VERSION 5.8 ;
BUSBITCHARS "[]" ;
DIVIDERCHAR "/" ;
UNITS
    DATABASE MICRONS 1000 ;
END UNITS

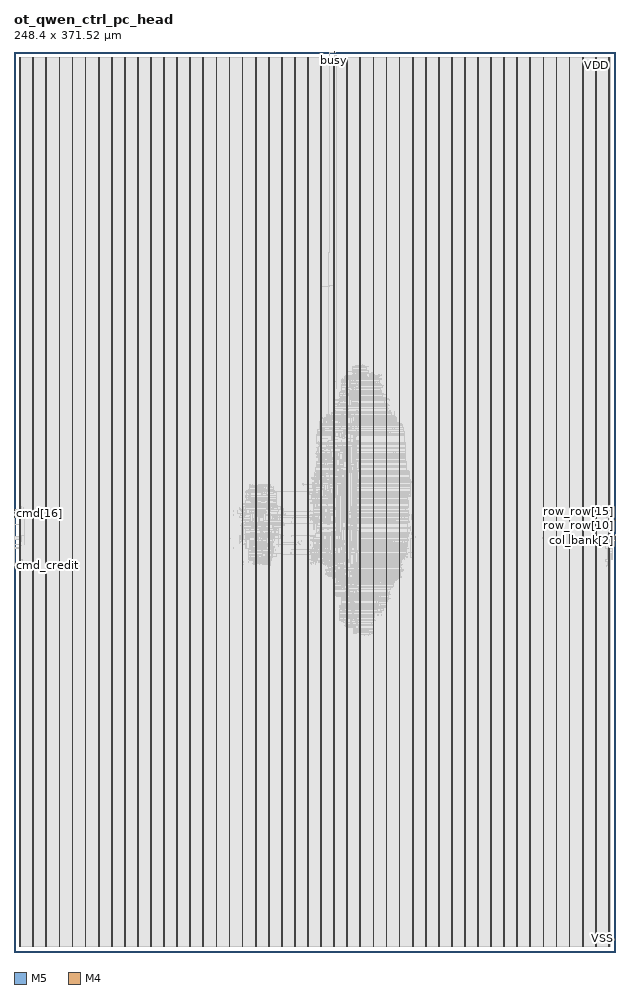
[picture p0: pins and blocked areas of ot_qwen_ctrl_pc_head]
MACRO ot_qwen_ctrl_pc_head
  FOREIGN ot_qwen_ctrl_pc_head 0 0 ;
  CLASS BLOCK ;
  SIZE 248.4 BY 371.52 ;
  PIN busy
    DIRECTION OUTPUT ;
    USE SIGNAL ;
    PORT
      LAYER M5 ;
        RECT  132.144 371.436 132.168 371.52 ;
    END
  END busy
  PIN clk
    DIRECTION INPUT ;
    USE SIGNAL ;
    PORT
      LAYER M5 ;
        RECT  132.24 371.436 132.264 371.52 ;
    END
  END clk
  PIN cmd[0]
    DIRECTION INPUT ;
    USE SIGNAL ;
    PORT
      LAYER M4 ;
        RECT  0 179.568 0.084 179.592 ;
    END
  END cmd[0]
  PIN cmd[10]
    DIRECTION INPUT ;
    USE SIGNAL ;
    PORT
      LAYER M4 ;
        RECT  0 180.528 0.084 180.552 ;
    END
  END cmd[10]
  PIN cmd[11]
    DIRECTION INPUT ;
    USE SIGNAL ;
    PORT
      LAYER M4 ;
        RECT  0 180.624 0.084 180.648 ;
    END
  END cmd[11]
  PIN cmd[12]
    DIRECTION INPUT ;
    USE SIGNAL ;
    PORT
      LAYER M4 ;
        RECT  0 180.72 0.084 180.744 ;
    END
  END cmd[12]
  PIN cmd[13]
    DIRECTION INPUT ;
    USE SIGNAL ;
    PORT
      LAYER M4 ;
        RECT  0 180.816 0.084 180.84 ;
    END
  END cmd[13]
  PIN cmd[14]
    DIRECTION INPUT ;
    USE SIGNAL ;
    PORT
      LAYER M4 ;
        RECT  0 180.912 0.084 180.936 ;
    END
  END cmd[14]
  PIN cmd[15]
    DIRECTION INPUT ;
    USE SIGNAL ;
    PORT
      LAYER M4 ;
        RECT  0 181.008 0.084 181.032 ;
    END
  END cmd[15]
  PIN cmd[16]
    DIRECTION INPUT ;
    USE SIGNAL ;
    PORT
      LAYER M4 ;
        RECT  0 181.104 0.084 181.128 ;
    END
  END cmd[16]
  PIN cmd[17]
    DIRECTION INPUT ;
    USE SIGNAL ;
    PORT
      LAYER M4 ;
        RECT  0 181.2 0.084 181.224 ;
    END
  END cmd[17]
  PIN cmd[18]
    DIRECTION INPUT ;
    USE SIGNAL ;
    PORT
      LAYER M4 ;
        RECT  0 181.296 0.084 181.32 ;
    END
  END cmd[18]
  PIN cmd[19]
    DIRECTION INPUT ;
    USE SIGNAL ;
    PORT
      LAYER M4 ;
        RECT  0 181.392 0.084 181.416 ;
    END
  END cmd[19]
  PIN cmd[1]
    DIRECTION INPUT ;
    USE SIGNAL ;
    PORT
      LAYER M4 ;
        RECT  0 179.664 0.084 179.688 ;
    END
  END cmd[1]
  PIN cmd[20]
    DIRECTION INPUT ;
    USE SIGNAL ;
    PORT
      LAYER M4 ;
        RECT  0 181.488 0.084 181.512 ;
    END
  END cmd[20]
  PIN cmd[21]
    DIRECTION INPUT ;
    USE SIGNAL ;
    PORT
      LAYER M4 ;
        RECT  0 181.584 0.084 181.608 ;
    END
  END cmd[21]
  PIN cmd[22]
    DIRECTION INPUT ;
    USE SIGNAL ;
    PORT
      LAYER M4 ;
        RECT  0 181.68 0.084 181.704 ;
    END
  END cmd[22]
  PIN cmd[23]
    DIRECTION INPUT ;
    USE SIGNAL ;
    PORT
      LAYER M4 ;
        RECT  0 181.776 0.084 181.8 ;
    END
  END cmd[23]
  PIN cmd[24]
    DIRECTION INPUT ;
    USE SIGNAL ;
    PORT
      LAYER M4 ;
        RECT  0 181.872 0.084 181.896 ;
    END
  END cmd[24]
  PIN cmd[25]
    DIRECTION INPUT ;
    USE SIGNAL ;
    PORT
      LAYER M4 ;
        RECT  0 181.968 0.084 181.992 ;
    END
  END cmd[25]
  PIN cmd[26]
    DIRECTION INPUT ;
    USE SIGNAL ;
    PORT
      LAYER M4 ;
        RECT  0 182.064 0.084 182.088 ;
    END
  END cmd[26]
  PIN cmd[27]
    DIRECTION INPUT ;
    USE SIGNAL ;
    PORT
      LAYER M4 ;
        RECT  0 182.16 0.084 182.184 ;
    END
  END cmd[27]
  PIN cmd[28]
    DIRECTION INPUT ;
    USE SIGNAL ;
    PORT
      LAYER M4 ;
        RECT  0 182.256 0.084 182.28 ;
    END
  END cmd[28]
  PIN cmd[29]
    DIRECTION INPUT ;
    USE SIGNAL ;
    PORT
      LAYER M4 ;
        RECT  0 182.352 0.084 182.376 ;
    END
  END cmd[29]
  PIN cmd[2]
    DIRECTION INPUT ;
    USE SIGNAL ;
    PORT
      LAYER M4 ;
        RECT  0 179.76 0.084 179.784 ;
    END
  END cmd[2]
  PIN cmd[30]
    DIRECTION INPUT ;
    USE SIGNAL ;
    PORT
      LAYER M4 ;
        RECT  0 182.448 0.084 182.472 ;
    END
  END cmd[30]
  PIN cmd[31]
    DIRECTION INPUT ;
    USE SIGNAL ;
    PORT
      LAYER M4 ;
        RECT  0 182.544 0.084 182.568 ;
    END
  END cmd[31]
  PIN cmd[3]
    DIRECTION INPUT ;
    USE SIGNAL ;
    PORT
      LAYER M4 ;
        RECT  0 179.856 0.084 179.88 ;
    END
  END cmd[3]
  PIN cmd[4]
    DIRECTION INPUT ;
    USE SIGNAL ;
    PORT
      LAYER M4 ;
        RECT  0 179.952 0.084 179.976 ;
    END
  END cmd[4]
  PIN cmd[5]
    DIRECTION INPUT ;
    USE SIGNAL ;
    PORT
      LAYER M4 ;
        RECT  0 180.048 0.084 180.072 ;
    END
  END cmd[5]
  PIN cmd[6]
    DIRECTION INPUT ;
    USE SIGNAL ;
    PORT
      LAYER M4 ;
        RECT  0 180.144 0.084 180.168 ;
    END
  END cmd[6]
  PIN cmd[7]
    DIRECTION INPUT ;
    USE SIGNAL ;
    PORT
      LAYER M4 ;
        RECT  0 180.24 0.084 180.264 ;
    END
  END cmd[7]
  PIN cmd[8]
    DIRECTION INPUT ;
    USE SIGNAL ;
    PORT
      LAYER M4 ;
        RECT  0 180.336 0.084 180.36 ;
    END
  END cmd[8]
  PIN cmd[9]
    DIRECTION INPUT ;
    USE SIGNAL ;
    PORT
      LAYER M4 ;
        RECT  0 180.432 0.084 180.456 ;
    END
  END cmd[9]
  PIN cmd_credit
    DIRECTION OUTPUT ;
    USE SIGNAL ;
    PORT
      LAYER M4 ;
        RECT  0 159.6 0.084 159.624 ;
    END
  END cmd_credit
  PIN cmd_v
    DIRECTION INPUT ;
    USE SIGNAL ;
    PORT
      LAYER M4 ;
        RECT  0 159.696 0.084 159.72 ;
    END
  END cmd_v
  PIN col_bank[0]
    DIRECTION OUTPUT ;
    USE SIGNAL ;
    PORT
      LAYER M4 ;
        RECT  248.316 169.68 248.4 169.704 ;
    END
  END col_bank[0]
  PIN col_bank[1]
    DIRECTION OUTPUT ;
    USE SIGNAL ;
    PORT
      LAYER M4 ;
        RECT  248.316 169.776 248.4 169.8 ;
    END
  END col_bank[1]
  PIN col_bank[2]
    DIRECTION OUTPUT ;
    USE SIGNAL ;
    PORT
      LAYER M4 ;
        RECT  248.316 169.872 248.4 169.896 ;
    END
  END col_bank[2]
  PIN col_bank[3]
    DIRECTION OUTPUT ;
    USE SIGNAL ;
    PORT
      LAYER M4 ;
        RECT  248.316 169.968 248.4 169.992 ;
    END
  END col_bank[3]
  PIN col_bank[4]
    DIRECTION OUTPUT ;
    USE SIGNAL ;
    PORT
      LAYER M4 ;
        RECT  248.316 170.064 248.4 170.088 ;
    END
  END col_bank[4]
  PIN col_col[0]
    DIRECTION OUTPUT ;
    USE SIGNAL ;
    PORT
      LAYER M4 ;
        RECT  248.316 170.16 248.4 170.184 ;
    END
  END col_col[0]
  PIN col_col[1]
    DIRECTION OUTPUT ;
    USE SIGNAL ;
    PORT
      LAYER M4 ;
        RECT  248.316 170.256 248.4 170.28 ;
    END
  END col_col[1]
  PIN col_col[2]
    DIRECTION OUTPUT ;
    USE SIGNAL ;
    PORT
      LAYER M4 ;
        RECT  248.316 170.352 248.4 170.376 ;
    END
  END col_col[2]
  PIN col_col[3]
    DIRECTION OUTPUT ;
    USE SIGNAL ;
    PORT
      LAYER M4 ;
        RECT  248.316 170.448 248.4 170.472 ;
    END
  END col_col[3]
  PIN col_col[4]
    DIRECTION OUTPUT ;
    USE SIGNAL ;
    PORT
      LAYER M4 ;
        RECT  248.316 170.544 248.4 170.568 ;
    END
  END col_col[4]
  PIN col_v
    DIRECTION OUTPUT ;
    USE SIGNAL ;
    PORT
      LAYER M4 ;
        RECT  248.316 170.64 248.4 170.664 ;
    END
  END col_v
  PIN col_we
    DIRECTION OUTPUT ;
    USE SIGNAL ;
    PORT
      LAYER M4 ;
        RECT  248.316 170.736 248.4 170.76 ;
    END
  END col_we
  PIN fault
    DIRECTION OUTPUT ;
    USE SIGNAL ;
    PORT
      LAYER M5 ;
        RECT  132.336 371.436 132.36 371.52 ;
    END
  END fault
  PIN read_credit[0]
    DIRECTION INPUT ;
    USE SIGNAL ;
    PORT
      LAYER M4 ;
        RECT  0 159.792 0.084 159.816 ;
    END
  END read_credit[0]
  PIN read_credit[1]
    DIRECTION INPUT ;
    USE SIGNAL ;
    PORT
      LAYER M4 ;
        RECT  0 159.888 0.084 159.912 ;
    END
  END read_credit[1]
  PIN read_credit[2]
    DIRECTION INPUT ;
    USE SIGNAL ;
    PORT
      LAYER M4 ;
        RECT  0 159.984 0.084 160.008 ;
    END
  END read_credit[2]
  PIN row_bank[0]
    DIRECTION OUTPUT ;
    USE SIGNAL ;
    PORT
      LAYER M4 ;
        RECT  248.316 170.832 248.4 170.856 ;
    END
  END row_bank[0]
  PIN row_bank[1]
    DIRECTION OUTPUT ;
    USE SIGNAL ;
    PORT
      LAYER M4 ;
        RECT  248.316 170.928 248.4 170.952 ;
    END
  END row_bank[1]
  PIN row_bank[2]
    DIRECTION OUTPUT ;
    USE SIGNAL ;
    PORT
      LAYER M4 ;
        RECT  248.316 171.024 248.4 171.048 ;
    END
  END row_bank[2]
  PIN row_bank[3]
    DIRECTION OUTPUT ;
    USE SIGNAL ;
    PORT
      LAYER M4 ;
        RECT  248.316 171.12 248.4 171.144 ;
    END
  END row_bank[3]
  PIN row_bank[4]
    DIRECTION OUTPUT ;
    USE SIGNAL ;
    PORT
      LAYER M4 ;
        RECT  248.316 171.216 248.4 171.24 ;
    END
  END row_bank[4]
  PIN row_op[0]
    DIRECTION OUTPUT ;
    USE SIGNAL ;
    PORT
      LAYER M4 ;
        RECT  248.316 171.312 248.4 171.336 ;
    END
  END row_op[0]
  PIN row_op[1]
    DIRECTION OUTPUT ;
    USE SIGNAL ;
    PORT
      LAYER M4 ;
        RECT  248.316 171.408 248.4 171.432 ;
    END
  END row_op[1]
  PIN row_op[2]
    DIRECTION OUTPUT ;
    USE SIGNAL ;
    PORT
      LAYER M4 ;
        RECT  248.316 171.504 248.4 171.528 ;
    END
  END row_op[2]
  PIN row_row[0]
    DIRECTION OUTPUT ;
    USE SIGNAL ;
    PORT
      LAYER M4 ;
        RECT  248.316 171.6 248.4 171.624 ;
    END
  END row_row[0]
  PIN row_row[10]
    DIRECTION OUTPUT ;
    USE SIGNAL ;
    PORT
      LAYER M4 ;
        RECT  248.316 172.56 248.4 172.584 ;
    END
  END row_row[10]
  PIN row_row[11]
    DIRECTION OUTPUT ;
    USE SIGNAL ;
    PORT
      LAYER M4 ;
        RECT  248.316 172.656 248.4 172.68 ;
    END
  END row_row[11]
  PIN row_row[12]
    DIRECTION OUTPUT ;
    USE SIGNAL ;
    PORT
      LAYER M4 ;
        RECT  248.316 178.128 248.4 178.152 ;
    END
  END row_row[12]
  PIN row_row[13]
    DIRECTION OUTPUT ;
    USE SIGNAL ;
    PORT
      LAYER M4 ;
        RECT  248.316 178.224 248.4 178.248 ;
    END
  END row_row[13]
  PIN row_row[14]
    DIRECTION OUTPUT ;
    USE SIGNAL ;
    PORT
      LAYER M4 ;
        RECT  248.316 178.32 248.4 178.344 ;
    END
  END row_row[14]
  PIN row_row[15]
    DIRECTION OUTPUT ;
    USE SIGNAL ;
    PORT
      LAYER M4 ;
        RECT  248.316 178.416 248.4 178.44 ;
    END
  END row_row[15]
  PIN row_row[16]
    DIRECTION OUTPUT ;
    USE SIGNAL ;
    PORT
      LAYER M4 ;
        RECT  248.316 178.512 248.4 178.536 ;
    END
  END row_row[16]
  PIN row_row[17]
    DIRECTION OUTPUT ;
    USE SIGNAL ;
    PORT
      LAYER M4 ;
        RECT  248.316 178.608 248.4 178.632 ;
    END
  END row_row[17]
  PIN row_row[18]
    DIRECTION OUTPUT ;
    USE SIGNAL ;
    PORT
      LAYER M4 ;
        RECT  248.316 178.704 248.4 178.728 ;
    END
  END row_row[18]
  PIN row_row[1]
    DIRECTION OUTPUT ;
    USE SIGNAL ;
    PORT
      LAYER M4 ;
        RECT  248.316 171.696 248.4 171.72 ;
    END
  END row_row[1]
  PIN row_row[2]
    DIRECTION OUTPUT ;
    USE SIGNAL ;
    PORT
      LAYER M4 ;
        RECT  248.316 171.792 248.4 171.816 ;
    END
  END row_row[2]
  PIN row_row[3]
    DIRECTION OUTPUT ;
    USE SIGNAL ;
    PORT
      LAYER M4 ;
        RECT  248.316 171.888 248.4 171.912 ;
    END
  END row_row[3]
  PIN row_row[4]
    DIRECTION OUTPUT ;
    USE SIGNAL ;
    PORT
      LAYER M4 ;
        RECT  248.316 171.984 248.4 172.008 ;
    END
  END row_row[4]
  PIN row_row[5]
    DIRECTION OUTPUT ;
    USE SIGNAL ;
    PORT
      LAYER M4 ;
        RECT  248.316 172.08 248.4 172.104 ;
    END
  END row_row[5]
  PIN row_row[6]
    DIRECTION OUTPUT ;
    USE SIGNAL ;
    PORT
      LAYER M4 ;
        RECT  248.316 172.176 248.4 172.2 ;
    END
  END row_row[6]
  PIN row_row[7]
    DIRECTION OUTPUT ;
    USE SIGNAL ;
    PORT
      LAYER M4 ;
        RECT  248.316 172.272 248.4 172.296 ;
    END
  END row_row[7]
  PIN row_row[8]
    DIRECTION OUTPUT ;
    USE SIGNAL ;
    PORT
      LAYER M4 ;
        RECT  248.316 172.368 248.4 172.392 ;
    END
  END row_row[8]
  PIN row_row[9]
    DIRECTION OUTPUT ;
    USE SIGNAL ;
    PORT
      LAYER M4 ;
        RECT  248.316 172.464 248.4 172.488 ;
    END
  END row_row[9]
  PIN row_v
    DIRECTION OUTPUT ;
    USE SIGNAL ;
    PORT
      LAYER M4 ;
        RECT  248.316 178.8 248.4 178.824 ;
    END
  END row_v
  PIN rst_n
    DIRECTION INPUT ;
    USE SIGNAL ;
    PORT
      LAYER M5 ;
        RECT  132.432 371.436 132.456 371.52 ;
    END
  END rst_n
  PIN VDD
    DIRECTION INOUT ;
    USE POWER ;
    PORT
      LAYER M5 ;
        RECT  245.592 2.151 245.712 369.369 ;
        RECT  240.192 2.151 240.312 369.369 ;
        RECT  234.792 2.151 234.912 369.369 ;
        RECT  229.392 2.151 229.512 369.369 ;
        RECT  223.992 2.151 224.112 369.369 ;
        RECT  218.592 2.151 218.712 369.369 ;
        RECT  213.192 2.151 213.312 369.369 ;
        RECT  207.792 2.151 207.912 369.369 ;
        RECT  202.392 2.151 202.512 369.369 ;
        RECT  196.992 2.151 197.112 369.369 ;
        RECT  191.592 2.151 191.712 369.369 ;
        RECT  186.192 2.151 186.312 369.369 ;
        RECT  180.792 2.151 180.912 369.369 ;
        RECT  175.392 2.151 175.512 369.369 ;
        RECT  169.992 2.151 170.112 369.369 ;
        RECT  164.592 2.151 164.712 369.369 ;
        RECT  159.192 2.151 159.312 369.369 ;
        RECT  153.792 2.151 153.912 369.369 ;
        RECT  148.392 2.151 148.512 369.369 ;
        RECT  142.992 2.151 143.112 369.369 ;
        RECT  137.592 2.151 137.712 369.369 ;
        RECT  132.192 2.151 132.312 369.369 ;
        RECT  126.792 2.151 126.912 369.369 ;
        RECT  121.392 2.151 121.512 369.369 ;
        RECT  115.992 2.151 116.112 369.369 ;
        RECT  110.592 2.151 110.712 369.369 ;
        RECT  105.192 2.151 105.312 369.369 ;
        RECT  99.792 2.151 99.912 369.369 ;
        RECT  94.392 2.151 94.512 369.369 ;
        RECT  88.992 2.151 89.112 369.369 ;
        RECT  83.592 2.151 83.712 369.369 ;
        RECT  78.192 2.151 78.312 369.369 ;
        RECT  72.792 2.151 72.912 369.369 ;
        RECT  67.392 2.151 67.512 369.369 ;
        RECT  61.992 2.151 62.112 369.369 ;
        RECT  56.592 2.151 56.712 369.369 ;
        RECT  51.192 2.151 51.312 369.369 ;
        RECT  45.792 2.151 45.912 369.369 ;
        RECT  40.392 2.151 40.512 369.369 ;
        RECT  34.992 2.151 35.112 369.369 ;
        RECT  29.592 2.151 29.712 369.369 ;
        RECT  24.192 2.151 24.312 369.369 ;
        RECT  18.792 2.151 18.912 369.369 ;
        RECT  13.392 2.151 13.512 369.369 ;
        RECT  7.992 2.151 8.112 369.369 ;
        RECT  2.592 2.151 2.712 369.369 ;
    END
  END VDD
  PIN VSS
    DIRECTION INOUT ;
    USE GROUND ;
    PORT
      LAYER M5 ;
        RECT  245.4 2.137 245.52 369.383 ;
        RECT  240 2.137 240.12 369.383 ;
        RECT  234.6 2.137 234.72 369.383 ;
        RECT  229.2 2.137 229.32 369.383 ;
        RECT  223.8 2.137 223.92 369.383 ;
        RECT  218.4 2.137 218.52 369.383 ;
        RECT  213 2.137 213.12 369.383 ;
        RECT  207.6 2.137 207.72 369.383 ;
        RECT  202.2 2.137 202.32 369.383 ;
        RECT  196.8 2.137 196.92 369.383 ;
        RECT  191.4 2.137 191.52 369.383 ;
        RECT  186 2.137 186.12 369.383 ;
        RECT  180.6 2.137 180.72 369.383 ;
        RECT  175.2 2.137 175.32 369.383 ;
        RECT  169.8 2.137 169.92 369.383 ;
        RECT  164.4 2.137 164.52 369.383 ;
        RECT  159 2.137 159.12 369.383 ;
        RECT  153.6 2.137 153.72 369.383 ;
        RECT  148.2 2.137 148.32 369.383 ;
        RECT  142.8 2.137 142.92 369.383 ;
        RECT  137.4 2.137 137.52 369.383 ;
        RECT  132 2.137 132.12 369.383 ;
        RECT  126.6 2.137 126.72 369.383 ;
        RECT  121.2 2.137 121.32 369.383 ;
        RECT  115.8 2.137 115.92 369.383 ;
        RECT  110.4 2.137 110.52 369.383 ;
        RECT  105 2.137 105.12 369.383 ;
        RECT  99.6 2.137 99.72 369.383 ;
        RECT  94.2 2.137 94.32 369.383 ;
        RECT  88.8 2.137 88.92 369.383 ;
        RECT  83.4 2.137 83.52 369.383 ;
        RECT  78 2.137 78.12 369.383 ;
        RECT  72.6 2.137 72.72 369.383 ;
        RECT  67.2 2.137 67.32 369.383 ;
        RECT  61.8 2.137 61.92 369.383 ;
        RECT  56.4 2.137 56.52 369.383 ;
        RECT  51 2.137 51.12 369.383 ;
        RECT  45.6 2.137 45.72 369.383 ;
        RECT  40.2 2.137 40.32 369.383 ;
        RECT  34.8 2.137 34.92 369.383 ;
        RECT  29.4 2.137 29.52 369.383 ;
        RECT  24 2.137 24.12 369.383 ;
        RECT  18.6 2.137 18.72 369.383 ;
        RECT  13.2 2.137 13.32 369.383 ;
        RECT  7.8 2.137 7.92 369.383 ;
        RECT  2.4 2.137 2.52 369.383 ;
    END
  END VSS
  OBS
    LAYER RVTN ;
     RECT  2.16 2.16 246.24 2.295 ;
     RECT  2.16 2.565 246.24 2.835 ;
     RECT  2.16 3.105 246.24 3.375 ;
     RECT  2.16 3.645 246.24 3.915 ;
     RECT  2.16 4.185 246.24 4.455 ;
     RECT  2.16 4.725 246.24 4.995 ;
     RECT  2.16 5.265 246.24 5.535 ;
     RECT  2.16 5.805 246.24 6.075 ;
     RECT  2.16 6.345 246.24 6.615 ;
     RECT  2.16 6.885 246.24 7.155 ;
     RECT  2.16 7.425 246.24 7.695 ;
     RECT  2.16 7.965 246.24 8.235 ;
     RECT  2.16 8.505 246.24 8.775 ;
     RECT  2.16 9.045 246.24 9.315 ;
     RECT  2.16 9.585 246.24 9.855 ;
     RECT  2.16 10.125 246.24 10.395 ;
     RECT  2.16 10.665 246.24 10.935 ;
     RECT  2.16 11.205 246.24 11.475 ;
     RECT  2.16 11.745 246.24 12.015 ;
     RECT  2.16 12.285 246.24 12.555 ;
     RECT  2.16 12.825 246.24 13.095 ;
     RECT  2.16 13.365 246.24 13.635 ;
     RECT  2.16 13.905 246.24 14.175 ;
     RECT  2.16 14.445 246.24 14.715 ;
     RECT  2.16 14.985 246.24 15.255 ;
     RECT  2.16 15.525 246.24 15.795 ;
     RECT  2.16 16.065 246.24 16.335 ;
     RECT  2.16 16.605 246.24 16.875 ;
     RECT  2.16 17.145 246.24 17.415 ;
     RECT  2.16 17.685 246.24 17.955 ;
     RECT  2.16 18.225 246.24 18.495 ;
     RECT  2.16 18.765 246.24 19.035 ;
     RECT  2.16 19.305 246.24 19.575 ;
     RECT  2.16 19.845 246.24 20.115 ;
     RECT  2.16 20.385 246.24 20.655 ;
     RECT  2.16 20.925 246.24 21.195 ;
     RECT  2.16 21.465 246.24 21.735 ;
     RECT  2.16 22.005 246.24 22.275 ;
     RECT  2.16 22.545 246.24 22.815 ;
     RECT  2.16 23.085 246.24 23.355 ;
     RECT  2.16 23.625 246.24 23.895 ;
     RECT  2.16 24.165 246.24 24.435 ;
     RECT  2.16 24.705 246.24 24.975 ;
     RECT  2.16 25.245 246.24 25.515 ;
     RECT  2.16 25.785 246.24 26.055 ;
     RECT  2.16 26.325 246.24 26.595 ;
     RECT  2.16 26.865 246.24 27.135 ;
     RECT  2.16 27.405 246.24 27.675 ;
     RECT  2.16 27.945 246.24 28.215 ;
     RECT  2.16 28.485 246.24 28.755 ;
     RECT  2.16 29.025 246.24 29.295 ;
     RECT  2.16 29.565 246.24 29.835 ;
     RECT  2.16 30.105 246.24 30.375 ;
     RECT  2.16 30.645 246.24 30.915 ;
     RECT  2.16 31.185 246.24 31.455 ;
     RECT  2.16 31.725 246.24 31.995 ;
     RECT  2.16 32.265 246.24 32.535 ;
     RECT  2.16 32.805 246.24 33.075 ;
     RECT  2.16 33.345 246.24 33.615 ;
     RECT  2.16 33.885 246.24 34.155 ;
     RECT  2.16 34.425 246.24 34.695 ;
     RECT  2.16 34.965 246.24 35.235 ;
     RECT  2.16 35.505 246.24 35.775 ;
     RECT  2.16 36.045 246.24 36.315 ;
     RECT  2.16 36.585 246.24 36.855 ;
     RECT  2.16 37.125 246.24 37.395 ;
     RECT  2.16 37.665 246.24 37.935 ;
     RECT  2.16 38.205 246.24 38.475 ;
     RECT  2.16 38.745 246.24 39.015 ;
     RECT  2.16 39.285 246.24 39.555 ;
     RECT  2.16 39.825 246.24 40.095 ;
     RECT  2.16 40.365 246.24 40.635 ;
     RECT  2.16 40.905 246.24 41.175 ;
     RECT  2.16 41.445 246.24 41.715 ;
     RECT  2.16 41.985 246.24 42.255 ;
     RECT  2.16 42.525 246.24 42.795 ;
     RECT  2.16 43.065 246.24 43.335 ;
     RECT  2.16 43.605 246.24 43.875 ;
     RECT  2.16 44.145 246.24 44.415 ;
     RECT  2.16 44.685 246.24 44.955 ;
     RECT  2.16 45.225 246.24 45.495 ;
     RECT  2.16 45.765 246.24 46.035 ;
     RECT  2.16 46.305 246.24 46.575 ;
     RECT  2.16 46.845 246.24 47.115 ;
     RECT  2.16 47.385 246.24 47.655 ;
     RECT  2.16 47.925 246.24 48.195 ;
     RECT  2.16 48.465 246.24 48.735 ;
     RECT  2.16 49.005 246.24 49.275 ;
     RECT  2.16 49.545 246.24 49.815 ;
     RECT  2.16 50.085 246.24 50.355 ;
     RECT  2.16 50.625 246.24 50.895 ;
     RECT  2.16 51.165 246.24 51.435 ;
     RECT  2.16 51.705 246.24 51.975 ;
     RECT  2.16 52.245 246.24 52.515 ;
     RECT  2.16 52.785 246.24 53.055 ;
     RECT  2.16 53.325 246.24 53.595 ;
     RECT  2.16 53.865 246.24 54.135 ;
     RECT  2.16 54.405 246.24 54.675 ;
     RECT  2.16 54.945 246.24 55.215 ;
     RECT  2.16 55.485 246.24 55.755 ;
     RECT  2.16 56.025 246.24 56.295 ;
     RECT  2.16 56.565 246.24 56.835 ;
     RECT  2.16 57.105 246.24 57.375 ;
     RECT  2.16 57.645 246.24 57.915 ;
     RECT  2.16 58.185 246.24 58.455 ;
     RECT  2.16 58.725 246.24 58.995 ;
     RECT  2.16 59.265 246.24 59.535 ;
     RECT  2.16 59.805 246.24 60.075 ;
     RECT  2.16 60.345 246.24 60.615 ;
     RECT  2.16 60.885 246.24 61.155 ;
     RECT  2.16 61.425 246.24 61.695 ;
     RECT  2.16 61.965 246.24 62.235 ;
     RECT  2.16 62.505 246.24 62.775 ;
     RECT  2.16 63.045 246.24 63.315 ;
     RECT  2.16 63.585 246.24 63.855 ;
     RECT  2.16 64.125 246.24 64.395 ;
     RECT  2.16 64.665 246.24 64.935 ;
     RECT  2.16 65.205 246.24 65.475 ;
     RECT  2.16 65.745 246.24 66.015 ;
     RECT  2.16 66.285 246.24 66.555 ;
     RECT  2.16 66.825 246.24 67.095 ;
     RECT  2.16 67.365 246.24 67.635 ;
     RECT  2.16 67.905 246.24 68.175 ;
     RECT  2.16 68.445 246.24 68.715 ;
     RECT  2.16 68.985 246.24 69.255 ;
     RECT  2.16 69.525 246.24 69.795 ;
     RECT  2.16 70.065 246.24 70.335 ;
     RECT  2.16 70.605 246.24 70.875 ;
     RECT  2.16 71.145 246.24 71.415 ;
     RECT  2.16 71.685 246.24 71.955 ;
     RECT  2.16 72.225 246.24 72.495 ;
     RECT  2.16 72.765 246.24 73.035 ;
     RECT  2.16 73.305 246.24 73.575 ;
     RECT  2.16 73.845 246.24 74.115 ;
     RECT  2.16 74.385 246.24 74.655 ;
     RECT  2.16 74.925 246.24 75.195 ;
     RECT  2.16 75.465 246.24 75.735 ;
     RECT  2.16 76.005 246.24 76.275 ;
     RECT  2.16 76.545 246.24 76.815 ;
     RECT  2.16 77.085 246.24 77.355 ;
     RECT  2.16 77.625 246.24 77.895 ;
     RECT  2.16 78.165 246.24 78.435 ;
     RECT  2.16 78.705 246.24 78.975 ;
     RECT  2.16 79.245 246.24 79.515 ;
     RECT  2.16 79.785 246.24 80.055 ;
     RECT  2.16 80.325 246.24 80.595 ;
     RECT  2.16 80.865 246.24 81.135 ;
     RECT  2.16 81.405 246.24 81.675 ;
     RECT  2.16 81.945 246.24 82.215 ;
     RECT  2.16 82.485 246.24 82.755 ;
     RECT  2.16 83.025 246.24 83.295 ;
     RECT  2.16 83.565 246.24 83.835 ;
     RECT  2.16 84.105 246.24 84.375 ;
     RECT  2.16 84.645 246.24 84.915 ;
     RECT  2.16 85.185 246.24 85.455 ;
     RECT  2.16 85.725 246.24 85.995 ;
     RECT  2.16 86.265 246.24 86.535 ;
     RECT  2.16 86.805 246.24 87.075 ;
     RECT  2.16 87.345 246.24 87.615 ;
     RECT  2.16 87.885 246.24 88.155 ;
     RECT  2.16 88.425 246.24 88.695 ;
     RECT  2.16 88.965 246.24 89.235 ;
     RECT  2.16 89.505 246.24 89.775 ;
     RECT  2.16 90.045 246.24 90.315 ;
     RECT  2.16 90.585 246.24 90.855 ;
     RECT  2.16 91.125 246.24 91.395 ;
     RECT  2.16 91.665 246.24 91.935 ;
     RECT  2.16 92.205 246.24 92.475 ;
     RECT  2.16 92.745 246.24 93.015 ;
     RECT  2.16 93.285 246.24 93.555 ;
     RECT  2.16 93.825 246.24 94.095 ;
     RECT  2.16 94.365 246.24 94.635 ;
     RECT  2.16 94.905 246.24 95.175 ;
     RECT  2.16 95.445 246.24 95.715 ;
     RECT  2.16 95.985 246.24 96.255 ;
     RECT  2.16 96.525 246.24 96.795 ;
     RECT  2.16 97.065 246.24 97.335 ;
     RECT  2.16 97.605 246.24 97.875 ;
     RECT  2.16 98.145 246.24 98.415 ;
     RECT  2.16 98.685 246.24 98.955 ;
     RECT  2.16 99.225 246.24 99.495 ;
     RECT  2.16 99.765 246.24 100.035 ;
     RECT  2.16 100.305 246.24 100.575 ;
     RECT  2.16 100.845 246.24 101.115 ;
     RECT  2.16 101.385 246.24 101.655 ;
     RECT  2.16 101.925 246.24 102.195 ;
     RECT  2.16 102.465 246.24 102.735 ;
     RECT  2.16 103.005 246.24 103.275 ;
     RECT  2.16 103.545 246.24 103.815 ;
     RECT  2.16 104.085 246.24 104.355 ;
     RECT  2.16 104.625 246.24 104.895 ;
     RECT  2.16 105.165 246.24 105.435 ;
     RECT  2.16 105.705 246.24 105.975 ;
     RECT  2.16 106.245 246.24 106.515 ;
     RECT  2.16 106.785 246.24 107.055 ;
     RECT  2.16 107.325 246.24 107.595 ;
     RECT  2.16 107.865 246.24 108.135 ;
     RECT  2.16 108.405 246.24 108.675 ;
     RECT  2.16 108.945 246.24 109.215 ;
     RECT  2.16 109.485 246.24 109.755 ;
     RECT  2.16 110.025 246.24 110.295 ;
     RECT  2.16 110.565 246.24 110.835 ;
     RECT  2.16 111.105 246.24 111.375 ;
     RECT  2.16 111.645 246.24 111.915 ;
     RECT  2.16 112.185 246.24 112.455 ;
     RECT  2.16 112.725 246.24 112.995 ;
     RECT  2.16 113.265 246.24 113.535 ;
     RECT  2.16 113.805 246.24 114.075 ;
     RECT  2.16 114.345 246.24 114.615 ;
     RECT  2.16 114.885 246.24 115.155 ;
     RECT  2.16 115.425 246.24 115.695 ;
     RECT  2.16 115.965 246.24 116.235 ;
     RECT  2.16 116.505 246.24 116.775 ;
     RECT  2.16 117.045 246.24 117.315 ;
     RECT  2.16 117.585 246.24 117.855 ;
     RECT  2.16 118.125 246.24 118.395 ;
     RECT  2.16 118.665 246.24 118.935 ;
     RECT  2.16 119.205 246.24 119.475 ;
     RECT  2.16 119.745 246.24 120.015 ;
     RECT  2.16 120.285 246.24 120.555 ;
     RECT  2.16 120.825 246.24 121.095 ;
     RECT  2.16 121.365 246.24 121.635 ;
     RECT  2.16 121.905 246.24 122.175 ;
     RECT  2.16 122.445 246.24 122.715 ;
     RECT  2.16 122.985 246.24 123.255 ;
     RECT  2.16 123.525 246.24 123.795 ;
     RECT  2.16 124.065 246.24 124.335 ;
     RECT  2.16 124.605 246.24 124.875 ;
     RECT  2.16 125.145 246.24 125.415 ;
     RECT  2.16 125.685 246.24 125.955 ;
     RECT  2.16 126.225 246.24 126.495 ;
     RECT  2.16 126.765 246.24 127.035 ;
     RECT  2.16 127.305 246.24 127.575 ;
     RECT  2.16 127.845 246.24 128.115 ;
     RECT  2.16 128.385 246.24 128.655 ;
     RECT  2.16 128.925 246.24 129.195 ;
     RECT  2.16 129.465 246.24 129.735 ;
     RECT  2.16 130.005 246.24 130.275 ;
     RECT  2.16 130.545 246.24 130.815 ;
     RECT  2.16 131.085 246.24 131.355 ;
     RECT  2.16 131.625 246.24 131.895 ;
     RECT  2.16 132.165 246.24 132.435 ;
     RECT  2.16 132.705 246.24 132.975 ;
     RECT  2.16 133.245 246.24 133.515 ;
     RECT  2.16 133.785 246.24 134.055 ;
     RECT  2.16 134.325 246.24 134.595 ;
     RECT  2.16 134.865 246.24 135.135 ;
     RECT  2.16 135.405 246.24 135.675 ;
     RECT  2.16 135.945 246.24 136.215 ;
     RECT  2.16 136.485 246.24 136.755 ;
     RECT  2.16 137.025 246.24 137.295 ;
     RECT  2.16 137.565 246.24 137.835 ;
     RECT  2.16 138.105 246.24 138.375 ;
     RECT  2.16 138.645 246.24 138.915 ;
     RECT  2.16 139.185 246.24 139.455 ;
     RECT  2.16 139.725 246.24 139.995 ;
     RECT  2.16 140.265 246.24 140.535 ;
     RECT  2.16 140.805 246.24 141.075 ;
     RECT  2.16 141.345 246.24 141.615 ;
     RECT  2.16 141.885 246.24 142.155 ;
     RECT  2.16 142.425 246.24 142.695 ;
     RECT  2.16 142.965 246.24 143.235 ;
     RECT  2.16 143.505 246.24 143.775 ;
     RECT  2.16 144.045 246.24 144.315 ;
     RECT  2.16 144.585 246.24 144.855 ;
     RECT  2.16 145.125 246.24 145.395 ;
     RECT  2.16 145.665 246.24 145.935 ;
     RECT  2.16 146.205 246.24 146.475 ;
     RECT  2.16 146.745 246.24 147.015 ;
     RECT  2.16 147.285 246.24 147.555 ;
     RECT  2.16 147.825 246.24 148.095 ;
     RECT  2.16 148.365 246.24 148.635 ;
     RECT  2.16 148.905 246.24 149.175 ;
     RECT  2.16 149.445 246.24 149.715 ;
     RECT  2.16 149.985 246.24 150.255 ;
     RECT  2.16 150.525 246.24 150.795 ;
     RECT  2.16 151.065 246.24 151.335 ;
     RECT  2.16 151.605 246.24 151.875 ;
     RECT  2.16 152.145 246.24 152.415 ;
     RECT  2.16 152.685 246.24 152.955 ;
     RECT  2.16 153.225 246.24 153.495 ;
     RECT  2.16 153.765 246.24 154.035 ;
     RECT  2.16 154.305 246.24 154.575 ;
     RECT  2.16 154.845 246.24 155.115 ;
     RECT  2.16 155.385 246.24 155.655 ;
     RECT  2.16 155.925 246.24 156.195 ;
     RECT  2.16 156.465 246.24 156.735 ;
     RECT  2.16 157.005 246.24 157.275 ;
     RECT  2.16 157.545 246.24 157.815 ;
     RECT  2.16 158.085 246.24 158.355 ;
     RECT  2.16 158.625 246.24 158.895 ;
     RECT  2.16 159.165 246.24 159.435 ;
     RECT  2.16 159.705 246.24 159.975 ;
     RECT  2.16 160.245 246.24 160.515 ;
     RECT  2.16 160.785 246.24 161.055 ;
     RECT  2.16 161.325 246.24 161.595 ;
     RECT  2.16 161.865 246.24 162.135 ;
     RECT  2.16 162.405 246.24 162.675 ;
     RECT  2.16 162.945 246.24 163.215 ;
     RECT  2.16 163.485 246.24 163.755 ;
     RECT  2.16 164.025 246.24 164.295 ;
     RECT  2.16 164.565 246.24 164.835 ;
     RECT  2.16 165.105 246.24 165.375 ;
     RECT  2.16 165.645 246.24 165.915 ;
     RECT  2.16 166.185 246.24 166.455 ;
     RECT  2.16 166.725 246.24 166.995 ;
     RECT  2.16 167.265 246.24 167.535 ;
     RECT  2.16 167.805 246.24 168.075 ;
     RECT  2.16 168.345 246.24 168.615 ;
     RECT  2.16 168.885 246.24 169.155 ;
     RECT  2.16 169.425 246.24 169.695 ;
     RECT  2.16 169.965 246.24 170.235 ;
     RECT  2.16 170.505 246.24 170.775 ;
     RECT  2.16 171.045 246.24 171.315 ;
     RECT  2.16 171.585 246.24 171.855 ;
     RECT  2.16 172.125 246.24 172.395 ;
     RECT  2.16 172.665 246.24 172.935 ;
     RECT  2.16 173.205 246.24 173.475 ;
     RECT  2.16 173.745 246.24 174.015 ;
     RECT  2.16 174.285 246.24 174.555 ;
     RECT  2.16 174.825 246.24 175.095 ;
     RECT  2.16 175.365 246.24 175.635 ;
     RECT  2.16 175.905 246.24 176.175 ;
     RECT  2.16 176.445 246.24 176.715 ;
     RECT  2.16 176.985 246.24 177.255 ;
     RECT  2.16 177.525 246.24 177.795 ;
     RECT  2.16 178.065 246.24 178.335 ;
     RECT  2.16 178.605 246.24 178.875 ;
     RECT  2.16 179.145 246.24 179.415 ;
     RECT  2.16 179.685 246.24 179.955 ;
     RECT  2.16 180.225 246.24 180.495 ;
     RECT  2.16 180.765 246.24 181.035 ;
     RECT  2.16 181.305 246.24 181.575 ;
     RECT  2.16 181.845 246.24 182.115 ;
     RECT  2.16 182.385 246.24 182.655 ;
     RECT  2.16 182.925 246.24 183.195 ;
     RECT  2.16 183.465 246.24 183.735 ;
     RECT  2.16 184.005 246.24 184.275 ;
     RECT  2.16 184.545 246.24 184.815 ;
     RECT  2.16 185.085 246.24 185.355 ;
     RECT  2.16 185.625 246.24 185.895 ;
     RECT  2.16 186.165 246.24 186.435 ;
     RECT  2.16 186.705 246.24 186.975 ;
     RECT  2.16 187.245 246.24 187.515 ;
     RECT  2.16 187.785 246.24 188.055 ;
     RECT  2.16 188.325 246.24 188.595 ;
     RECT  2.16 188.865 246.24 189.135 ;
     RECT  2.16 189.405 246.24 189.675 ;
     RECT  2.16 189.945 246.24 190.215 ;
     RECT  2.16 190.485 246.24 190.755 ;
     RECT  2.16 191.025 246.24 191.295 ;
     RECT  2.16 191.565 246.24 191.835 ;
     RECT  2.16 192.105 246.24 192.375 ;
     RECT  2.16 192.645 246.24 192.915 ;
     RECT  2.16 193.185 246.24 193.455 ;
     RECT  2.16 193.725 246.24 193.995 ;
     RECT  2.16 194.265 246.24 194.535 ;
     RECT  2.16 194.805 246.24 195.075 ;
     RECT  2.16 195.345 246.24 195.615 ;
     RECT  2.16 195.885 246.24 196.155 ;
     RECT  2.16 196.425 246.24 196.695 ;
     RECT  2.16 196.965 246.24 197.235 ;
     RECT  2.16 197.505 246.24 197.775 ;
     RECT  2.16 198.045 246.24 198.315 ;
     RECT  2.16 198.585 246.24 198.855 ;
     RECT  2.16 199.125 246.24 199.395 ;
     RECT  2.16 199.665 246.24 199.935 ;
     RECT  2.16 200.205 246.24 200.475 ;
     RECT  2.16 200.745 246.24 201.015 ;
     RECT  2.16 201.285 246.24 201.555 ;
     RECT  2.16 201.825 246.24 202.095 ;
     RECT  2.16 202.365 246.24 202.635 ;
     RECT  2.16 202.905 246.24 203.175 ;
     RECT  2.16 203.445 246.24 203.715 ;
     RECT  2.16 203.985 246.24 204.255 ;
     RECT  2.16 204.525 246.24 204.795 ;
     RECT  2.16 205.065 246.24 205.335 ;
     RECT  2.16 205.605 246.24 205.875 ;
     RECT  2.16 206.145 246.24 206.415 ;
     RECT  2.16 206.685 246.24 206.955 ;
     RECT  2.16 207.225 246.24 207.495 ;
     RECT  2.16 207.765 246.24 208.035 ;
     RECT  2.16 208.305 246.24 208.575 ;
     RECT  2.16 208.845 246.24 209.115 ;
     RECT  2.16 209.385 246.24 209.655 ;
     RECT  2.16 209.925 246.24 210.195 ;
     RECT  2.16 210.465 246.24 210.735 ;
     RECT  2.16 211.005 246.24 211.275 ;
     RECT  2.16 211.545 246.24 211.815 ;
     RECT  2.16 212.085 246.24 212.355 ;
     RECT  2.16 212.625 246.24 212.895 ;
     RECT  2.16 213.165 246.24 213.435 ;
     RECT  2.16 213.705 246.24 213.975 ;
     RECT  2.16 214.245 246.24 214.515 ;
     RECT  2.16 214.785 246.24 215.055 ;
     RECT  2.16 215.325 246.24 215.595 ;
     RECT  2.16 215.865 246.24 216.135 ;
     RECT  2.16 216.405 246.24 216.675 ;
     RECT  2.16 216.945 246.24 217.215 ;
     RECT  2.16 217.485 246.24 217.755 ;
     RECT  2.16 218.025 246.24 218.295 ;
     RECT  2.16 218.565 246.24 218.835 ;
     RECT  2.16 219.105 246.24 219.375 ;
     RECT  2.16 219.645 246.24 219.915 ;
     RECT  2.16 220.185 246.24 220.455 ;
     RECT  2.16 220.725 246.24 220.995 ;
     RECT  2.16 221.265 246.24 221.535 ;
     RECT  2.16 221.805 246.24 222.075 ;
     RECT  2.16 222.345 246.24 222.615 ;
     RECT  2.16 222.885 246.24 223.155 ;
     RECT  2.16 223.425 246.24 223.695 ;
     RECT  2.16 223.965 246.24 224.235 ;
     RECT  2.16 224.505 246.24 224.775 ;
     RECT  2.16 225.045 246.24 225.315 ;
     RECT  2.16 225.585 246.24 225.855 ;
     RECT  2.16 226.125 246.24 226.395 ;
     RECT  2.16 226.665 246.24 226.935 ;
     RECT  2.16 227.205 246.24 227.475 ;
     RECT  2.16 227.745 246.24 228.015 ;
     RECT  2.16 228.285 246.24 228.555 ;
     RECT  2.16 228.825 246.24 229.095 ;
     RECT  2.16 229.365 246.24 229.635 ;
     RECT  2.16 229.905 246.24 230.175 ;
     RECT  2.16 230.445 246.24 230.715 ;
     RECT  2.16 230.985 246.24 231.255 ;
     RECT  2.16 231.525 246.24 231.795 ;
     RECT  2.16 232.065 246.24 232.335 ;
     RECT  2.16 232.605 246.24 232.875 ;
     RECT  2.16 233.145 246.24 233.415 ;
     RECT  2.16 233.685 246.24 233.955 ;
     RECT  2.16 234.225 246.24 234.495 ;
     RECT  2.16 234.765 246.24 235.035 ;
     RECT  2.16 235.305 246.24 235.575 ;
     RECT  2.16 235.845 246.24 236.115 ;
     RECT  2.16 236.385 246.24 236.655 ;
     RECT  2.16 236.925 246.24 237.195 ;
     RECT  2.16 237.465 246.24 237.735 ;
     RECT  2.16 238.005 246.24 238.275 ;
     RECT  2.16 238.545 246.24 238.815 ;
     RECT  2.16 239.085 246.24 239.355 ;
     RECT  2.16 239.625 246.24 239.895 ;
     RECT  2.16 240.165 246.24 240.435 ;
     RECT  2.16 240.705 246.24 240.975 ;
     RECT  2.16 241.245 246.24 241.515 ;
     RECT  2.16 241.785 246.24 242.055 ;
     RECT  2.16 242.325 246.24 242.595 ;
     RECT  2.16 242.865 246.24 243.135 ;
     RECT  2.16 243.405 246.24 243.675 ;
     RECT  2.16 243.945 246.24 244.215 ;
     RECT  2.16 244.485 246.24 244.755 ;
     RECT  2.16 245.025 246.24 245.295 ;
     RECT  2.16 245.565 246.24 245.835 ;
     RECT  2.16 246.105 246.24 246.375 ;
     RECT  2.16 246.645 246.24 246.915 ;
     RECT  2.16 247.185 246.24 247.455 ;
     RECT  2.16 247.725 246.24 247.995 ;
     RECT  2.16 248.265 246.24 248.535 ;
     RECT  2.16 248.805 246.24 249.075 ;
     RECT  2.16 249.345 246.24 249.615 ;
     RECT  2.16 249.885 246.24 250.155 ;
     RECT  2.16 250.425 246.24 250.695 ;
     RECT  2.16 250.965 246.24 251.235 ;
     RECT  2.16 251.505 246.24 251.775 ;
     RECT  2.16 252.045 246.24 252.315 ;
     RECT  2.16 252.585 246.24 252.855 ;
     RECT  2.16 253.125 246.24 253.395 ;
     RECT  2.16 253.665 246.24 253.935 ;
     RECT  2.16 254.205 246.24 254.475 ;
     RECT  2.16 254.745 246.24 255.015 ;
     RECT  2.16 255.285 246.24 255.555 ;
     RECT  2.16 255.825 246.24 256.095 ;
     RECT  2.16 256.365 246.24 256.635 ;
     RECT  2.16 256.905 246.24 257.175 ;
     RECT  2.16 257.445 246.24 257.715 ;
     RECT  2.16 257.985 246.24 258.255 ;
     RECT  2.16 258.525 246.24 258.795 ;
     RECT  2.16 259.065 246.24 259.335 ;
     RECT  2.16 259.605 246.24 259.875 ;
     RECT  2.16 260.145 246.24 260.415 ;
     RECT  2.16 260.685 246.24 260.955 ;
     RECT  2.16 261.225 246.24 261.495 ;
     RECT  2.16 261.765 246.24 262.035 ;
     RECT  2.16 262.305 246.24 262.575 ;
     RECT  2.16 262.845 246.24 263.115 ;
     RECT  2.16 263.385 246.24 263.655 ;
     RECT  2.16 263.925 246.24 264.195 ;
     RECT  2.16 264.465 246.24 264.735 ;
     RECT  2.16 265.005 246.24 265.275 ;
     RECT  2.16 265.545 246.24 265.815 ;
     RECT  2.16 266.085 246.24 266.355 ;
     RECT  2.16 266.625 246.24 266.895 ;
     RECT  2.16 267.165 246.24 267.435 ;
     RECT  2.16 267.705 246.24 267.975 ;
     RECT  2.16 268.245 246.24 268.515 ;
     RECT  2.16 268.785 246.24 269.055 ;
     RECT  2.16 269.325 246.24 269.595 ;
     RECT  2.16 269.865 246.24 270.135 ;
     RECT  2.16 270.405 246.24 270.675 ;
     RECT  2.16 270.945 246.24 271.215 ;
     RECT  2.16 271.485 246.24 271.755 ;
     RECT  2.16 272.025 246.24 272.295 ;
     RECT  2.16 272.565 246.24 272.835 ;
     RECT  2.16 273.105 246.24 273.375 ;
     RECT  2.16 273.645 246.24 273.915 ;
     RECT  2.16 274.185 246.24 274.455 ;
     RECT  2.16 274.725 246.24 274.995 ;
     RECT  2.16 275.265 246.24 275.535 ;
     RECT  2.16 275.805 246.24 276.075 ;
     RECT  2.16 276.345 246.24 276.615 ;
     RECT  2.16 276.885 246.24 277.155 ;
     RECT  2.16 277.425 246.24 277.695 ;
     RECT  2.16 277.965 246.24 278.235 ;
     RECT  2.16 278.505 246.24 278.775 ;
     RECT  2.16 279.045 246.24 279.315 ;
     RECT  2.16 279.585 246.24 279.855 ;
     RECT  2.16 280.125 246.24 280.395 ;
     RECT  2.16 280.665 246.24 280.935 ;
     RECT  2.16 281.205 246.24 281.475 ;
     RECT  2.16 281.745 246.24 282.015 ;
     RECT  2.16 282.285 246.24 282.555 ;
     RECT  2.16 282.825 246.24 283.095 ;
     RECT  2.16 283.365 246.24 283.635 ;
     RECT  2.16 283.905 246.24 284.175 ;
     RECT  2.16 284.445 246.24 284.715 ;
     RECT  2.16 284.985 246.24 285.255 ;
     RECT  2.16 285.525 246.24 285.795 ;
     RECT  2.16 286.065 246.24 286.335 ;
     RECT  2.16 286.605 246.24 286.875 ;
     RECT  2.16 287.145 246.24 287.415 ;
     RECT  2.16 287.685 246.24 287.955 ;
     RECT  2.16 288.225 246.24 288.495 ;
     RECT  2.16 288.765 246.24 289.035 ;
     RECT  2.16 289.305 246.24 289.575 ;
     RECT  2.16 289.845 246.24 290.115 ;
     RECT  2.16 290.385 246.24 290.655 ;
     RECT  2.16 290.925 246.24 291.195 ;
     RECT  2.16 291.465 246.24 291.735 ;
     RECT  2.16 292.005 246.24 292.275 ;
     RECT  2.16 292.545 246.24 292.815 ;
     RECT  2.16 293.085 246.24 293.355 ;
     RECT  2.16 293.625 246.24 293.895 ;
     RECT  2.16 294.165 246.24 294.435 ;
     RECT  2.16 294.705 246.24 294.975 ;
     RECT  2.16 295.245 246.24 295.515 ;
     RECT  2.16 295.785 246.24 296.055 ;
     RECT  2.16 296.325 246.24 296.595 ;
     RECT  2.16 296.865 246.24 297.135 ;
     RECT  2.16 297.405 246.24 297.675 ;
     RECT  2.16 297.945 246.24 298.215 ;
     RECT  2.16 298.485 246.24 298.755 ;
     RECT  2.16 299.025 246.24 299.295 ;
     RECT  2.16 299.565 246.24 299.835 ;
     RECT  2.16 300.105 246.24 300.375 ;
     RECT  2.16 300.645 246.24 300.915 ;
     RECT  2.16 301.185 246.24 301.455 ;
     RECT  2.16 301.725 246.24 301.995 ;
     RECT  2.16 302.265 246.24 302.535 ;
     RECT  2.16 302.805 246.24 303.075 ;
     RECT  2.16 303.345 246.24 303.615 ;
     RECT  2.16 303.885 246.24 304.155 ;
     RECT  2.16 304.425 246.24 304.695 ;
     RECT  2.16 304.965 246.24 305.235 ;
     RECT  2.16 305.505 246.24 305.775 ;
     RECT  2.16 306.045 246.24 306.315 ;
     RECT  2.16 306.585 246.24 306.855 ;
     RECT  2.16 307.125 246.24 307.395 ;
     RECT  2.16 307.665 246.24 307.935 ;
     RECT  2.16 308.205 246.24 308.475 ;
     RECT  2.16 308.745 246.24 309.015 ;
     RECT  2.16 309.285 246.24 309.555 ;
     RECT  2.16 309.825 246.24 310.095 ;
     RECT  2.16 310.365 246.24 310.635 ;
     RECT  2.16 310.905 246.24 311.175 ;
     RECT  2.16 311.445 246.24 311.715 ;
     RECT  2.16 311.985 246.24 312.255 ;
     RECT  2.16 312.525 246.24 312.795 ;
     RECT  2.16 313.065 246.24 313.335 ;
     RECT  2.16 313.605 246.24 313.875 ;
     RECT  2.16 314.145 246.24 314.415 ;
     RECT  2.16 314.685 246.24 314.955 ;
     RECT  2.16 315.225 246.24 315.495 ;
     RECT  2.16 315.765 246.24 316.035 ;
     RECT  2.16 316.305 246.24 316.575 ;
     RECT  2.16 316.845 246.24 317.115 ;
     RECT  2.16 317.385 246.24 317.655 ;
     RECT  2.16 317.925 246.24 318.195 ;
     RECT  2.16 318.465 246.24 318.735 ;
     RECT  2.16 319.005 246.24 319.275 ;
     RECT  2.16 319.545 246.24 319.815 ;
     RECT  2.16 320.085 246.24 320.355 ;
     RECT  2.16 320.625 246.24 320.895 ;
     RECT  2.16 321.165 246.24 321.435 ;
     RECT  2.16 321.705 246.24 321.975 ;
     RECT  2.16 322.245 246.24 322.515 ;
     RECT  2.16 322.785 246.24 323.055 ;
     RECT  2.16 323.325 246.24 323.595 ;
     RECT  2.16 323.865 246.24 324.135 ;
     RECT  2.16 324.405 246.24 324.675 ;
     RECT  2.16 324.945 246.24 325.215 ;
     RECT  2.16 325.485 246.24 325.755 ;
     RECT  2.16 326.025 246.24 326.295 ;
     RECT  2.16 326.565 246.24 326.835 ;
     RECT  2.16 327.105 246.24 327.375 ;
     RECT  2.16 327.645 246.24 327.915 ;
     RECT  2.16 328.185 246.24 328.455 ;
     RECT  2.16 328.725 246.24 328.995 ;
     RECT  2.16 329.265 246.24 329.535 ;
     RECT  2.16 329.805 246.24 330.075 ;
     RECT  2.16 330.345 246.24 330.615 ;
     RECT  2.16 330.885 246.24 331.155 ;
     RECT  2.16 331.425 246.24 331.695 ;
     RECT  2.16 331.965 246.24 332.235 ;
     RECT  2.16 332.505 246.24 332.775 ;
     RECT  2.16 333.045 246.24 333.315 ;
     RECT  2.16 333.585 246.24 333.855 ;
     RECT  2.16 334.125 246.24 334.395 ;
     RECT  2.16 334.665 246.24 334.935 ;
     RECT  2.16 335.205 246.24 335.475 ;
     RECT  2.16 335.745 246.24 336.015 ;
     RECT  2.16 336.285 246.24 336.555 ;
     RECT  2.16 336.825 246.24 337.095 ;
     RECT  2.16 337.365 246.24 337.635 ;
     RECT  2.16 337.905 246.24 338.175 ;
     RECT  2.16 338.445 246.24 338.715 ;
     RECT  2.16 338.985 246.24 339.255 ;
     RECT  2.16 339.525 246.24 339.795 ;
     RECT  2.16 340.065 246.24 340.335 ;
     RECT  2.16 340.605 246.24 340.875 ;
     RECT  2.16 341.145 246.24 341.415 ;
     RECT  2.16 341.685 246.24 341.955 ;
     RECT  2.16 342.225 246.24 342.495 ;
     RECT  2.16 342.765 246.24 343.035 ;
     RECT  2.16 343.305 246.24 343.575 ;
     RECT  2.16 343.845 246.24 344.115 ;
     RECT  2.16 344.385 246.24 344.655 ;
     RECT  2.16 344.925 246.24 345.195 ;
     RECT  2.16 345.465 246.24 345.735 ;
     RECT  2.16 346.005 246.24 346.275 ;
     RECT  2.16 346.545 246.24 346.815 ;
     RECT  2.16 347.085 246.24 347.355 ;
     RECT  2.16 347.625 246.24 347.895 ;
     RECT  2.16 348.165 246.24 348.435 ;
     RECT  2.16 348.705 246.24 348.975 ;
     RECT  2.16 349.245 246.24 349.515 ;
     RECT  2.16 349.785 246.24 350.055 ;
     RECT  2.16 350.325 246.24 350.595 ;
     RECT  2.16 350.865 246.24 351.135 ;
     RECT  2.16 351.405 246.24 351.675 ;
     RECT  2.16 351.945 246.24 352.215 ;
     RECT  2.16 352.485 246.24 352.755 ;
     RECT  2.16 353.025 246.24 353.295 ;
     RECT  2.16 353.565 246.24 353.835 ;
     RECT  2.16 354.105 246.24 354.375 ;
     RECT  2.16 354.645 246.24 354.915 ;
     RECT  2.16 355.185 246.24 355.455 ;
     RECT  2.16 355.725 246.24 355.995 ;
     RECT  2.16 356.265 246.24 356.535 ;
     RECT  2.16 356.805 246.24 357.075 ;
     RECT  2.16 357.345 246.24 357.615 ;
     RECT  2.16 357.885 246.24 358.155 ;
     RECT  2.16 358.425 246.24 358.695 ;
     RECT  2.16 358.965 246.24 359.235 ;
     RECT  2.16 359.505 246.24 359.775 ;
     RECT  2.16 360.045 246.24 360.315 ;
     RECT  2.16 360.585 246.24 360.855 ;
     RECT  2.16 361.125 246.24 361.395 ;
     RECT  2.16 361.665 246.24 361.935 ;
     RECT  2.16 362.205 246.24 362.475 ;
     RECT  2.16 362.745 246.24 363.015 ;
     RECT  2.16 363.285 246.24 363.555 ;
     RECT  2.16 363.825 246.24 364.095 ;
     RECT  2.16 364.365 246.24 364.635 ;
     RECT  2.16 364.905 246.24 365.175 ;
     RECT  2.16 365.445 246.24 365.715 ;
     RECT  2.16 365.985 246.24 366.255 ;
     RECT  2.16 366.525 246.24 366.795 ;
     RECT  2.16 367.065 246.24 367.335 ;
     RECT  2.16 367.605 246.24 367.875 ;
     RECT  2.16 368.145 246.24 368.415 ;
     RECT  2.16 368.685 246.24 368.955 ;
     RECT  2.16 369.225 246.24 369.36 ;
    LAYER RVTP ;
     RECT  2.16 2.295 246.24 2.565 ;
     RECT  2.16 2.835 246.24 3.105 ;
     RECT  2.16 3.375 246.24 3.645 ;
     RECT  2.16 3.915 246.24 4.185 ;
     RECT  2.16 4.455 246.24 4.725 ;
     RECT  2.16 4.995 246.24 5.265 ;
     RECT  2.16 5.535 246.24 5.805 ;
     RECT  2.16 6.075 246.24 6.345 ;
     RECT  2.16 6.615 246.24 6.885 ;
     RECT  2.16 7.155 246.24 7.425 ;
     RECT  2.16 7.695 246.24 7.965 ;
     RECT  2.16 8.235 246.24 8.505 ;
     RECT  2.16 8.775 246.24 9.045 ;
     RECT  2.16 9.315 246.24 9.585 ;
     RECT  2.16 9.855 246.24 10.125 ;
     RECT  2.16 10.395 246.24 10.665 ;
     RECT  2.16 10.935 246.24 11.205 ;
     RECT  2.16 11.475 246.24 11.745 ;
     RECT  2.16 12.015 246.24 12.285 ;
     RECT  2.16 12.555 246.24 12.825 ;
     RECT  2.16 13.095 246.24 13.365 ;
     RECT  2.16 13.635 246.24 13.905 ;
     RECT  2.16 14.175 246.24 14.445 ;
     RECT  2.16 14.715 246.24 14.985 ;
     RECT  2.16 15.255 246.24 15.525 ;
     RECT  2.16 15.795 246.24 16.065 ;
     RECT  2.16 16.335 246.24 16.605 ;
     RECT  2.16 16.875 246.24 17.145 ;
     RECT  2.16 17.415 246.24 17.685 ;
     RECT  2.16 17.955 246.24 18.225 ;
     RECT  2.16 18.495 246.24 18.765 ;
     RECT  2.16 19.035 246.24 19.305 ;
     RECT  2.16 19.575 246.24 19.845 ;
     RECT  2.16 20.115 246.24 20.385 ;
     RECT  2.16 20.655 246.24 20.925 ;
     RECT  2.16 21.195 246.24 21.465 ;
     RECT  2.16 21.735 246.24 22.005 ;
     RECT  2.16 22.275 246.24 22.545 ;
     RECT  2.16 22.815 246.24 23.085 ;
     RECT  2.16 23.355 246.24 23.625 ;
     RECT  2.16 23.895 246.24 24.165 ;
     RECT  2.16 24.435 246.24 24.705 ;
     RECT  2.16 24.975 246.24 25.245 ;
     RECT  2.16 25.515 246.24 25.785 ;
     RECT  2.16 26.055 246.24 26.325 ;
     RECT  2.16 26.595 246.24 26.865 ;
     RECT  2.16 27.135 246.24 27.405 ;
     RECT  2.16 27.675 246.24 27.945 ;
     RECT  2.16 28.215 246.24 28.485 ;
     RECT  2.16 28.755 246.24 29.025 ;
     RECT  2.16 29.295 246.24 29.565 ;
     RECT  2.16 29.835 246.24 30.105 ;
     RECT  2.16 30.375 246.24 30.645 ;
     RECT  2.16 30.915 246.24 31.185 ;
     RECT  2.16 31.455 246.24 31.725 ;
     RECT  2.16 31.995 246.24 32.265 ;
     RECT  2.16 32.535 246.24 32.805 ;
     RECT  2.16 33.075 246.24 33.345 ;
     RECT  2.16 33.615 246.24 33.885 ;
     RECT  2.16 34.155 246.24 34.425 ;
     RECT  2.16 34.695 246.24 34.965 ;
     RECT  2.16 35.235 246.24 35.505 ;
     RECT  2.16 35.775 246.24 36.045 ;
     RECT  2.16 36.315 246.24 36.585 ;
     RECT  2.16 36.855 246.24 37.125 ;
     RECT  2.16 37.395 246.24 37.665 ;
     RECT  2.16 37.935 246.24 38.205 ;
     RECT  2.16 38.475 246.24 38.745 ;
     RECT  2.16 39.015 246.24 39.285 ;
     RECT  2.16 39.555 246.24 39.825 ;
     RECT  2.16 40.095 246.24 40.365 ;
     RECT  2.16 40.635 246.24 40.905 ;
     RECT  2.16 41.175 246.24 41.445 ;
     RECT  2.16 41.715 246.24 41.985 ;
     RECT  2.16 42.255 246.24 42.525 ;
     RECT  2.16 42.795 246.24 43.065 ;
     RECT  2.16 43.335 246.24 43.605 ;
     RECT  2.16 43.875 246.24 44.145 ;
     RECT  2.16 44.415 246.24 44.685 ;
     RECT  2.16 44.955 246.24 45.225 ;
     RECT  2.16 45.495 246.24 45.765 ;
     RECT  2.16 46.035 246.24 46.305 ;
     RECT  2.16 46.575 246.24 46.845 ;
     RECT  2.16 47.115 246.24 47.385 ;
     RECT  2.16 47.655 246.24 47.925 ;
     RECT  2.16 48.195 246.24 48.465 ;
     RECT  2.16 48.735 246.24 49.005 ;
     RECT  2.16 49.275 246.24 49.545 ;
     RECT  2.16 49.815 246.24 50.085 ;
     RECT  2.16 50.355 246.24 50.625 ;
     RECT  2.16 50.895 246.24 51.165 ;
     RECT  2.16 51.435 246.24 51.705 ;
     RECT  2.16 51.975 246.24 52.245 ;
     RECT  2.16 52.515 246.24 52.785 ;
     RECT  2.16 53.055 246.24 53.325 ;
     RECT  2.16 53.595 246.24 53.865 ;
     RECT  2.16 54.135 246.24 54.405 ;
     RECT  2.16 54.675 246.24 54.945 ;
     RECT  2.16 55.215 246.24 55.485 ;
     RECT  2.16 55.755 246.24 56.025 ;
     RECT  2.16 56.295 246.24 56.565 ;
     RECT  2.16 56.835 246.24 57.105 ;
     RECT  2.16 57.375 246.24 57.645 ;
     RECT  2.16 57.915 246.24 58.185 ;
     RECT  2.16 58.455 246.24 58.725 ;
     RECT  2.16 58.995 246.24 59.265 ;
     RECT  2.16 59.535 246.24 59.805 ;
     RECT  2.16 60.075 246.24 60.345 ;
     RECT  2.16 60.615 246.24 60.885 ;
     RECT  2.16 61.155 246.24 61.425 ;
     RECT  2.16 61.695 246.24 61.965 ;
     RECT  2.16 62.235 246.24 62.505 ;
     RECT  2.16 62.775 246.24 63.045 ;
     RECT  2.16 63.315 246.24 63.585 ;
     RECT  2.16 63.855 246.24 64.125 ;
     RECT  2.16 64.395 246.24 64.665 ;
     RECT  2.16 64.935 246.24 65.205 ;
     RECT  2.16 65.475 246.24 65.745 ;
     RECT  2.16 66.015 246.24 66.285 ;
     RECT  2.16 66.555 246.24 66.825 ;
     RECT  2.16 67.095 246.24 67.365 ;
     RECT  2.16 67.635 246.24 67.905 ;
     RECT  2.16 68.175 246.24 68.445 ;
     RECT  2.16 68.715 246.24 68.985 ;
     RECT  2.16 69.255 246.24 69.525 ;
     RECT  2.16 69.795 246.24 70.065 ;
     RECT  2.16 70.335 246.24 70.605 ;
     RECT  2.16 70.875 246.24 71.145 ;
     RECT  2.16 71.415 246.24 71.685 ;
     RECT  2.16 71.955 246.24 72.225 ;
     RECT  2.16 72.495 246.24 72.765 ;
     RECT  2.16 73.035 246.24 73.305 ;
     RECT  2.16 73.575 246.24 73.845 ;
     RECT  2.16 74.115 246.24 74.385 ;
     RECT  2.16 74.655 246.24 74.925 ;
     RECT  2.16 75.195 246.24 75.465 ;
     RECT  2.16 75.735 246.24 76.005 ;
     RECT  2.16 76.275 246.24 76.545 ;
     RECT  2.16 76.815 246.24 77.085 ;
     RECT  2.16 77.355 246.24 77.625 ;
     RECT  2.16 77.895 246.24 78.165 ;
     RECT  2.16 78.435 246.24 78.705 ;
     RECT  2.16 78.975 246.24 79.245 ;
     RECT  2.16 79.515 246.24 79.785 ;
     RECT  2.16 80.055 246.24 80.325 ;
     RECT  2.16 80.595 246.24 80.865 ;
     RECT  2.16 81.135 246.24 81.405 ;
     RECT  2.16 81.675 246.24 81.945 ;
     RECT  2.16 82.215 246.24 82.485 ;
     RECT  2.16 82.755 246.24 83.025 ;
     RECT  2.16 83.295 246.24 83.565 ;
     RECT  2.16 83.835 246.24 84.105 ;
     RECT  2.16 84.375 246.24 84.645 ;
     RECT  2.16 84.915 246.24 85.185 ;
     RECT  2.16 85.455 246.24 85.725 ;
     RECT  2.16 85.995 246.24 86.265 ;
     RECT  2.16 86.535 246.24 86.805 ;
     RECT  2.16 87.075 246.24 87.345 ;
     RECT  2.16 87.615 246.24 87.885 ;
     RECT  2.16 88.155 246.24 88.425 ;
     RECT  2.16 88.695 246.24 88.965 ;
     RECT  2.16 89.235 246.24 89.505 ;
     RECT  2.16 89.775 246.24 90.045 ;
     RECT  2.16 90.315 246.24 90.585 ;
     RECT  2.16 90.855 246.24 91.125 ;
     RECT  2.16 91.395 246.24 91.665 ;
     RECT  2.16 91.935 246.24 92.205 ;
     RECT  2.16 92.475 246.24 92.745 ;
     RECT  2.16 93.015 246.24 93.285 ;
     RECT  2.16 93.555 246.24 93.825 ;
     RECT  2.16 94.095 246.24 94.365 ;
     RECT  2.16 94.635 246.24 94.905 ;
     RECT  2.16 95.175 246.24 95.445 ;
     RECT  2.16 95.715 246.24 95.985 ;
     RECT  2.16 96.255 246.24 96.525 ;
     RECT  2.16 96.795 246.24 97.065 ;
     RECT  2.16 97.335 246.24 97.605 ;
     RECT  2.16 97.875 246.24 98.145 ;
     RECT  2.16 98.415 246.24 98.685 ;
     RECT  2.16 98.955 246.24 99.225 ;
     RECT  2.16 99.495 246.24 99.765 ;
     RECT  2.16 100.035 246.24 100.305 ;
     RECT  2.16 100.575 246.24 100.845 ;
     RECT  2.16 101.115 246.24 101.385 ;
     RECT  2.16 101.655 246.24 101.925 ;
     RECT  2.16 102.195 246.24 102.465 ;
     RECT  2.16 102.735 246.24 103.005 ;
     RECT  2.16 103.275 246.24 103.545 ;
     RECT  2.16 103.815 246.24 104.085 ;
     RECT  2.16 104.355 246.24 104.625 ;
     RECT  2.16 104.895 246.24 105.165 ;
     RECT  2.16 105.435 246.24 105.705 ;
     RECT  2.16 105.975 246.24 106.245 ;
     RECT  2.16 106.515 246.24 106.785 ;
     RECT  2.16 107.055 246.24 107.325 ;
     RECT  2.16 107.595 246.24 107.865 ;
     RECT  2.16 108.135 246.24 108.405 ;
     RECT  2.16 108.675 246.24 108.945 ;
     RECT  2.16 109.215 246.24 109.485 ;
     RECT  2.16 109.755 246.24 110.025 ;
     RECT  2.16 110.295 246.24 110.565 ;
     RECT  2.16 110.835 246.24 111.105 ;
     RECT  2.16 111.375 246.24 111.645 ;
     RECT  2.16 111.915 246.24 112.185 ;
     RECT  2.16 112.455 246.24 112.725 ;
     RECT  2.16 112.995 246.24 113.265 ;
     RECT  2.16 113.535 246.24 113.805 ;
     RECT  2.16 114.075 246.24 114.345 ;
     RECT  2.16 114.615 246.24 114.885 ;
     RECT  2.16 115.155 246.24 115.425 ;
     RECT  2.16 115.695 246.24 115.965 ;
     RECT  2.16 116.235 246.24 116.505 ;
     RECT  2.16 116.775 246.24 117.045 ;
     RECT  2.16 117.315 246.24 117.585 ;
     RECT  2.16 117.855 246.24 118.125 ;
     RECT  2.16 118.395 246.24 118.665 ;
     RECT  2.16 118.935 246.24 119.205 ;
     RECT  2.16 119.475 246.24 119.745 ;
     RECT  2.16 120.015 246.24 120.285 ;
     RECT  2.16 120.555 246.24 120.825 ;
     RECT  2.16 121.095 246.24 121.365 ;
     RECT  2.16 121.635 246.24 121.905 ;
     RECT  2.16 122.175 246.24 122.445 ;
     RECT  2.16 122.715 246.24 122.985 ;
     RECT  2.16 123.255 246.24 123.525 ;
     RECT  2.16 123.795 246.24 124.065 ;
     RECT  2.16 124.335 246.24 124.605 ;
     RECT  2.16 124.875 246.24 125.145 ;
     RECT  2.16 125.415 246.24 125.685 ;
     RECT  2.16 125.955 246.24 126.225 ;
     RECT  2.16 126.495 246.24 126.765 ;
     RECT  2.16 127.035 246.24 127.305 ;
     RECT  2.16 127.575 246.24 127.845 ;
     RECT  2.16 128.115 246.24 128.385 ;
     RECT  2.16 128.655 246.24 128.925 ;
     RECT  2.16 129.195 246.24 129.465 ;
     RECT  2.16 129.735 246.24 130.005 ;
     RECT  2.16 130.275 246.24 130.545 ;
     RECT  2.16 130.815 246.24 131.085 ;
     RECT  2.16 131.355 246.24 131.625 ;
     RECT  2.16 131.895 246.24 132.165 ;
     RECT  2.16 132.435 246.24 132.705 ;
     RECT  2.16 132.975 246.24 133.245 ;
     RECT  2.16 133.515 246.24 133.785 ;
     RECT  2.16 134.055 246.24 134.325 ;
     RECT  2.16 134.595 246.24 134.865 ;
     RECT  2.16 135.135 246.24 135.405 ;
     RECT  2.16 135.675 246.24 135.945 ;
     RECT  2.16 136.215 246.24 136.485 ;
     RECT  2.16 136.755 246.24 137.025 ;
     RECT  2.16 137.295 246.24 137.565 ;
     RECT  2.16 137.835 246.24 138.105 ;
     RECT  2.16 138.375 246.24 138.645 ;
     RECT  2.16 138.915 246.24 139.185 ;
     RECT  2.16 139.455 246.24 139.725 ;
     RECT  2.16 139.995 246.24 140.265 ;
     RECT  2.16 140.535 246.24 140.805 ;
     RECT  2.16 141.075 246.24 141.345 ;
     RECT  2.16 141.615 246.24 141.885 ;
     RECT  2.16 142.155 246.24 142.425 ;
     RECT  2.16 142.695 246.24 142.965 ;
     RECT  2.16 143.235 246.24 143.505 ;
     RECT  2.16 143.775 246.24 144.045 ;
     RECT  2.16 144.315 246.24 144.585 ;
     RECT  2.16 144.855 246.24 145.125 ;
     RECT  2.16 145.395 246.24 145.665 ;
     RECT  2.16 145.935 246.24 146.205 ;
     RECT  2.16 146.475 246.24 146.745 ;
     RECT  2.16 147.015 246.24 147.285 ;
     RECT  2.16 147.555 246.24 147.825 ;
     RECT  2.16 148.095 246.24 148.365 ;
     RECT  2.16 148.635 246.24 148.905 ;
     RECT  2.16 149.175 246.24 149.445 ;
     RECT  2.16 149.715 246.24 149.985 ;
     RECT  2.16 150.255 246.24 150.525 ;
     RECT  2.16 150.795 246.24 151.065 ;
     RECT  2.16 151.335 246.24 151.605 ;
     RECT  2.16 151.875 246.24 152.145 ;
     RECT  2.16 152.415 246.24 152.685 ;
     RECT  2.16 152.955 246.24 153.225 ;
     RECT  2.16 153.495 246.24 153.765 ;
     RECT  2.16 154.035 246.24 154.305 ;
     RECT  2.16 154.575 246.24 154.845 ;
     RECT  2.16 155.115 246.24 155.385 ;
     RECT  2.16 155.655 246.24 155.925 ;
     RECT  2.16 156.195 246.24 156.465 ;
     RECT  2.16 156.735 246.24 157.005 ;
     RECT  2.16 157.275 246.24 157.545 ;
     RECT  2.16 157.815 246.24 158.085 ;
     RECT  2.16 158.355 246.24 158.625 ;
     RECT  2.16 158.895 246.24 159.165 ;
     RECT  2.16 159.435 246.24 159.705 ;
     RECT  2.16 159.975 246.24 160.245 ;
     RECT  2.16 160.515 246.24 160.785 ;
     RECT  2.16 161.055 246.24 161.325 ;
     RECT  2.16 161.595 246.24 161.865 ;
     RECT  2.16 162.135 246.24 162.405 ;
     RECT  2.16 162.675 246.24 162.945 ;
     RECT  2.16 163.215 246.24 163.485 ;
     RECT  2.16 163.755 246.24 164.025 ;
     RECT  2.16 164.295 246.24 164.565 ;
     RECT  2.16 164.835 246.24 165.105 ;
     RECT  2.16 165.375 246.24 165.645 ;
     RECT  2.16 165.915 246.24 166.185 ;
     RECT  2.16 166.455 246.24 166.725 ;
     RECT  2.16 166.995 246.24 167.265 ;
     RECT  2.16 167.535 246.24 167.805 ;
     RECT  2.16 168.075 246.24 168.345 ;
     RECT  2.16 168.615 246.24 168.885 ;
     RECT  2.16 169.155 246.24 169.425 ;
     RECT  2.16 169.695 246.24 169.965 ;
     RECT  2.16 170.235 246.24 170.505 ;
     RECT  2.16 170.775 246.24 171.045 ;
     RECT  2.16 171.315 246.24 171.585 ;
     RECT  2.16 171.855 246.24 172.125 ;
     RECT  2.16 172.395 246.24 172.665 ;
     RECT  2.16 172.935 246.24 173.205 ;
     RECT  2.16 173.475 246.24 173.745 ;
     RECT  2.16 174.015 246.24 174.285 ;
     RECT  2.16 174.555 246.24 174.825 ;
     RECT  2.16 175.095 246.24 175.365 ;
     RECT  2.16 175.635 246.24 175.905 ;
     RECT  2.16 176.175 246.24 176.445 ;
     RECT  2.16 176.715 246.24 176.985 ;
     RECT  2.16 177.255 246.24 177.525 ;
     RECT  2.16 177.795 246.24 178.065 ;
     RECT  2.16 178.335 246.24 178.605 ;
     RECT  2.16 178.875 246.24 179.145 ;
     RECT  2.16 179.415 246.24 179.685 ;
     RECT  2.16 179.955 246.24 180.225 ;
     RECT  2.16 180.495 246.24 180.765 ;
     RECT  2.16 181.035 246.24 181.305 ;
     RECT  2.16 181.575 246.24 181.845 ;
     RECT  2.16 182.115 246.24 182.385 ;
     RECT  2.16 182.655 246.24 182.925 ;
     RECT  2.16 183.195 246.24 183.465 ;
     RECT  2.16 183.735 246.24 184.005 ;
     RECT  2.16 184.275 246.24 184.545 ;
     RECT  2.16 184.815 246.24 185.085 ;
     RECT  2.16 185.355 246.24 185.625 ;
     RECT  2.16 185.895 246.24 186.165 ;
     RECT  2.16 186.435 246.24 186.705 ;
     RECT  2.16 186.975 246.24 187.245 ;
     RECT  2.16 187.515 246.24 187.785 ;
     RECT  2.16 188.055 246.24 188.325 ;
     RECT  2.16 188.595 246.24 188.865 ;
     RECT  2.16 189.135 246.24 189.405 ;
     RECT  2.16 189.675 246.24 189.945 ;
     RECT  2.16 190.215 246.24 190.485 ;
     RECT  2.16 190.755 246.24 191.025 ;
     RECT  2.16 191.295 246.24 191.565 ;
     RECT  2.16 191.835 246.24 192.105 ;
     RECT  2.16 192.375 246.24 192.645 ;
     RECT  2.16 192.915 246.24 193.185 ;
     RECT  2.16 193.455 246.24 193.725 ;
     RECT  2.16 193.995 246.24 194.265 ;
     RECT  2.16 194.535 246.24 194.805 ;
     RECT  2.16 195.075 246.24 195.345 ;
     RECT  2.16 195.615 246.24 195.885 ;
     RECT  2.16 196.155 246.24 196.425 ;
     RECT  2.16 196.695 246.24 196.965 ;
     RECT  2.16 197.235 246.24 197.505 ;
     RECT  2.16 197.775 246.24 198.045 ;
     RECT  2.16 198.315 246.24 198.585 ;
     RECT  2.16 198.855 246.24 199.125 ;
     RECT  2.16 199.395 246.24 199.665 ;
     RECT  2.16 199.935 246.24 200.205 ;
     RECT  2.16 200.475 246.24 200.745 ;
     RECT  2.16 201.015 246.24 201.285 ;
     RECT  2.16 201.555 246.24 201.825 ;
     RECT  2.16 202.095 246.24 202.365 ;
     RECT  2.16 202.635 246.24 202.905 ;
     RECT  2.16 203.175 246.24 203.445 ;
     RECT  2.16 203.715 246.24 203.985 ;
     RECT  2.16 204.255 246.24 204.525 ;
     RECT  2.16 204.795 246.24 205.065 ;
     RECT  2.16 205.335 246.24 205.605 ;
     RECT  2.16 205.875 246.24 206.145 ;
     RECT  2.16 206.415 246.24 206.685 ;
     RECT  2.16 206.955 246.24 207.225 ;
     RECT  2.16 207.495 246.24 207.765 ;
     RECT  2.16 208.035 246.24 208.305 ;
     RECT  2.16 208.575 246.24 208.845 ;
     RECT  2.16 209.115 246.24 209.385 ;
     RECT  2.16 209.655 246.24 209.925 ;
     RECT  2.16 210.195 246.24 210.465 ;
     RECT  2.16 210.735 246.24 211.005 ;
     RECT  2.16 211.275 246.24 211.545 ;
     RECT  2.16 211.815 246.24 212.085 ;
     RECT  2.16 212.355 246.24 212.625 ;
     RECT  2.16 212.895 246.24 213.165 ;
     RECT  2.16 213.435 246.24 213.705 ;
     RECT  2.16 213.975 246.24 214.245 ;
     RECT  2.16 214.515 246.24 214.785 ;
     RECT  2.16 215.055 246.24 215.325 ;
     RECT  2.16 215.595 246.24 215.865 ;
     RECT  2.16 216.135 246.24 216.405 ;
     RECT  2.16 216.675 246.24 216.945 ;
     RECT  2.16 217.215 246.24 217.485 ;
     RECT  2.16 217.755 246.24 218.025 ;
     RECT  2.16 218.295 246.24 218.565 ;
     RECT  2.16 218.835 246.24 219.105 ;
     RECT  2.16 219.375 246.24 219.645 ;
     RECT  2.16 219.915 246.24 220.185 ;
     RECT  2.16 220.455 246.24 220.725 ;
     RECT  2.16 220.995 246.24 221.265 ;
     RECT  2.16 221.535 246.24 221.805 ;
     RECT  2.16 222.075 246.24 222.345 ;
     RECT  2.16 222.615 246.24 222.885 ;
     RECT  2.16 223.155 246.24 223.425 ;
     RECT  2.16 223.695 246.24 223.965 ;
     RECT  2.16 224.235 246.24 224.505 ;
     RECT  2.16 224.775 246.24 225.045 ;
     RECT  2.16 225.315 246.24 225.585 ;
     RECT  2.16 225.855 246.24 226.125 ;
     RECT  2.16 226.395 246.24 226.665 ;
     RECT  2.16 226.935 246.24 227.205 ;
     RECT  2.16 227.475 246.24 227.745 ;
     RECT  2.16 228.015 246.24 228.285 ;
     RECT  2.16 228.555 246.24 228.825 ;
     RECT  2.16 229.095 246.24 229.365 ;
     RECT  2.16 229.635 246.24 229.905 ;
     RECT  2.16 230.175 246.24 230.445 ;
     RECT  2.16 230.715 246.24 230.985 ;
     RECT  2.16 231.255 246.24 231.525 ;
     RECT  2.16 231.795 246.24 232.065 ;
     RECT  2.16 232.335 246.24 232.605 ;
     RECT  2.16 232.875 246.24 233.145 ;
     RECT  2.16 233.415 246.24 233.685 ;
     RECT  2.16 233.955 246.24 234.225 ;
     RECT  2.16 234.495 246.24 234.765 ;
     RECT  2.16 235.035 246.24 235.305 ;
     RECT  2.16 235.575 246.24 235.845 ;
     RECT  2.16 236.115 246.24 236.385 ;
     RECT  2.16 236.655 246.24 236.925 ;
     RECT  2.16 237.195 246.24 237.465 ;
     RECT  2.16 237.735 246.24 238.005 ;
     RECT  2.16 238.275 246.24 238.545 ;
     RECT  2.16 238.815 246.24 239.085 ;
     RECT  2.16 239.355 246.24 239.625 ;
     RECT  2.16 239.895 246.24 240.165 ;
     RECT  2.16 240.435 246.24 240.705 ;
     RECT  2.16 240.975 246.24 241.245 ;
     RECT  2.16 241.515 246.24 241.785 ;
     RECT  2.16 242.055 246.24 242.325 ;
     RECT  2.16 242.595 246.24 242.865 ;
     RECT  2.16 243.135 246.24 243.405 ;
     RECT  2.16 243.675 246.24 243.945 ;
     RECT  2.16 244.215 246.24 244.485 ;
     RECT  2.16 244.755 246.24 245.025 ;
     RECT  2.16 245.295 246.24 245.565 ;
     RECT  2.16 245.835 246.24 246.105 ;
     RECT  2.16 246.375 246.24 246.645 ;
     RECT  2.16 246.915 246.24 247.185 ;
     RECT  2.16 247.455 246.24 247.725 ;
     RECT  2.16 247.995 246.24 248.265 ;
     RECT  2.16 248.535 246.24 248.805 ;
     RECT  2.16 249.075 246.24 249.345 ;
     RECT  2.16 249.615 246.24 249.885 ;
     RECT  2.16 250.155 246.24 250.425 ;
     RECT  2.16 250.695 246.24 250.965 ;
     RECT  2.16 251.235 246.24 251.505 ;
     RECT  2.16 251.775 246.24 252.045 ;
     RECT  2.16 252.315 246.24 252.585 ;
     RECT  2.16 252.855 246.24 253.125 ;
     RECT  2.16 253.395 246.24 253.665 ;
     RECT  2.16 253.935 246.24 254.205 ;
     RECT  2.16 254.475 246.24 254.745 ;
     RECT  2.16 255.015 246.24 255.285 ;
     RECT  2.16 255.555 246.24 255.825 ;
     RECT  2.16 256.095 246.24 256.365 ;
     RECT  2.16 256.635 246.24 256.905 ;
     RECT  2.16 257.175 246.24 257.445 ;
     RECT  2.16 257.715 246.24 257.985 ;
     RECT  2.16 258.255 246.24 258.525 ;
     RECT  2.16 258.795 246.24 259.065 ;
     RECT  2.16 259.335 246.24 259.605 ;
     RECT  2.16 259.875 246.24 260.145 ;
     RECT  2.16 260.415 246.24 260.685 ;
     RECT  2.16 260.955 246.24 261.225 ;
     RECT  2.16 261.495 246.24 261.765 ;
     RECT  2.16 262.035 246.24 262.305 ;
     RECT  2.16 262.575 246.24 262.845 ;
     RECT  2.16 263.115 246.24 263.385 ;
     RECT  2.16 263.655 246.24 263.925 ;
     RECT  2.16 264.195 246.24 264.465 ;
     RECT  2.16 264.735 246.24 265.005 ;
     RECT  2.16 265.275 246.24 265.545 ;
     RECT  2.16 265.815 246.24 266.085 ;
     RECT  2.16 266.355 246.24 266.625 ;
     RECT  2.16 266.895 246.24 267.165 ;
     RECT  2.16 267.435 246.24 267.705 ;
     RECT  2.16 267.975 246.24 268.245 ;
     RECT  2.16 268.515 246.24 268.785 ;
     RECT  2.16 269.055 246.24 269.325 ;
     RECT  2.16 269.595 246.24 269.865 ;
     RECT  2.16 270.135 246.24 270.405 ;
     RECT  2.16 270.675 246.24 270.945 ;
     RECT  2.16 271.215 246.24 271.485 ;
     RECT  2.16 271.755 246.24 272.025 ;
     RECT  2.16 272.295 246.24 272.565 ;
     RECT  2.16 272.835 246.24 273.105 ;
     RECT  2.16 273.375 246.24 273.645 ;
     RECT  2.16 273.915 246.24 274.185 ;
     RECT  2.16 274.455 246.24 274.725 ;
     RECT  2.16 274.995 246.24 275.265 ;
     RECT  2.16 275.535 246.24 275.805 ;
     RECT  2.16 276.075 246.24 276.345 ;
     RECT  2.16 276.615 246.24 276.885 ;
     RECT  2.16 277.155 246.24 277.425 ;
     RECT  2.16 277.695 246.24 277.965 ;
     RECT  2.16 278.235 246.24 278.505 ;
     RECT  2.16 278.775 246.24 279.045 ;
     RECT  2.16 279.315 246.24 279.585 ;
     RECT  2.16 279.855 246.24 280.125 ;
     RECT  2.16 280.395 246.24 280.665 ;
     RECT  2.16 280.935 246.24 281.205 ;
     RECT  2.16 281.475 246.24 281.745 ;
     RECT  2.16 282.015 246.24 282.285 ;
     RECT  2.16 282.555 246.24 282.825 ;
     RECT  2.16 283.095 246.24 283.365 ;
     RECT  2.16 283.635 246.24 283.905 ;
     RECT  2.16 284.175 246.24 284.445 ;
     RECT  2.16 284.715 246.24 284.985 ;
     RECT  2.16 285.255 246.24 285.525 ;
     RECT  2.16 285.795 246.24 286.065 ;
     RECT  2.16 286.335 246.24 286.605 ;
     RECT  2.16 286.875 246.24 287.145 ;
     RECT  2.16 287.415 246.24 287.685 ;
     RECT  2.16 287.955 246.24 288.225 ;
     RECT  2.16 288.495 246.24 288.765 ;
     RECT  2.16 289.035 246.24 289.305 ;
     RECT  2.16 289.575 246.24 289.845 ;
     RECT  2.16 290.115 246.24 290.385 ;
     RECT  2.16 290.655 246.24 290.925 ;
     RECT  2.16 291.195 246.24 291.465 ;
     RECT  2.16 291.735 246.24 292.005 ;
     RECT  2.16 292.275 246.24 292.545 ;
     RECT  2.16 292.815 246.24 293.085 ;
     RECT  2.16 293.355 246.24 293.625 ;
     RECT  2.16 293.895 246.24 294.165 ;
     RECT  2.16 294.435 246.24 294.705 ;
     RECT  2.16 294.975 246.24 295.245 ;
     RECT  2.16 295.515 246.24 295.785 ;
     RECT  2.16 296.055 246.24 296.325 ;
     RECT  2.16 296.595 246.24 296.865 ;
     RECT  2.16 297.135 246.24 297.405 ;
     RECT  2.16 297.675 246.24 297.945 ;
     RECT  2.16 298.215 246.24 298.485 ;
     RECT  2.16 298.755 246.24 299.025 ;
     RECT  2.16 299.295 246.24 299.565 ;
     RECT  2.16 299.835 246.24 300.105 ;
     RECT  2.16 300.375 246.24 300.645 ;
     RECT  2.16 300.915 246.24 301.185 ;
     RECT  2.16 301.455 246.24 301.725 ;
     RECT  2.16 301.995 246.24 302.265 ;
     RECT  2.16 302.535 246.24 302.805 ;
     RECT  2.16 303.075 246.24 303.345 ;
     RECT  2.16 303.615 246.24 303.885 ;
     RECT  2.16 304.155 246.24 304.425 ;
     RECT  2.16 304.695 246.24 304.965 ;
     RECT  2.16 305.235 246.24 305.505 ;
     RECT  2.16 305.775 246.24 306.045 ;
     RECT  2.16 306.315 246.24 306.585 ;
     RECT  2.16 306.855 246.24 307.125 ;
     RECT  2.16 307.395 246.24 307.665 ;
     RECT  2.16 307.935 246.24 308.205 ;
     RECT  2.16 308.475 246.24 308.745 ;
     RECT  2.16 309.015 246.24 309.285 ;
     RECT  2.16 309.555 246.24 309.825 ;
     RECT  2.16 310.095 246.24 310.365 ;
     RECT  2.16 310.635 246.24 310.905 ;
     RECT  2.16 311.175 246.24 311.445 ;
     RECT  2.16 311.715 246.24 311.985 ;
     RECT  2.16 312.255 246.24 312.525 ;
     RECT  2.16 312.795 246.24 313.065 ;
     RECT  2.16 313.335 246.24 313.605 ;
     RECT  2.16 313.875 246.24 314.145 ;
     RECT  2.16 314.415 246.24 314.685 ;
     RECT  2.16 314.955 246.24 315.225 ;
     RECT  2.16 315.495 246.24 315.765 ;
     RECT  2.16 316.035 246.24 316.305 ;
     RECT  2.16 316.575 246.24 316.845 ;
     RECT  2.16 317.115 246.24 317.385 ;
     RECT  2.16 317.655 246.24 317.925 ;
     RECT  2.16 318.195 246.24 318.465 ;
     RECT  2.16 318.735 246.24 319.005 ;
     RECT  2.16 319.275 246.24 319.545 ;
     RECT  2.16 319.815 246.24 320.085 ;
     RECT  2.16 320.355 246.24 320.625 ;
     RECT  2.16 320.895 246.24 321.165 ;
     RECT  2.16 321.435 246.24 321.705 ;
     RECT  2.16 321.975 246.24 322.245 ;
     RECT  2.16 322.515 246.24 322.785 ;
     RECT  2.16 323.055 246.24 323.325 ;
     RECT  2.16 323.595 246.24 323.865 ;
     RECT  2.16 324.135 246.24 324.405 ;
     RECT  2.16 324.675 246.24 324.945 ;
     RECT  2.16 325.215 246.24 325.485 ;
     RECT  2.16 325.755 246.24 326.025 ;
     RECT  2.16 326.295 246.24 326.565 ;
     RECT  2.16 326.835 246.24 327.105 ;
     RECT  2.16 327.375 246.24 327.645 ;
     RECT  2.16 327.915 246.24 328.185 ;
     RECT  2.16 328.455 246.24 328.725 ;
     RECT  2.16 328.995 246.24 329.265 ;
     RECT  2.16 329.535 246.24 329.805 ;
     RECT  2.16 330.075 246.24 330.345 ;
     RECT  2.16 330.615 246.24 330.885 ;
     RECT  2.16 331.155 246.24 331.425 ;
     RECT  2.16 331.695 246.24 331.965 ;
     RECT  2.16 332.235 246.24 332.505 ;
     RECT  2.16 332.775 246.24 333.045 ;
     RECT  2.16 333.315 246.24 333.585 ;
     RECT  2.16 333.855 246.24 334.125 ;
     RECT  2.16 334.395 246.24 334.665 ;
     RECT  2.16 334.935 246.24 335.205 ;
     RECT  2.16 335.475 246.24 335.745 ;
     RECT  2.16 336.015 246.24 336.285 ;
     RECT  2.16 336.555 246.24 336.825 ;
     RECT  2.16 337.095 246.24 337.365 ;
     RECT  2.16 337.635 246.24 337.905 ;
     RECT  2.16 338.175 246.24 338.445 ;
     RECT  2.16 338.715 246.24 338.985 ;
     RECT  2.16 339.255 246.24 339.525 ;
     RECT  2.16 339.795 246.24 340.065 ;
     RECT  2.16 340.335 246.24 340.605 ;
     RECT  2.16 340.875 246.24 341.145 ;
     RECT  2.16 341.415 246.24 341.685 ;
     RECT  2.16 341.955 246.24 342.225 ;
     RECT  2.16 342.495 246.24 342.765 ;
     RECT  2.16 343.035 246.24 343.305 ;
     RECT  2.16 343.575 246.24 343.845 ;
     RECT  2.16 344.115 246.24 344.385 ;
     RECT  2.16 344.655 246.24 344.925 ;
     RECT  2.16 345.195 246.24 345.465 ;
     RECT  2.16 345.735 246.24 346.005 ;
     RECT  2.16 346.275 246.24 346.545 ;
     RECT  2.16 346.815 246.24 347.085 ;
     RECT  2.16 347.355 246.24 347.625 ;
     RECT  2.16 347.895 246.24 348.165 ;
     RECT  2.16 348.435 246.24 348.705 ;
     RECT  2.16 348.975 246.24 349.245 ;
     RECT  2.16 349.515 246.24 349.785 ;
     RECT  2.16 350.055 246.24 350.325 ;
     RECT  2.16 350.595 246.24 350.865 ;
     RECT  2.16 351.135 246.24 351.405 ;
     RECT  2.16 351.675 246.24 351.945 ;
     RECT  2.16 352.215 246.24 352.485 ;
     RECT  2.16 352.755 246.24 353.025 ;
     RECT  2.16 353.295 246.24 353.565 ;
     RECT  2.16 353.835 246.24 354.105 ;
     RECT  2.16 354.375 246.24 354.645 ;
     RECT  2.16 354.915 246.24 355.185 ;
     RECT  2.16 355.455 246.24 355.725 ;
     RECT  2.16 355.995 246.24 356.265 ;
     RECT  2.16 356.535 246.24 356.805 ;
     RECT  2.16 357.075 246.24 357.345 ;
     RECT  2.16 357.615 246.24 357.885 ;
     RECT  2.16 358.155 246.24 358.425 ;
     RECT  2.16 358.695 246.24 358.965 ;
     RECT  2.16 359.235 246.24 359.505 ;
     RECT  2.16 359.775 246.24 360.045 ;
     RECT  2.16 360.315 246.24 360.585 ;
     RECT  2.16 360.855 246.24 361.125 ;
     RECT  2.16 361.395 246.24 361.665 ;
     RECT  2.16 361.935 246.24 362.205 ;
     RECT  2.16 362.475 246.24 362.745 ;
     RECT  2.16 363.015 246.24 363.285 ;
     RECT  2.16 363.555 246.24 363.825 ;
     RECT  2.16 364.095 246.24 364.365 ;
     RECT  2.16 364.635 246.24 364.905 ;
     RECT  2.16 365.175 246.24 365.445 ;
     RECT  2.16 365.715 246.24 365.985 ;
     RECT  2.16 366.255 246.24 366.525 ;
     RECT  2.16 366.795 246.24 367.065 ;
     RECT  2.16 367.335 246.24 367.605 ;
     RECT  2.16 367.875 246.24 368.145 ;
     RECT  2.16 368.415 246.24 368.685 ;
     RECT  2.16 368.955 246.24 369.225 ;
    LAYER M1 ;
     RECT  2.16 2.151 246.24 369.369 ;
    LAYER M2 ;
     RECT  0.031 179.658 0.067 179.676 ;
     RECT  0.103 170.856 0.175 171.576 ;
     RECT  0.067 179.541 0.175 179.676 ;
     RECT  0.175 179.271 0.247 179.676 ;
     RECT  0.247 179.19 0.499 179.676 ;
     RECT  0.499 179.19 0.535 180.288 ;
     RECT  0.103 181.08 0.535 181.098 ;
     RECT  0.031 166.77 2.16 166.788 ;
     RECT  0.067 168.12 2.16 168.138 ;
     RECT  0.175 170.442 2.16 171.576 ;
     RECT  0.247 176.652 2.16 176.67 ;
     RECT  0.535 179.19 2.16 181.26 ;
     RECT  0.175 182.16 2.16 182.178 ;
     RECT  2.16 2.151 246.24 369.369 ;
     RECT  246.24 169.776 246.263 172.584 ;
     RECT  246.263 169.866 246.299 172.584 ;
     RECT  246.24 162.18 246.515 162.774 ;
     RECT  246.24 165.186 246.551 165.294 ;
     RECT  246.24 178.506 246.767 179.334 ;
     RECT  246.299 169.866 246.803 171.954 ;
     RECT  246.767 178.506 246.803 178.524 ;
     RECT  246.767 179.316 246.803 179.334 ;
     RECT  246.24 168.156 246.875 168.174 ;
     RECT  246.515 162.216 247.091 162.774 ;
     RECT  247.091 162.216 247.127 162.234 ;
     RECT  246.551 165.186 247.163 165.204 ;
     RECT  246.803 169.866 247.343 171.774 ;
     RECT  247.343 169.866 247.379 170.424 ;
     RECT  247.343 171.252 247.379 171.774 ;
     RECT  247.379 171.252 247.415 171.27 ;
     RECT  246.24 177.732 247.415 177.75 ;
     RECT  246.24 176.616 247.451 176.634 ;
     RECT  247.379 170.046 248.315 170.064 ;
    LAYER M3 ;
     RECT  2.415 2.143 2.505 2.413 ;
     RECT  7.815 2.143 7.905 2.413 ;
     RECT  13.215 2.143 13.305 2.413 ;
     RECT  18.615 2.143 18.705 2.413 ;
     RECT  24.015 2.143 24.105 2.413 ;
     RECT  29.415 2.143 29.505 2.413 ;
     RECT  34.815 2.143 34.905 2.413 ;
     RECT  40.215 2.143 40.305 2.413 ;
     RECT  45.615 2.143 45.705 2.413 ;
     RECT  51.015 2.143 51.105 2.413 ;
     RECT  56.415 2.143 56.505 2.413 ;
     RECT  61.815 2.143 61.905 2.413 ;
     RECT  67.215 2.143 67.305 2.413 ;
     RECT  72.615 2.143 72.705 2.413 ;
     RECT  78.015 2.143 78.105 2.413 ;
     RECT  83.415 2.143 83.505 2.413 ;
     RECT  88.815 2.143 88.905 2.413 ;
     RECT  94.215 2.143 94.305 2.413 ;
     RECT  99.615 2.143 99.705 2.413 ;
     RECT  105.015 2.143 105.105 2.413 ;
     RECT  110.415 2.143 110.505 2.413 ;
     RECT  115.815 2.143 115.905 2.413 ;
     RECT  121.215 2.143 121.305 2.413 ;
     RECT  126.615 2.143 126.705 2.413 ;
     RECT  132.015 2.143 132.105 2.413 ;
     RECT  137.415 2.143 137.505 2.413 ;
     RECT  142.815 2.143 142.905 2.413 ;
     RECT  148.215 2.143 148.305 2.413 ;
     RECT  153.615 2.143 153.705 2.413 ;
     RECT  159.015 2.143 159.105 2.413 ;
     RECT  164.415 2.143 164.505 2.413 ;
     RECT  169.815 2.143 169.905 2.413 ;
     RECT  175.215 2.143 175.305 2.413 ;
     RECT  180.615 2.143 180.705 2.413 ;
     RECT  186.015 2.143 186.105 2.413 ;
     RECT  191.415 2.143 191.505 2.413 ;
     RECT  196.815 2.143 196.905 2.413 ;
     RECT  202.215 2.143 202.305 2.413 ;
     RECT  207.615 2.143 207.705 2.413 ;
     RECT  213.015 2.143 213.105 2.413 ;
     RECT  218.415 2.143 218.505 2.413 ;
     RECT  223.815 2.143 223.905 2.413 ;
     RECT  229.215 2.143 229.305 2.413 ;
     RECT  234.615 2.143 234.705 2.413 ;
     RECT  240.015 2.143 240.105 2.413 ;
     RECT  245.415 2.143 245.505 2.413 ;
     RECT  146.448 130.819 146.466 130.891 ;
     RECT  145.728 130.891 147.186 131.009 ;
     RECT  144.756 130.819 144.774 131.017 ;
     RECT  145.728 131.009 146.646 131.017 ;
     RECT  142.815 2.413 143.097 131.053 ;
     RECT  144.756 131.017 146.646 131.161 ;
     RECT  142.815 131.053 143.658 131.251 ;
     RECT  144.72 131.161 146.646 131.251 ;
     RECT  148.215 2.413 148.497 131.521 ;
     RECT  140.652 131.557 140.67 131.593 ;
     RECT  141.444 131.557 141.462 131.593 ;
     RECT  140.652 131.593 141.462 131.597 ;
     RECT  140.796 131.597 141.462 131.701 ;
     RECT  142.815 131.251 146.646 131.899 ;
     RECT  147.744 131.521 148.497 131.899 ;
     RECT  140.796 131.701 141.93 131.971 ;
     RECT  142.815 131.899 148.497 131.971 ;
     RECT  140.796 131.971 148.497 132.197 ;
     RECT  140.04 132.709 140.058 132.781 ;
     RECT  140.796 132.197 145.782 132.781 ;
     RECT  137.415 2.413 137.697 132.871 ;
     RECT  140.04 132.781 145.782 132.979 ;
     RECT  146.52 132.197 148.497 132.979 ;
     RECT  140.04 132.979 148.497 133.285 ;
     RECT  139.968 133.285 148.497 133.709 ;
     RECT  137.16 132.871 137.697 133.825 ;
     RECT  137.16 133.825 137.934 133.951 ;
     RECT  137.16 133.951 138.474 134.059 ;
     RECT  139.968 133.709 141.102 134.059 ;
     RECT  139.788 134.059 141.102 134.131 ;
     RECT  139.716 134.131 141.102 134.257 ;
     RECT  137.16 134.059 138.798 134.329 ;
     RECT  136.872 134.329 138.798 134.401 ;
     RECT  139.572 134.257 141.102 134.401 ;
     RECT  142.02 133.709 148.497 134.587 ;
     RECT  136.872 134.401 141.102 134.671 ;
     RECT  141.84 134.587 148.497 134.671 ;
     RECT  136.764 134.671 148.497 134.731 ;
     RECT  136.62 134.731 148.497 134.789 ;
     RECT  136.764 134.789 148.497 135.059 ;
     RECT  136.764 135.059 147.402 135.877 ;
     RECT  148.215 135.059 148.497 135.877 ;
     RECT  135.684 136.291 135.882 136.453 ;
     RECT  135.576 136.453 135.882 136.525 ;
     RECT  135.144 136.525 135.882 136.561 ;
     RECT  135.144 136.561 135.99 136.759 ;
     RECT  134.604 136.759 135.99 136.795 ;
     RECT  136.764 135.877 148.497 136.795 ;
     RECT  134.172 136.795 135.99 136.831 ;
     RECT  136.764 136.795 149.13 136.831 ;
     RECT  134.172 136.831 149.13 136.949 ;
     RECT  134.172 136.949 148.662 137.255 ;
     RECT  134.172 137.255 148.59 137.903 ;
     RECT  134.496 137.903 148.59 137.933 ;
     RECT  134.964 137.933 148.59 138.101 ;
     RECT  135.072 138.101 148.59 138.271 ;
     RECT  135.072 138.271 148.662 138.541 ;
     RECT  135.072 138.541 148.698 139.099 ;
     RECT  151.74 139.081 151.758 139.133 ;
     RECT  134.424 139.099 148.698 139.153 ;
     RECT  150.192 139.099 150.498 139.289 ;
     RECT  150.192 139.289 150.282 139.325 ;
     RECT  150.228 139.325 150.282 139.379 ;
     RECT  134.244 139.153 148.698 140.071 ;
     RECT  150.084 140.071 150.102 140.197 ;
     RECT  151.524 140.071 151.542 140.197 ;
     RECT  134.244 140.071 148.986 140.233 ;
     RECT  151.092 140.197 151.542 140.233 ;
     RECT  134.244 140.233 149.238 140.341 ;
     RECT  150.084 140.197 150.282 140.341 ;
     RECT  151.056 140.233 151.542 140.341 ;
     RECT  134.244 140.341 151.542 140.459 ;
     RECT  151.056 140.459 151.542 140.729 ;
     RECT  151.164 140.729 151.542 140.881 ;
     RECT  151.164 140.881 151.614 141.115 ;
     RECT  151.164 141.115 152.118 141.151 ;
     RECT  134.244 140.459 150.21 141.269 ;
     RECT  134.82 141.269 150.21 141.643 ;
     RECT  134.82 141.643 150.39 141.655 ;
     RECT  151.164 141.151 152.586 141.655 ;
     RECT  134.82 141.655 152.586 142.159 ;
     RECT  153.615 2.413 153.897 142.159 ;
     RECT  134.82 142.159 153.897 142.195 ;
     RECT  134.532 142.195 153.897 142.421 ;
     RECT  134.532 142.421 150.462 142.493 ;
     RECT  151.272 142.421 153.897 142.889 ;
     RECT  134.532 142.493 139.77 143.117 ;
     RECT  135.108 143.117 139.77 143.239 ;
     RECT  140.616 142.493 150.462 143.239 ;
     RECT  135.108 143.239 150.462 143.303 ;
     RECT  135.216 143.303 150.462 143.707 ;
     RECT  151.488 142.889 153.897 143.707 ;
     RECT  135.216 143.707 153.897 143.851 ;
     RECT  135.216 143.851 153.954 143.969 ;
     RECT  150.624 143.969 153.954 144.751 ;
     RECT  150.624 144.751 154.242 144.787 ;
     RECT  135.216 143.969 149.706 144.895 ;
     RECT  150.552 144.787 154.242 144.895 ;
     RECT  135.216 144.895 154.242 145.471 ;
     RECT  135.216 145.471 154.494 145.741 ;
     RECT  135.216 145.741 155.214 145.859 ;
     RECT  135.216 145.859 154.782 146.129 ;
     RECT  135.216 146.129 154.494 146.543 ;
     RECT  133.812 146.641 133.83 146.749 ;
     RECT  133.668 146.749 134.046 146.785 ;
     RECT  133.2 146.785 134.046 146.821 ;
     RECT  135.216 146.543 150.462 146.821 ;
     RECT  132.015 2.413 132.297 147.019 ;
     RECT  133.2 146.821 150.462 147.019 ;
     RECT  151.272 146.543 154.494 147.217 ;
     RECT  132.015 147.019 150.462 147.289 ;
     RECT  151.272 147.217 154.602 147.289 ;
     RECT  132.015 147.289 154.602 147.559 ;
     RECT  132.015 147.559 155.034 147.595 ;
     RECT  132.015 147.595 155.394 147.749 ;
     RECT  132.015 147.749 155.034 147.785 ;
     RECT  132.015 147.785 154.998 148.595 ;
     RECT  154.98 148.595 154.998 148.739 ;
     RECT  155.052 149.485 155.07 149.719 ;
     RECT  132.015 148.595 154.026 149.755 ;
     RECT  131.796 149.755 154.314 149.791 ;
     RECT  155.052 149.719 155.286 149.791 ;
     RECT  131.796 149.791 155.61 150.529 ;
     RECT  131.796 150.529 156.114 150.565 ;
     RECT  131.796 150.565 156.258 150.871 ;
     RECT  131.796 150.871 156.798 151.613 ;
     RECT  132.015 151.613 156.798 151.681 ;
     RECT  132.015 151.681 156.834 152.069 ;
     RECT  132.015 152.069 151.074 152.375 ;
     RECT  134.496 152.375 151.074 152.483 ;
     RECT  151.848 152.069 156.834 152.725 ;
     RECT  132.015 152.375 133.506 152.779 ;
     RECT  131.724 152.779 133.506 152.951 ;
     RECT  134.64 152.483 151.074 152.971 ;
     RECT  151.848 152.725 156.942 152.971 ;
     RECT  134.64 152.971 156.942 153.265 ;
     RECT  132.015 152.951 133.506 153.499 ;
     RECT  134.64 153.265 157.626 153.499 ;
     RECT  132.015 153.499 157.734 153.571 ;
     RECT  132.015 153.571 158.13 153.841 ;
     RECT  131.688 153.841 158.13 153.931 ;
     RECT  131.688 153.931 158.274 154.075 ;
     RECT  159.015 2.413 159.297 154.075 ;
     RECT  131.688 154.075 159.297 154.309 ;
     RECT  131.508 154.309 159.297 154.579 ;
     RECT  131.508 154.579 159.39 154.615 ;
     RECT  131.508 154.615 159.426 154.651 ;
     RECT  131.508 154.651 159.858 154.921 ;
     RECT  131.328 154.921 159.858 154.949 ;
     RECT  131.328 154.949 159.57 155.039 ;
     RECT  130.212 154.921 130.23 155.047 ;
     RECT  129.924 155.047 130.23 155.155 ;
     RECT  131.328 155.039 159.426 155.155 ;
     RECT  129.888 155.155 159.426 155.191 ;
     RECT  129.672 155.191 159.426 155.309 ;
     RECT  129.672 155.309 159.39 155.425 ;
     RECT  129.456 155.425 159.39 155.587 ;
     RECT  129.312 155.587 159.39 155.651 ;
     RECT  129.312 155.651 130.23 155.731 ;
     RECT  128.88 155.731 130.23 155.929 ;
     RECT  128.7 155.929 130.23 156.191 ;
     RECT  128.988 156.191 130.23 156.433 ;
     RECT  130.968 155.651 159.39 156.433 ;
     RECT  128.988 156.433 159.39 156.731 ;
     RECT  131.184 156.731 159.39 156.937 ;
     RECT  131.184 156.937 159.498 156.973 ;
     RECT  128.988 156.731 130.302 157.351 ;
     RECT  128.88 157.351 130.302 157.435 ;
     RECT  128.736 157.435 130.302 157.475 ;
     RECT  129.456 157.475 130.302 157.477 ;
     RECT  131.184 156.973 160.254 157.477 ;
     RECT  129.456 157.477 160.254 157.621 ;
     RECT  129.456 157.621 160.902 157.739 ;
     RECT  129.456 157.739 133.506 157.775 ;
     RECT  134.316 157.739 160.398 157.883 ;
     RECT  134.352 157.883 160.398 158.009 ;
     RECT  129.672 157.775 133.506 158.045 ;
     RECT  134.352 158.009 159.786 158.045 ;
     RECT  134.568 158.045 159.786 158.081 ;
     RECT  129.708 158.045 133.506 158.387 ;
     RECT  134.604 158.081 159.786 158.549 ;
     RECT  134.604 158.549 159.606 158.729 ;
     RECT  244.332 158.665 244.35 158.819 ;
     RECT  131.976 158.387 133.506 158.863 ;
     RECT  129.708 158.387 131.058 158.935 ;
     RECT  131.976 158.863 133.542 158.935 ;
     RECT  134.604 158.729 159.57 158.935 ;
     RECT  129.528 158.935 131.058 159.005 ;
     RECT  244.584 158.971 244.602 159.395 ;
     RECT  131.976 158.935 159.57 159.511 ;
     RECT  245.415 2.413 245.697 159.511 ;
     RECT  129.6 159.005 131.058 159.637 ;
     RECT  131.904 159.511 159.57 159.637 ;
     RECT  105.015 2.413 105.297 159.673 ;
     RECT  2.415 2.413 2.697 159.691 ;
     RECT  105.015 159.673 105.678 159.745 ;
     RECT  2.304 159.691 2.697 159.773 ;
     RECT  128.448 159.745 128.466 159.781 ;
     RECT  129.6 159.637 159.822 159.781 ;
     RECT  0.108 159.595 0.126 159.787 ;
     RECT  104.904 159.745 105.678 159.871 ;
     RECT  94.215 2.413 94.497 159.907 ;
     RECT  104.904 159.871 105.858 159.907 ;
     RECT  128.376 159.781 128.466 159.907 ;
     RECT  2.415 159.773 2.697 159.931 ;
     RECT  3.564 159.781 3.582 159.931 ;
     RECT  129.492 159.781 160.29 159.935 ;
     RECT  128.376 159.907 128.61 159.943 ;
     RECT  129.492 159.935 159.534 159.943 ;
     RECT  0.108 159.787 0.45 159.965 ;
     RECT  160.272 159.935 160.29 160.007 ;
     RECT  0.108 159.965 0.378 160.013 ;
     RECT  99.615 2.413 99.897 160.015 ;
     RECT  2.415 159.931 3.582 160.051 ;
     RECT  99.612 160.015 99.897 160.051 ;
     RECT  103.86 160.015 103.878 160.051 ;
     RECT  104.904 159.907 106.002 160.051 ;
     RECT  128.376 159.943 159.534 160.051 ;
     RECT  94.215 159.907 94.662 160.079 ;
     RECT  0.108 160.013 0.162 160.109 ;
     RECT  2.415 160.051 3.762 160.169 ;
     RECT  122.652 160.051 122.67 160.169 ;
     RECT  127.764 160.051 159.534 160.169 ;
     RECT  98.712 160.051 100.17 160.171 ;
     RECT  126.615 2.413 126.897 160.177 ;
     RECT  98.712 160.171 100.35 160.213 ;
     RECT  101.52 160.141 101.538 160.213 ;
     RECT  98.712 160.213 101.538 160.285 ;
     RECT  102.564 160.051 106.002 160.285 ;
     RECT  98.712 160.285 106.002 160.321 ;
     RECT  2.415 160.169 3.654 160.439 ;
     RECT  118.584 160.321 118.602 160.439 ;
     RECT  126.504 160.177 127.458 160.447 ;
     RECT  98.604 160.321 106.038 160.511 ;
     RECT  126.36 160.447 127.458 160.591 ;
     RECT  123.48 160.411 123.498 160.699 ;
     RECT  124.344 160.141 124.362 160.717 ;
     RECT  125.748 160.591 127.458 160.717 ;
     RECT  122.508 160.285 122.526 160.733 ;
     RECT  123.3 160.699 123.498 160.745 ;
     RECT  98.964 160.511 106.038 160.951 ;
     RECT  128.268 160.169 159.534 160.951 ;
     RECT  94.215 160.079 94.497 160.987 ;
     RECT  96.912 160.861 96.93 161.015 ;
     RECT  125.712 160.717 127.458 161.131 ;
     RECT  128.268 160.951 159.966 161.131 ;
     RECT  2.415 160.439 3.582 161.159 ;
     RECT  94.215 160.987 94.662 161.159 ;
     RECT  244.8 159.511 245.697 161.221 ;
     RECT  124.344 160.717 124.722 161.257 ;
     RECT  98.964 160.951 106.074 161.293 ;
     RECT  124.344 161.257 124.902 161.401 ;
     RECT  123.66 161.401 124.974 161.491 ;
     RECT  125.712 161.131 159.966 161.491 ;
     RECT  98.784 161.293 106.074 161.527 ;
     RECT  98.136 161.527 106.074 161.599 ;
     RECT  98.136 161.599 106.254 161.671 ;
     RECT  122.724 161.671 122.742 161.755 ;
     RECT  123.66 161.491 159.966 161.755 ;
     RECT  122.724 161.755 159.966 161.899 ;
     RECT  122.724 161.899 160.002 161.905 ;
     RECT  121.215 2.413 121.497 161.941 ;
     RECT  122.616 161.905 160.002 161.941 ;
     RECT  2.415 161.159 3.402 161.969 ;
     RECT  121.215 161.941 121.806 162.059 ;
     RECT  122.616 161.941 160.47 162.059 ;
     RECT  97.02 161.671 106.254 162.067 ;
     RECT  244.188 161.221 245.697 162.203 ;
     RECT  96.876 162.067 106.254 162.211 ;
     RECT  246.492 162.175 246.51 162.211 ;
     RECT  121.215 162.059 121.662 162.221 ;
     RECT  122.724 162.059 160.47 162.337 ;
     RECT  161.244 162.211 161.262 162.337 ;
     RECT  96.876 162.211 106.29 162.599 ;
     RECT  97.416 162.599 106.29 162.679 ;
     RECT  97.416 162.679 106.398 162.751 ;
     RECT  97.416 162.751 106.542 162.779 ;
     RECT  97.452 162.779 106.542 162.869 ;
     RECT  164.415 2.413 164.697 162.985 ;
     RECT  162.288 162.913 162.306 163.013 ;
     RECT  122.724 162.337 161.262 163.021 ;
     RECT  162.216 163.021 162.234 163.139 ;
     RECT  122.724 163.021 161.334 163.211 ;
     RECT  122.976 163.211 161.334 163.219 ;
     RECT  101.988 162.869 106.542 163.285 ;
     RECT  101.988 163.285 106.866 163.325 ;
     RECT  122.976 163.219 161.766 163.553 ;
     RECT  97.452 162.869 101.106 163.561 ;
     RECT  108.324 163.291 108.342 163.565 ;
     RECT  97.416 163.561 101.106 163.651 ;
     RECT  101.988 163.325 106.542 163.651 ;
     RECT  96.624 162.751 96.642 164.101 ;
     RECT  97.416 163.651 106.542 164.101 ;
     RECT  123.048 163.553 161.766 164.101 ;
     RECT  121.215 162.221 121.497 164.191 ;
     RECT  123.048 164.101 161.838 164.227 ;
     RECT  121.104 164.191 121.497 164.237 ;
     RECT  123.048 164.227 162.45 164.327 ;
     RECT  123.048 164.327 123.966 164.371 ;
     RECT  244.8 162.203 245.697 164.371 ;
     RECT  246.492 162.211 247.122 164.371 ;
     RECT  114.264 164.191 114.282 164.489 ;
     RECT  122.76 164.371 123.966 164.491 ;
     RECT  114.12 164.641 114.138 164.717 ;
     RECT  96.624 164.101 106.542 164.725 ;
     RECT  96.624 164.725 106.866 164.911 ;
     RECT  96.624 164.911 107.19 164.939 ;
     RECT  162.792 165.001 162.81 165.019 ;
     RECT  163.8 162.985 164.697 165.019 ;
     RECT  162.792 165.019 164.697 165.053 ;
     RECT  163.476 165.053 164.697 165.065 ;
     RECT  122.616 164.491 123.966 165.181 ;
     RECT  124.884 164.327 161.982 165.181 ;
     RECT  244.8 164.371 247.122 165.181 ;
     RECT  122.436 165.181 123.966 165.299 ;
     RECT  123.084 165.299 123.966 165.307 ;
     RECT  124.884 165.181 162.09 165.307 ;
     RECT  122.292 165.403 122.31 165.443 ;
     RECT  96.876 164.939 107.19 165.479 ;
     RECT  123.084 165.307 162.09 165.569 ;
     RECT  123.156 165.569 162.09 165.641 ;
     RECT  123.264 165.641 162.09 165.875 ;
     RECT  123.3 165.875 162.09 165.947 ;
     RECT  96.948 165.479 107.19 165.991 ;
     RECT  108 165.721 108.018 166.181 ;
     RECT  96.948 165.991 107.226 166.189 ;
     RECT  96.948 166.189 107.262 166.387 ;
     RECT  96.156 166.387 107.262 166.411 ;
     RECT  123.588 165.947 162.09 166.423 ;
     RECT  95.508 166.411 107.262 166.445 ;
     RECT  244.8 165.181 247.158 166.495 ;
     RECT  123.588 166.423 162.414 166.531 ;
     RECT  123.588 166.531 162.882 166.649 ;
     RECT  95.508 166.445 95.778 166.685 ;
     RECT  123.588 166.649 162.414 166.685 ;
     RECT  0.108 160.109 0.126 166.765 ;
     RECT  90.648 166.621 90.666 166.793 ;
     RECT  123.588 166.685 162.09 166.963 ;
     RECT  123.408 166.963 162.09 167.021 ;
     RECT  96.516 166.445 107.262 167.179 ;
     RECT  96.516 167.179 107.442 167.225 ;
     RECT  123.768 167.021 162.09 167.225 ;
     RECT  96.516 167.225 107.262 167.333 ;
     RECT  160.2 167.225 162.09 167.431 ;
     RECT  107.244 167.333 107.262 167.567 ;
     RECT  95.76 166.685 95.778 167.575 ;
     RECT  95.724 167.575 95.778 167.611 ;
     RECT  96.516 167.333 106.506 167.611 ;
     RECT  2.415 161.969 2.697 167.845 ;
     RECT  95.724 167.611 106.506 167.845 ;
     RECT  123.768 167.225 159.462 167.971 ;
     RECT  160.2 167.431 162.378 167.971 ;
     RECT  2.415 167.845 2.934 167.999 ;
     RECT  94.215 161.159 94.497 168.091 ;
     RECT  95.688 167.845 106.506 168.091 ;
     RECT  94.215 168.091 106.506 168.143 ;
     RECT  95.328 168.143 106.506 168.151 ;
     RECT  123.768 167.971 162.378 168.173 ;
     RECT  115.815 2.413 116.097 168.277 ;
     RECT  115.815 168.277 116.514 168.313 ;
     RECT  117.864 168.277 117.882 168.313 ;
     RECT  124.956 168.173 162.378 168.313 ;
     RECT  115.524 168.313 116.514 168.317 ;
     RECT  122.544 167.809 122.562 168.341 ;
     RECT  95.328 168.151 106.578 168.349 ;
     RECT  115.524 168.317 116.097 168.349 ;
     RECT  117.864 168.313 118.134 168.413 ;
     RECT  95.328 168.349 106.758 168.449 ;
     RECT  117.864 168.413 117.882 168.449 ;
     RECT  124.956 168.313 162.522 168.575 ;
     RECT  95.832 168.449 106.758 168.853 ;
     RECT  115.236 168.349 116.097 168.917 ;
     RECT  124.956 168.575 160.29 168.917 ;
     RECT  117.54 168.781 117.594 168.925 ;
     RECT  93.132 168.781 93.15 168.961 ;
     RECT  114.048 168.889 114.066 168.961 ;
     RECT  122.616 168.889 122.634 168.989 ;
     RECT  114.048 168.961 114.138 169.045 ;
     RECT  114.048 169.045 114.39 169.051 ;
     RECT  124.956 168.917 156.33 169.051 ;
     RECT  161.028 168.575 162.522 169.079 ;
     RECT  113.904 169.051 114.39 169.085 ;
     RECT  113.904 169.085 114.138 169.115 ;
     RECT  113.904 169.115 114.066 169.151 ;
     RECT  115.344 168.917 116.097 169.151 ;
     RECT  95.832 168.853 106.938 169.159 ;
     RECT  113.904 169.151 113.922 169.187 ;
     RECT  116.928 168.925 117.594 169.223 ;
     RECT  95.832 169.159 107.082 169.259 ;
     RECT  117.54 169.223 117.558 169.259 ;
     RECT  124.884 169.051 156.33 169.291 ;
     RECT  93.132 168.961 93.474 169.321 ;
     RECT  94.215 168.143 94.497 169.321 ;
     RECT  95.832 169.259 106.686 169.321 ;
     RECT  123.768 168.173 123.786 169.321 ;
     RECT  124.524 169.291 156.33 169.321 ;
     RECT  93.132 169.321 94.497 169.349 ;
     RECT  123.768 169.321 156.33 169.393 ;
     RECT  2.415 167.999 2.697 169.429 ;
     RECT  90.648 169.429 90.666 169.529 ;
     RECT  123.696 169.393 156.33 169.591 ;
     RECT  157.104 168.917 160.29 169.699 ;
     RECT  161.028 169.079 162.486 169.699 ;
     RECT  123.156 169.591 156.33 169.735 ;
     RECT  244.224 166.495 247.158 169.771 ;
     RECT  118.584 169.501 118.602 169.799 ;
     RECT  122.544 169.735 156.33 169.933 ;
     RECT  157.104 169.699 162.486 169.933 ;
     RECT  122.544 169.933 162.486 170.041 ;
     RECT  243.072 167.071 243.09 170.041 ;
     RECT  244.224 169.771 247.374 170.041 ;
     RECT  248.292 169.675 248.31 170.069 ;
     RECT  95.76 169.321 106.686 170.159 ;
     RECT  107.568 170.041 107.586 170.159 ;
     RECT  122.544 170.041 162.702 170.159 ;
     RECT  242.316 168.655 242.334 170.167 ;
     RECT  122.544 170.159 162.522 170.339 ;
     RECT  242.244 170.167 242.334 170.339 ;
     RECT  90.648 170.311 90.666 170.429 ;
     RECT  101.772 170.159 106.686 170.429 ;
     RECT  243.072 170.041 247.374 170.429 ;
     RECT  0.036 166.765 0.126 170.437 ;
     RECT  93.132 169.349 93.15 170.437 ;
     RECT  93.96 169.349 94.497 170.437 ;
     RECT  122.544 170.339 162.45 170.465 ;
     RECT  122.544 170.465 122.562 170.477 ;
     RECT  93.132 170.437 94.497 170.509 ;
     RECT  163.8 165.065 164.697 170.545 ;
     RECT  88.815 2.413 89.097 170.581 ;
     RECT  93.132 170.509 94.662 170.581 ;
     RECT  163.656 170.545 164.697 170.621 ;
     RECT  175.215 2.413 175.497 170.671 ;
     RECT  186.015 2.413 186.297 170.671 ;
     RECT  196.815 2.413 197.097 170.671 ;
     RECT  207.615 2.413 207.897 170.671 ;
     RECT  218.415 2.413 218.697 170.671 ;
     RECT  229.215 2.413 229.497 170.671 ;
     RECT  240.015 2.413 240.297 170.671 ;
     RECT  88.815 170.581 89.478 170.699 ;
     RECT  243.072 170.429 247.338 170.699 ;
     RECT  243.468 170.699 247.338 170.717 ;
     RECT  95.76 170.159 100.926 170.735 ;
     RECT  243.468 170.717 243.486 170.813 ;
     RECT  86.652 170.707 86.67 170.879 ;
     RECT  93.132 170.581 94.734 170.969 ;
     RECT  244.224 170.717 247.338 170.969 ;
     RECT  95.76 170.735 100.89 170.977 ;
     RECT  101.772 170.429 106.614 171.085 ;
     RECT  95.544 170.977 100.89 171.121 ;
     RECT  164.304 170.621 164.697 171.149 ;
     RECT  123.444 170.465 162.45 171.211 ;
     RECT  242.316 170.339 242.334 171.239 ;
     RECT  101.736 171.085 106.614 171.247 ;
     RECT  107.64 171.121 107.658 171.247 ;
     RECT  244.296 170.969 247.338 171.247 ;
     RECT  166.428 171.211 166.446 171.248 ;
     RECT  175.104 170.671 175.497 171.248 ;
     RECT  185.904 170.671 186.297 171.248 ;
     RECT  196.704 170.671 197.097 171.248 ;
     RECT  207.504 170.671 207.897 171.248 ;
     RECT  218.304 170.671 218.697 171.248 ;
     RECT  229.104 170.671 229.497 171.248 ;
     RECT  239.904 170.671 240.297 171.248 ;
     RECT  165.744 171.307 165.762 171.347 ;
     RECT  2.415 169.429 3.078 171.391 ;
     RECT  101.736 171.247 107.658 171.391 ;
     RECT  93.132 170.969 94.662 171.419 ;
     RECT  123.444 171.211 162.486 171.481 ;
     RECT  95.508 171.121 100.89 171.509 ;
     RECT  95.544 171.509 100.89 171.517 ;
     RECT  101.664 171.391 107.658 171.517 ;
     RECT  242.424 171.391 242.442 171.545 ;
     RECT  244.296 171.247 247.41 171.629 ;
     RECT  123.084 171.481 162.486 171.661 ;
     RECT  109.152 167.539 109.17 171.739 ;
     RECT  123.084 171.661 162.882 171.751 ;
     RECT  109.152 171.739 109.458 171.779 ;
     RECT  244.296 171.629 247.374 171.779 ;
     RECT  244.296 171.779 247.158 171.815 ;
     RECT  2.415 171.391 3.222 171.823 ;
     RECT  4.248 168.421 4.266 171.823 ;
     RECT  93.132 171.419 94.626 171.851 ;
     RECT  110.415 2.413 110.697 171.883 ;
     RECT  123.084 171.751 162.954 171.887 ;
     RECT  114.588 171.391 114.606 171.917 ;
     RECT  123.084 171.887 123.21 171.923 ;
     RECT  123.948 171.887 162.954 171.923 ;
     RECT  95.544 171.517 107.658 171.931 ;
     RECT  123.192 171.923 123.21 172.049 ;
     RECT  124.344 171.923 162.954 172.049 ;
     RECT  124.488 172.049 162.954 172.157 ;
     RECT  244.944 171.815 247.158 172.157 ;
     RECT  95.544 171.931 107.766 172.201 ;
     RECT  109.152 171.779 109.17 172.201 ;
     RECT  110.196 171.883 110.697 172.253 ;
     RECT  95.544 172.201 107.802 172.291 ;
     RECT  108.936 172.201 109.17 172.291 ;
     RECT  164.415 171.149 164.697 172.291 ;
     RECT  248.22 172.123 248.238 172.301 ;
     RECT  93.708 171.851 94.626 172.315 ;
     RECT  95.544 172.291 109.17 172.315 ;
     RECT  93.708 172.315 109.17 172.355 ;
     RECT  245.304 172.157 247.158 172.397 ;
     RECT  247.14 172.397 247.158 172.493 ;
     RECT  164.16 172.291 164.697 172.597 ;
     RECT  245.304 172.397 246.294 172.685 ;
     RECT  95.508 172.355 109.17 172.741 ;
     RECT  124.668 172.157 162.954 172.741 ;
     RECT  95.508 172.741 109.278 172.859 ;
     RECT  164.16 172.597 165.114 172.859 ;
     RECT  95.508 172.859 109.17 172.925 ;
     RECT  124.668 172.741 163.062 173.003 ;
     RECT  124.992 173.003 163.062 173.011 ;
     RECT  164.16 172.859 164.697 173.069 ;
     RECT  124.992 173.011 163.098 173.129 ;
     RECT  164.304 173.069 164.697 173.129 ;
     RECT  93.708 172.355 94.626 173.479 ;
     RECT  93.708 173.479 94.662 173.579 ;
     RECT  95.544 172.925 109.17 173.911 ;
     RECT  245.304 172.685 246.222 173.939 ;
     RECT  95.508 173.911 109.17 174.091 ;
     RECT  245.304 173.939 245.697 174.209 ;
     RECT  124.056 174.361 124.074 174.559 ;
     RECT  124.992 173.129 162.27 174.715 ;
     RECT  124.992 174.715 162.666 174.721 ;
     RECT  163.584 174.181 163.602 174.749 ;
     RECT  93.708 173.579 94.626 174.865 ;
     RECT  95.436 174.091 109.17 174.865 ;
     RECT  124.992 174.721 162.81 174.901 ;
     RECT  245.34 174.209 245.697 175.019 ;
     RECT  124.992 174.901 163.494 175.055 ;
     RECT  93.708 174.865 109.17 175.135 ;
     RECT  93.708 175.135 109.602 175.171 ;
     RECT  110.415 172.253 110.697 175.171 ;
     RECT  163.476 175.055 163.494 175.559 ;
     RECT  93.708 175.171 110.697 175.909 ;
     RECT  93.708 175.909 111.15 176.107 ;
     RECT  93.672 176.107 111.294 176.141 ;
     RECT  93.672 176.141 94.497 176.144 ;
     RECT  95.256 176.141 111.294 176.251 ;
     RECT  95.256 176.251 111.798 176.369 ;
     RECT  165.96 176.341 165.978 176.381 ;
     RECT  244.008 176.341 244.026 176.381 ;
     RECT  95.256 176.369 111.294 176.405 ;
     RECT  0.036 170.437 0.198 176.647 ;
     RECT  244.08 176.521 244.098 176.675 ;
     RECT  124.992 175.055 162.378 176.791 ;
     RECT  115.815 169.151 116.097 176.881 ;
     RECT  123.624 174.559 124.074 176.953 ;
     RECT  124.992 176.791 162.558 176.953 ;
     RECT  115.815 176.881 116.154 176.957 ;
     RECT  93.708 176.144 94.497 176.981 ;
     RECT  95.256 176.405 111.258 177.089 ;
     RECT  94.215 176.981 94.497 177.151 ;
     RECT  95.256 177.089 111.15 177.151 ;
     RECT  123.624 176.953 162.558 177.331 ;
     RECT  94.215 177.151 111.15 177.449 ;
     RECT  114.552 176.683 114.57 177.521 ;
     RECT  123.624 177.331 163.242 177.629 ;
     RECT  157.608 177.629 163.242 177.719 ;
     RECT  245.415 175.019 245.697 177.727 ;
     RECT  247.428 176.611 247.446 177.727 ;
     RECT  94.215 177.449 110.97 177.961 ;
     RECT  93.888 177.961 110.97 178.061 ;
     RECT  123.624 177.629 156.87 178.231 ;
     RECT  93.888 178.061 108.774 178.295 ;
     RECT  247.392 177.727 247.446 178.315 ;
     RECT  122.4 178.105 122.418 178.375 ;
     RECT  123.336 178.231 156.87 178.375 ;
     RECT  157.608 177.719 163.026 178.375 ;
     RECT  122.4 178.375 163.026 178.403 ;
     RECT  164.415 173.129 164.697 178.411 ;
     RECT  245.415 177.727 246.042 178.411 ;
     RECT  246.78 178.315 247.446 178.411 ;
     RECT  164.232 178.411 164.697 178.681 ;
     RECT  94.215 178.295 108.774 178.709 ;
     RECT  122.508 178.403 163.026 178.799 ;
     RECT  245.415 178.411 247.446 178.829 ;
     RECT  104.904 178.709 108.774 178.835 ;
     RECT  122.508 178.799 160.254 178.925 ;
     RECT  2.415 171.823 4.266 178.951 ;
     RECT  90.648 178.807 90.666 178.979 ;
     RECT  244.584 178.915 244.602 179.069 ;
     RECT  105.015 178.835 108.774 179.149 ;
     RECT  94.215 178.709 104.166 179.179 ;
     RECT  0.036 176.647 0.27 179.185 ;
     RECT  105.015 179.149 108.918 179.221 ;
     RECT  109.692 178.061 110.97 179.221 ;
     RECT  93.636 179.179 104.166 179.339 ;
     RECT  105.015 179.221 110.97 179.339 ;
     RECT  245.415 178.829 246.798 179.339 ;
     RECT  118.584 179.221 118.602 179.447 ;
     RECT  244.656 179.185 244.674 179.455 ;
     RECT  245.415 179.339 246.186 179.455 ;
     RECT  99 179.339 104.166 179.581 ;
     RECT  105.015 179.339 108.846 179.581 ;
     RECT  244.656 179.455 246.186 179.609 ;
     RECT  121.215 164.237 121.497 179.617 ;
     RECT  122.508 178.925 160.074 179.617 ;
     RECT  164.16 178.681 164.697 179.617 ;
     RECT  0.036 179.185 0.558 179.681 ;
     RECT  121.215 179.617 160.074 179.717 ;
     RECT  2.415 178.951 4.302 179.725 ;
     RECT  92.916 179.347 92.934 179.753 ;
     RECT  122.544 179.717 160.074 179.761 ;
     RECT  160.992 178.799 163.026 179.761 ;
     RECT  115.02 178.771 115.038 179.879 ;
     RECT  244.656 179.609 244.674 179.879 ;
     RECT  2.304 179.725 4.302 179.885 ;
     RECT  164.124 179.617 164.697 179.995 ;
     RECT  113.328 179.989 113.346 180.029 ;
     RECT  99 179.581 108.846 180.121 ;
     RECT  109.584 179.339 110.97 180.121 ;
     RECT  122.544 179.761 163.026 180.139 ;
     RECT  164.088 179.995 164.697 180.173 ;
     RECT  99 180.121 110.97 180.265 ;
     RECT  99 180.265 111.618 180.301 ;
     RECT  93.42 180.301 93.438 180.365 ;
     RECT  90.648 180.301 90.666 180.419 ;
     RECT  99 180.301 111.798 180.419 ;
     RECT  99 180.419 109.278 180.455 ;
     RECT  94.176 179.339 98.226 180.535 ;
     RECT  99 180.455 109.062 180.535 ;
     RECT  122.544 180.139 163.206 180.557 ;
     RECT  110.376 180.419 111.798 180.571 ;
     RECT  92.916 180.499 92.934 180.599 ;
     RECT  94.176 180.535 109.062 180.599 ;
     RECT  110.376 180.571 112.122 180.599 ;
     RECT  6.804 180.571 6.822 180.689 ;
     RECT  104.904 180.599 109.062 180.689 ;
     RECT  122.544 180.557 122.562 180.689 ;
     RECT  164.124 180.173 164.697 180.689 ;
     RECT  244.368 180.571 244.386 180.689 ;
     RECT  245.415 179.609 246.186 180.689 ;
     RECT  123.3 180.557 163.206 180.701 ;
     RECT  123.408 180.701 163.206 180.712 ;
     RECT  123.408 180.712 162.774 180.725 ;
     RECT  2.34 179.885 4.302 180.749 ;
     RECT  110.415 180.599 112.122 180.797 ;
     RECT  2.34 180.749 3.366 180.805 ;
     RECT  94.176 180.599 103.986 180.841 ;
     RECT  112.104 180.797 112.122 180.869 ;
     RECT  93.888 180.841 103.986 180.959 ;
     RECT  93.888 180.959 94.806 180.989 ;
     RECT  123.444 180.725 162.774 181.031 ;
     RECT  92.88 181.003 92.898 181.111 ;
     RECT  92.376 181.111 92.898 181.139 ;
     RECT  95.544 180.959 103.986 181.229 ;
     RECT  99.036 181.229 103.986 181.381 ;
     RECT  99.036 181.381 104.166 181.409 ;
     RECT  95.544 181.229 98.226 181.499 ;
     RECT  0.108 179.681 0.558 181.517 ;
     RECT  0.108 181.517 0.342 181.613 ;
     RECT  2.304 180.805 3.366 181.651 ;
     RECT  4.284 180.749 4.302 181.651 ;
     RECT  99.18 181.409 104.166 181.769 ;
     RECT  231.444 180.571 231.462 181.769 ;
     RECT  163.656 181.771 163.674 181.811 ;
     RECT  94.176 180.989 94.806 181.813 ;
     RECT  104.904 180.689 108.846 181.849 ;
     RECT  104.868 181.849 108.846 181.921 ;
     RECT  123.624 181.031 162.774 181.921 ;
     RECT  2.304 181.651 3.402 181.949 ;
     RECT  121.215 179.717 121.497 182.011 ;
     RECT  4.284 181.651 4.518 182.039 ;
     RECT  121.104 182.011 121.497 182.048 ;
     RECT  4.284 182.039 4.374 182.075 ;
     RECT  92.376 181.139 92.394 182.075 ;
     RECT  4.356 182.075 4.374 182.111 ;
     RECT  90.648 181.921 90.738 182.111 ;
     RECT  94.068 181.813 94.806 182.119 ;
     RECT  95.544 181.499 98.19 182.119 ;
     RECT  90.648 182.111 90.666 182.219 ;
     RECT  122.544 182.011 122.562 182.219 ;
     RECT  94.068 182.119 98.19 182.281 ;
     RECT  99.18 181.769 103.95 182.281 ;
     RECT  123.624 181.921 162.882 182.309 ;
     RECT  110.415 180.797 111.186 182.317 ;
     RECT  162.756 182.309 162.774 182.345 ;
     RECT  94.068 182.281 103.95 182.347 ;
     RECT  0.18 181.613 0.342 182.381 ;
     RECT  0.18 182.381 0.198 182.477 ;
     RECT  2.304 181.949 3.114 182.539 ;
     RECT  93.42 182.347 103.95 182.551 ;
     RECT  104.868 181.921 109.386 182.551 ;
     RECT  110.304 182.317 111.186 182.551 ;
     RECT  2.268 182.539 3.114 182.579 ;
     RECT  104.868 182.551 111.186 182.651 ;
     RECT  2.268 182.579 3.042 182.687 ;
     RECT  92.916 182.551 103.95 182.731 ;
     RECT  104.868 182.651 108.846 182.731 ;
     RECT  2.415 182.687 3.042 182.759 ;
     RECT  92.916 182.731 108.846 182.849 ;
     RECT  109.98 182.651 111.186 182.849 ;
     RECT  109.98 182.849 111.114 182.921 ;
     RECT  3.888 183.001 3.906 183.091 ;
     RECT  92.916 182.849 93.438 183.091 ;
     RECT  92.88 183.091 93.438 183.119 ;
     RECT  123.624 182.309 161.802 183.163 ;
     RECT  123.624 183.163 162.054 183.235 ;
     RECT  123.624 183.235 162.126 183.271 ;
     RECT  3.888 183.091 4.122 183.299 ;
     RECT  109.98 182.921 110.79 183.299 ;
     RECT  92.88 183.119 93.042 183.389 ;
     RECT  109.98 183.299 110.754 183.461 ;
     RECT  114.552 183.361 114.57 183.461 ;
     RECT  95.76 182.849 108.846 183.505 ;
     RECT  123.624 183.271 162.63 183.533 ;
     RECT  2.415 182.759 2.97 183.541 ;
     RECT  124.884 183.533 162.63 183.541 ;
     RECT  4.104 183.299 4.122 183.569 ;
     RECT  94.215 182.849 94.662 183.695 ;
     RECT  109.98 183.461 110.697 183.731 ;
     RECT  95.76 183.505 108.882 183.739 ;
     RECT  124.884 183.541 162.846 183.767 ;
     RECT  95.76 183.739 108.954 183.775 ;
     RECT  95.76 183.775 109.602 183.811 ;
     RECT  95.436 183.811 109.602 183.821 ;
     RECT  2.415 183.541 3.15 183.839 ;
     RECT  95.436 183.821 108.954 183.883 ;
     RECT  90.648 183.811 90.666 183.929 ;
     RECT  95.364 183.883 108.954 183.929 ;
     RECT  95.4 183.929 108.846 184.109 ;
     RECT  123.624 183.533 124.074 184.747 ;
     RECT  123.624 184.747 124.11 184.855 ;
     RECT  94.215 183.695 94.497 184.891 ;
     RECT  95.4 184.109 108.522 184.891 ;
     RECT  123.624 184.855 124.146 185.017 ;
     RECT  124.92 183.767 162.846 185.017 ;
     RECT  94.215 184.891 108.522 185.261 ;
     RECT  95.4 185.261 108.522 185.279 ;
     RECT  122.58 185.275 122.598 185.323 ;
     RECT  123.624 185.017 162.846 185.323 ;
     RECT  122.58 185.323 162.846 185.549 ;
     RECT  123.12 185.549 162.846 185.819 ;
     RECT  95.4 185.279 108.342 186.359 ;
     RECT  123.372 185.819 162.846 186.503 ;
     RECT  123.372 186.503 162.234 186.673 ;
     RECT  123.192 186.673 162.234 186.709 ;
     RECT  122.868 186.709 162.234 186.745 ;
     RECT  95.796 186.359 108.342 186.809 ;
     RECT  95.832 186.809 108.342 186.899 ;
     RECT  122.616 186.745 162.234 186.907 ;
     RECT  122.436 186.907 162.234 186.971 ;
     RECT  95.832 186.899 108.306 187.439 ;
     RECT  95.832 187.439 108.234 187.517 ;
     RECT  122.76 186.971 162.234 187.709 ;
     RECT  123.372 187.709 162.234 187.825 ;
     RECT  122.616 187.717 122.634 188.093 ;
     RECT  123.372 187.825 162.882 188.095 ;
     RECT  123.372 188.095 162.99 188.131 ;
     RECT  95.868 187.517 108.234 188.443 ;
     RECT  95.688 188.443 108.234 188.519 ;
     RECT  123.372 188.131 163.53 188.527 ;
     RECT  123.012 188.527 163.53 188.555 ;
     RECT  123.012 188.555 162.234 188.825 ;
     RECT  121.215 182.048 121.497 188.869 ;
     RECT  121.215 188.869 122.13 188.941 ;
     RECT  121.215 188.941 122.31 189.059 ;
     RECT  123.084 188.825 162.234 189.445 ;
     RECT  162.972 188.555 163.53 189.445 ;
     RECT  95.868 188.519 108.234 189.751 ;
     RECT  95.76 189.751 108.234 189.835 ;
     RECT  121.215 189.059 122.13 189.835 ;
     RECT  123.084 189.445 163.53 189.877 ;
     RECT  95.616 189.835 108.234 189.905 ;
     RECT  121.215 189.835 122.202 190.021 ;
     RECT  123.048 189.877 163.53 190.021 ;
     RECT  96.12 189.905 108.234 190.049 ;
     RECT  96.12 190.049 107.694 190.553 ;
     RECT  96.12 190.553 107.082 190.679 ;
     RECT  96.912 190.679 107.082 191.093 ;
     RECT  121.215 190.021 163.53 191.219 ;
     RECT  121.215 191.219 122.454 191.327 ;
     RECT  122.436 191.327 122.454 191.405 ;
     RECT  97.128 191.093 107.082 191.759 ;
     RECT  97.128 191.759 106.29 191.831 ;
     RECT  123.3 191.219 163.53 192.037 ;
     RECT  97.128 191.831 106.11 192.065 ;
     RECT  107.064 191.759 107.082 192.101 ;
     RECT  97.164 192.065 106.11 192.299 ;
     RECT  97.164 192.299 106.038 192.569 ;
     RECT  97.416 192.569 99.897 192.641 ;
     RECT  123.084 192.037 163.53 192.653 ;
     RECT  97.416 192.641 98.37 192.713 ;
     RECT  97.416 192.713 97.578 192.839 ;
     RECT  98.352 192.713 98.37 192.839 ;
     RECT  101.016 192.569 106.038 192.839 ;
     RECT  103.572 192.839 106.038 192.875 ;
     RECT  123.372 192.653 163.53 192.875 ;
     RECT  123.444 192.875 163.53 192.883 ;
     RECT  101.016 192.839 101.862 192.911 ;
     RECT  101.16 192.911 101.574 192.983 ;
     RECT  101.16 192.983 101.178 193.019 ;
     RECT  103.608 192.875 105.714 193.019 ;
     RECT  123.444 192.883 163.566 193.019 ;
     RECT  119.376 192.667 119.394 193.099 ;
     RECT  103.608 193.019 105.297 193.109 ;
     RECT  103.608 193.109 103.626 193.145 ;
     RECT  123.984 193.019 163.566 193.153 ;
     RECT  119.196 193.099 119.394 193.289 ;
     RECT  119.196 193.289 119.214 193.379 ;
     RECT  123.984 193.153 163.602 193.765 ;
     RECT  164.415 180.689 164.697 193.765 ;
     RECT  123.984 193.765 164.697 193.915 ;
     RECT  123.408 193.915 164.697 193.991 ;
     RECT  123.984 193.991 164.697 194.189 ;
     RECT  123.984 194.189 163.638 194.225 ;
     RECT  123.984 194.225 163.602 194.729 ;
     RECT  123.984 194.729 163.494 194.881 ;
     RECT  123.84 194.881 163.494 194.923 ;
     RECT  123.264 194.923 163.494 195.179 ;
     RECT  123.264 195.179 163.458 195.269 ;
     RECT  123.264 195.269 163.35 195.499 ;
     RECT  122.652 195.499 163.35 195.611 ;
     RECT  122.832 195.611 163.35 195.683 ;
     RECT  122.832 195.683 122.85 195.809 ;
     RECT  123.696 195.683 163.35 195.989 ;
     RECT  124.128 195.989 163.35 196.925 ;
     RECT  124.164 196.925 163.35 197.465 ;
     RECT  124.164 197.465 124.182 197.807 ;
     RECT  124.956 197.465 163.35 198.121 ;
     RECT  124.956 198.121 163.386 198.355 ;
     RECT  124.308 198.355 163.386 198.509 ;
     RECT  124.308 198.509 162.882 198.815 ;
     RECT  124.308 198.815 162.162 200.129 ;
     RECT  124.308 200.129 162.018 200.165 ;
     RECT  124.848 200.165 162.018 200.309 ;
     RECT  125.028 200.309 162.018 200.399 ;
     RECT  125.028 200.399 161.982 200.939 ;
     RECT  125.028 200.939 128.286 201.217 ;
     RECT  124.992 201.217 128.286 201.865 ;
     RECT  129.024 200.939 161.874 201.865 ;
     RECT  124.992 201.865 161.874 202.171 ;
     RECT  124.992 202.171 161.91 202.397 ;
     RECT  125.532 202.397 161.91 202.433 ;
     RECT  125.532 202.433 161.802 202.877 ;
     RECT  125.64 202.877 161.802 203.791 ;
     RECT  125.496 203.791 161.802 204.025 ;
     RECT  125.316 204.025 161.802 204.061 ;
     RECT  125.1 204.061 161.802 204.325 ;
     RECT  124.956 204.325 161.802 204.365 ;
     RECT  125.316 204.365 161.802 205.141 ;
     RECT  125.244 205.141 161.802 205.375 ;
     RECT  124.668 205.375 161.802 205.529 ;
     RECT  124.668 205.529 161.766 205.757 ;
     RECT  124.776 205.757 161.766 205.943 ;
     RECT  157.32 205.943 161.766 205.979 ;
     RECT  124.776 205.943 156.546 206.645 ;
     RECT  125.1 206.645 156.546 206.761 ;
     RECT  157.572 205.979 161.766 206.761 ;
     RECT  125.1 206.761 161.766 207.959 ;
     RECT  124.992 208.069 125.01 208.109 ;
     RECT  125.784 207.959 161.766 208.229 ;
     RECT  126.144 208.229 161.766 209.317 ;
     RECT  126 209.317 161.766 209.461 ;
     RECT  125.784 209.461 161.766 209.731 ;
     RECT  124.848 209.821 124.866 209.885 ;
     RECT  125.604 209.731 161.766 210.001 ;
     RECT  124.956 210.001 161.766 210.119 ;
     RECT  124.956 210.119 161.298 213.097 ;
     RECT  124.884 213.097 161.298 213.431 ;
     RECT  124.884 213.431 130.662 213.725 ;
     RECT  125.568 213.725 130.662 213.971 ;
     RECT  131.76 213.431 161.298 214.205 ;
     RECT  125.82 213.971 130.662 214.285 ;
     RECT  131.76 214.205 154.638 214.285 ;
     RECT  125.82 214.285 154.638 214.891 ;
     RECT  125.244 214.891 154.638 214.951 ;
     RECT  155.448 214.205 161.298 214.951 ;
     RECT  125.244 214.951 161.298 214.979 ;
     RECT  125.244 214.979 160.794 215.591 ;
     RECT  125.244 215.591 156.186 215.825 ;
     RECT  125.748 215.825 156.186 215.861 ;
     RECT  126 215.861 156.186 216.373 ;
     RECT  157.14 215.591 160.794 216.373 ;
     RECT  126 216.373 160.794 216.599 ;
     RECT  126 216.599 160.326 217.409 ;
     RECT  126 217.409 160.29 217.949 ;
     RECT  126 217.949 159.822 218.021 ;
     RECT  126 218.021 159.786 218.057 ;
     RECT  129.096 218.057 159.786 218.219 ;
     RECT  158.472 218.219 159.786 218.255 ;
     RECT  126 218.057 128.214 218.291 ;
     RECT  129.096 218.219 157.734 218.621 ;
     RECT  158.472 218.255 159.297 218.765 ;
     RECT  126 218.291 126.897 218.867 ;
     RECT  131.724 218.621 157.734 218.867 ;
     RECT  127.62 218.291 128.214 218.923 ;
     RECT  129.096 218.621 130.626 218.923 ;
     RECT  131.904 218.867 157.734 219.181 ;
     RECT  131.904 219.181 157.95 219.407 ;
     RECT  127.62 218.923 130.626 219.451 ;
     RECT  127.62 219.451 131.022 219.685 ;
     RECT  131.904 219.407 157.878 219.685 ;
     RECT  126.615 218.867 126.897 220.027 ;
     RECT  127.62 219.685 157.878 220.027 ;
     RECT  126.615 220.027 157.878 220.289 ;
     RECT  126.615 220.289 127.638 220.379 ;
     RECT  128.376 220.289 157.878 220.379 ;
     RECT  128.376 220.379 157.734 220.487 ;
     RECT  126.615 220.379 127.494 220.523 ;
     RECT  128.376 220.487 157.662 220.649 ;
     RECT  128.952 220.649 157.662 220.919 ;
     RECT  128.952 220.919 157.446 220.991 ;
     RECT  128.952 220.991 157.302 221.027 ;
     RECT  128.952 221.027 157.194 221.459 ;
     RECT  131.076 221.459 157.194 221.531 ;
     RECT  128.952 221.459 130.266 221.567 ;
     RECT  131.076 221.531 156.114 221.603 ;
     RECT  156.888 221.531 157.194 221.603 ;
     RECT  128.952 221.567 130.23 221.729 ;
     RECT  129.672 221.729 129.906 221.801 ;
     RECT  131.076 221.603 155.898 222.385 ;
     RECT  131.076 222.385 155.97 222.539 ;
     RECT  131.076 222.539 155.898 222.809 ;
     RECT  131.076 222.809 131.094 222.845 ;
     RECT  131.868 222.809 155.646 222.845 ;
     RECT  131.94 222.845 155.61 222.881 ;
     RECT  132.015 222.881 155.61 222.917 ;
     RECT  157.176 221.603 157.194 223.079 ;
     RECT  132.015 222.917 155.358 223.187 ;
     RECT  132.015 223.187 154.278 223.229 ;
     RECT  155.016 223.187 155.358 223.349 ;
     RECT  155.088 223.349 155.358 223.385 ;
     RECT  155.088 223.385 155.106 223.457 ;
     RECT  132.015 223.229 154.206 224.167 ;
     RECT  132.015 224.167 154.314 224.311 ;
     RECT  132.015 224.311 154.782 224.429 ;
     RECT  132.015 224.429 154.386 225.149 ;
     RECT  133.38 225.149 154.386 225.391 ;
     RECT  133.38 225.391 154.89 225.509 ;
     RECT  133.38 225.509 154.638 225.629 ;
     RECT  134.784 225.629 154.638 226.049 ;
     RECT  132.015 225.149 132.297 226.129 ;
     RECT  133.38 225.629 134.046 226.129 ;
     RECT  134.784 226.049 154.17 226.355 ;
     RECT  134.784 226.355 153.897 226.463 ;
     RECT  132.015 226.129 134.046 226.561 ;
     RECT  134.784 226.463 152.838 226.561 ;
     RECT  132.015 226.561 152.838 226.589 ;
     RECT  153.615 226.463 153.897 227.479 ;
     RECT  132.015 226.589 152.802 227.515 ;
     RECT  153.54 227.479 153.897 227.515 ;
     RECT  154.836 227.821 154.854 227.939 ;
     RECT  132.015 227.515 153.897 227.975 ;
     RECT  132.015 227.975 132.822 228.011 ;
     RECT  133.56 227.975 153.897 228.011 ;
     RECT  133.812 228.011 153.897 228.019 ;
     RECT  133.812 228.019 154.494 228.047 ;
     RECT  134.244 228.047 154.494 228.209 ;
     RECT  134.568 228.209 154.494 228.389 ;
     RECT  134.604 228.389 154.494 228.659 ;
     RECT  134.604 228.659 153.897 229.019 ;
     RECT  153 229.019 153.897 229.055 ;
     RECT  134.604 229.019 152.046 229.127 ;
     RECT  134.604 229.127 152.01 229.147 ;
     RECT  134.388 229.147 152.01 229.973 ;
     RECT  153.615 229.055 153.897 229.981 ;
     RECT  152.928 229.981 153.897 230.099 ;
     RECT  136.8 229.973 152.01 230.135 ;
     RECT  136.872 230.135 152.01 230.215 ;
     RECT  136.872 230.215 152.514 230.369 ;
     RECT  134.388 229.973 136.026 230.875 ;
     RECT  136.872 230.369 151.83 230.875 ;
     RECT  134.388 230.875 151.83 230.917 ;
     RECT  134.28 230.917 151.83 230.957 ;
     RECT  134.532 230.957 151.83 231.089 ;
     RECT  134.604 231.089 151.83 231.437 ;
     RECT  135.144 231.437 151.83 231.449 ;
     RECT  135.144 231.449 151.614 231.869 ;
     RECT  135.144 231.869 141.462 231.899 ;
     RECT  142.56 231.869 151.614 231.899 ;
     RECT  135.144 231.899 141.174 231.989 ;
     RECT  142.56 231.899 151.542 231.989 ;
     RECT  142.56 231.989 151.218 232.609 ;
     RECT  142.092 232.609 151.218 232.681 ;
     RECT  135.252 231.989 141.174 232.915 ;
     RECT  141.984 232.681 151.218 232.915 ;
     RECT  135.108 232.915 151.218 232.951 ;
     RECT  135.108 232.951 151.938 233.645 ;
     RECT  135.468 233.645 151.938 233.689 ;
     RECT  135.468 233.689 152.37 233.879 ;
     RECT  135.468 233.879 151.938 234.023 ;
     RECT  135.468 234.023 151.83 234.149 ;
     RECT  135.468 234.149 151.434 234.185 ;
     RECT  135.468 234.185 151.29 234.455 ;
     RECT  142.056 234.455 151.29 234.689 ;
     RECT  142.056 234.689 150.822 234.797 ;
     RECT  135.468 234.455 141.318 234.967 ;
     RECT  135.252 234.967 141.318 235.111 ;
     RECT  135.144 235.111 141.318 235.195 ;
     RECT  135 235.195 141.318 235.201 ;
     RECT  142.056 234.797 149.346 235.201 ;
     RECT  132.015 228.011 132.297 235.435 ;
     RECT  133.056 232.501 133.074 235.435 ;
     RECT  135 235.201 149.346 235.499 ;
     RECT  139.572 235.499 149.346 235.615 ;
     RECT  150.084 234.797 150.822 235.615 ;
     RECT  139.572 235.615 150.822 235.651 ;
     RECT  132.015 235.435 133.074 235.661 ;
     RECT  135 235.499 138.798 235.997 ;
     RECT  135.252 235.997 138.798 236.219 ;
     RECT  135.468 236.219 138.798 236.347 ;
     RECT  139.572 235.651 150.858 236.347 ;
     RECT  135.468 236.347 150.858 236.417 ;
     RECT  135.54 236.417 150.858 236.461 ;
     RECT  151.596 236.425 151.614 236.461 ;
     RECT  135.54 236.461 151.614 236.489 ;
     RECT  136.404 236.489 151.614 236.579 ;
     RECT  136.476 236.579 151.614 236.723 ;
     RECT  135.54 236.489 135.666 236.849 ;
     RECT  152.136 236.731 152.154 236.849 ;
     RECT  136.476 236.723 150.966 236.921 ;
     RECT  136.476 236.921 150.606 237.119 ;
     RECT  136.476 237.119 145.818 237.389 ;
     RECT  136.656 237.389 145.818 237.659 ;
     RECT  146.664 237.119 150.606 237.667 ;
     RECT  136.656 237.659 145.494 237.767 ;
     RECT  139.356 237.767 145.494 237.803 ;
     RECT  136.656 237.767 138.51 237.821 ;
     RECT  146.664 237.667 151.038 237.869 ;
     RECT  136.656 237.821 138.33 237.929 ;
     RECT  136.656 237.929 138.15 237.965 ;
     RECT  146.7 237.869 151.038 238.001 ;
     RECT  149.832 238.001 151.038 238.081 ;
     RECT  136.8 237.965 138.15 238.109 ;
     RECT  149.832 238.081 151.614 238.109 ;
     RECT  137.376 238.109 137.754 238.199 ;
     RECT  139.68 237.803 145.494 238.199 ;
     RECT  151.596 238.109 151.614 238.199 ;
     RECT  139.68 238.199 140.634 238.271 ;
     RECT  146.7 238.001 148.806 238.271 ;
     RECT  150.408 238.109 150.714 238.271 ;
     RECT  150.48 238.271 150.714 238.307 ;
     RECT  141.408 238.199 145.494 238.585 ;
     RECT  146.7 238.271 148.59 238.855 ;
     RECT  141.408 238.585 145.53 238.891 ;
     RECT  146.484 238.855 148.59 238.891 ;
     RECT  141.408 238.891 148.59 239.009 ;
     RECT  140.004 238.271 140.634 239.017 ;
     RECT  140.004 239.017 140.67 239.089 ;
     RECT  139.824 239.089 140.67 239.161 ;
     RECT  141.408 239.009 146.43 239.161 ;
     RECT  147.42 239.009 148.497 239.189 ;
     RECT  148.176 239.189 148.497 239.315 ;
     RECT  139.824 239.161 146.43 239.855 ;
     RECT  146.412 239.855 146.43 239.963 ;
     RECT  139.824 239.855 145.53 240.475 ;
     RECT  139.68 240.475 145.53 241.285 ;
     RECT  139.68 241.285 145.566 241.555 ;
     RECT  139.68 241.555 145.818 241.583 ;
     RECT  141.12 241.583 145.818 241.591 ;
     RECT  141.12 241.591 146.142 241.781 ;
     RECT  141.12 241.781 145.35 241.817 ;
     RECT  141.12 241.817 145.17 241.889 ;
     RECT  141.12 241.889 144.81 242.087 ;
     RECT  141.516 242.087 144.81 242.123 ;
     RECT  141.516 242.123 141.534 242.249 ;
     RECT  142.488 242.123 144.81 242.249 ;
     RECT  142.488 242.249 143.097 242.285 ;
     RECT  143.928 242.249 144.414 242.285 ;
     RECT  143.928 242.285 143.946 242.321 ;
     RECT  142.524 242.285 143.097 242.393 ;
     RECT  142.632 242.393 143.097 242.429 ;
     RECT  129.672 221.801 129.69 274.891 ;
     RECT  129.672 274.891 130.158 274.928 ;
     RECT  129.672 274.928 129.87 275.261 ;
     RECT  129.672 275.261 129.69 288.689 ;
     RECT  2.415 183.839 2.697 369.107 ;
     RECT  7.815 2.413 8.097 369.107 ;
     RECT  13.215 2.413 13.497 369.107 ;
     RECT  18.615 2.413 18.897 369.107 ;
     RECT  24.015 2.413 24.297 369.107 ;
     RECT  29.415 2.413 29.697 369.107 ;
     RECT  34.815 2.413 35.097 369.107 ;
     RECT  40.215 2.413 40.497 369.107 ;
     RECT  45.615 2.413 45.897 369.107 ;
     RECT  51.015 2.413 51.297 369.107 ;
     RECT  56.415 2.413 56.697 369.107 ;
     RECT  61.815 2.413 62.097 369.107 ;
     RECT  67.215 2.413 67.497 369.107 ;
     RECT  72.615 2.413 72.897 369.107 ;
     RECT  78.015 2.413 78.297 369.107 ;
     RECT  83.415 2.413 83.697 369.107 ;
     RECT  88.815 170.699 89.097 369.107 ;
     RECT  94.215 185.261 94.497 369.107 ;
     RECT  99.615 192.641 99.897 369.107 ;
     RECT  105.015 193.109 105.297 369.107 ;
     RECT  110.415 183.731 110.697 369.107 ;
     RECT  115.815 176.957 116.097 369.107 ;
     RECT  121.215 191.327 121.497 369.107 ;
     RECT  126.615 220.523 126.897 369.107 ;
     RECT  132.015 235.661 132.297 369.107 ;
     RECT  137.415 238.199 137.697 369.107 ;
     RECT  142.815 242.429 143.097 369.107 ;
     RECT  148.215 239.315 148.497 369.107 ;
     RECT  153.615 230.099 153.897 369.107 ;
     RECT  159.015 218.765 159.297 369.107 ;
     RECT  164.415 194.189 164.697 369.107 ;
     RECT  169.815 2.413 170.097 369.107 ;
     RECT  175.215 171.248 175.497 369.107 ;
     RECT  180.615 2.413 180.897 369.107 ;
     RECT  186.015 171.248 186.297 369.107 ;
     RECT  191.415 2.413 191.697 369.107 ;
     RECT  196.815 171.248 197.097 369.107 ;
     RECT  202.215 2.413 202.497 369.107 ;
     RECT  207.615 171.248 207.897 369.107 ;
     RECT  213.015 2.413 213.297 369.107 ;
     RECT  218.415 171.248 218.697 369.107 ;
     RECT  223.815 2.413 224.097 369.107 ;
     RECT  229.215 171.248 229.497 369.107 ;
     RECT  234.615 2.413 234.897 369.107 ;
     RECT  240.015 171.248 240.297 369.107 ;
     RECT  245.415 180.689 245.697 369.107 ;
     RECT  2.415 369.107 2.505 369.377 ;
     RECT  7.815 369.107 7.905 369.377 ;
     RECT  13.215 369.107 13.305 369.377 ;
     RECT  18.615 369.107 18.705 369.377 ;
     RECT  24.015 369.107 24.105 369.377 ;
     RECT  29.415 369.107 29.505 369.377 ;
     RECT  34.815 369.107 34.905 369.377 ;
     RECT  40.215 369.107 40.305 369.377 ;
     RECT  45.615 369.107 45.705 369.377 ;
     RECT  51.015 369.107 51.105 369.377 ;
     RECT  56.415 369.107 56.505 369.377 ;
     RECT  61.815 369.107 61.905 369.377 ;
     RECT  67.215 369.107 67.305 369.377 ;
     RECT  72.615 369.107 72.705 369.377 ;
     RECT  78.015 369.107 78.105 369.377 ;
     RECT  83.415 369.107 83.505 369.377 ;
     RECT  88.815 369.107 88.905 369.377 ;
     RECT  94.215 369.107 94.305 369.377 ;
     RECT  99.615 369.107 99.705 369.377 ;
     RECT  105.015 369.107 105.105 369.377 ;
     RECT  110.415 369.107 110.505 369.377 ;
     RECT  115.815 369.107 115.905 369.377 ;
     RECT  121.215 369.107 121.305 369.377 ;
     RECT  126.615 369.107 126.705 369.377 ;
     RECT  132.015 369.107 132.105 369.377 ;
     RECT  137.415 369.107 137.505 369.377 ;
     RECT  142.815 369.107 142.905 369.377 ;
     RECT  148.215 369.107 148.305 369.377 ;
     RECT  153.615 369.107 153.705 369.377 ;
     RECT  159.015 369.107 159.105 369.377 ;
     RECT  164.415 369.107 164.505 369.377 ;
     RECT  169.815 369.107 169.905 369.377 ;
     RECT  175.215 369.107 175.305 369.377 ;
     RECT  180.615 369.107 180.705 369.377 ;
     RECT  186.015 369.107 186.105 369.377 ;
     RECT  191.415 369.107 191.505 369.377 ;
     RECT  196.815 369.107 196.905 369.377 ;
     RECT  202.215 369.107 202.305 369.377 ;
     RECT  207.615 369.107 207.705 369.377 ;
     RECT  213.015 369.107 213.105 369.377 ;
     RECT  218.415 369.107 218.505 369.377 ;
     RECT  223.815 369.107 223.905 369.377 ;
     RECT  229.215 369.107 229.305 369.377 ;
     RECT  234.615 369.107 234.705 369.377 ;
     RECT  240.015 369.107 240.105 369.377 ;
     RECT  245.415 369.107 245.505 369.377 ;
     RECT  133.056 235.661 133.074 369.917 ;
     RECT  130.32 288.841 130.338 371.501 ;
    LAYER M4 ;
     RECT  0.06 159.6 0.133 160.008 ;
     RECT  0.133 159.6 0.137 160.104 ;
     RECT  0.06 179.568 0.173 182.568 ;
     RECT  0.173 179.664 0.569 182.568 ;
     RECT  0.137 159.696 2.408 160.104 ;
     RECT  0.569 179.856 2.408 182.568 ;
     RECT  2.408 2.148 2.512 369.372 ;
     RECT  2.512 2.418 2.704 369.102 ;
     RECT  2.704 159.936 2.873 160.008 ;
     RECT  2.704 180.72 2.945 182.376 ;
     RECT  2.873 159.984 3.377 160.008 ;
     RECT  2.945 180.72 4.097 181.896 ;
     RECT  4.097 181.104 4.313 181.896 ;
     RECT  7.808 2.148 7.912 369.372 ;
     RECT  7.912 2.418 8.104 369.102 ;
     RECT  13.208 2.148 13.312 369.372 ;
     RECT  13.312 2.418 13.504 369.102 ;
     RECT  18.608 2.148 18.712 369.372 ;
     RECT  18.712 2.418 18.904 369.102 ;
     RECT  24.008 2.148 24.112 369.372 ;
     RECT  24.112 2.418 24.304 369.102 ;
     RECT  29.408 2.148 29.512 369.372 ;
     RECT  29.512 2.418 29.704 369.102 ;
     RECT  34.808 2.148 34.912 369.372 ;
     RECT  34.912 2.418 35.104 369.102 ;
     RECT  40.208 2.148 40.312 369.372 ;
     RECT  40.312 2.418 40.504 369.102 ;
     RECT  45.608 2.148 45.712 369.372 ;
     RECT  45.712 2.418 45.904 369.102 ;
     RECT  51.008 2.148 51.112 369.372 ;
     RECT  51.112 2.418 51.304 369.102 ;
     RECT  56.408 2.148 56.512 369.372 ;
     RECT  56.512 2.418 56.704 369.102 ;
     RECT  61.808 2.148 61.912 369.372 ;
     RECT  61.912 2.418 62.104 369.102 ;
     RECT  67.208 2.148 67.312 369.372 ;
     RECT  67.312 2.418 67.504 369.102 ;
     RECT  72.608 2.148 72.712 369.372 ;
     RECT  72.712 2.418 72.904 369.102 ;
     RECT  78.008 2.148 78.112 369.372 ;
     RECT  78.112 2.418 78.304 369.102 ;
     RECT  83.408 2.148 83.512 369.372 ;
     RECT  83.512 2.418 83.704 369.102 ;
     RECT  88.808 2.148 88.912 369.372 ;
     RECT  88.912 2.418 89.104 369.102 ;
     RECT  92.869 181.008 93.397 181.032 ;
     RECT  93.949 169.872 94.165 169.896 ;
     RECT  94.165 169.872 94.208 170.232 ;
     RECT  93.661 176.112 94.208 176.136 ;
     RECT  93.625 179.184 94.208 179.208 ;
     RECT  93.397 180.336 94.208 181.032 ;
     RECT  93.409 182.352 94.208 182.376 ;
     RECT  94.208 2.148 94.312 369.372 ;
     RECT  94.312 2.418 94.504 369.102 ;
     RECT  94.504 178.368 94.643 181.272 ;
     RECT  94.504 175.584 94.673 177.288 ;
     RECT  94.673 176.112 94.691 177.288 ;
     RECT  94.691 176.112 94.717 177.24 ;
     RECT  94.643 179.28 95.177 181.272 ;
     RECT  95.177 180.144 95.213 181.272 ;
     RECT  94.504 172.32 95.497 172.344 ;
     RECT  94.504 168.096 95.677 168.12 ;
     RECT  94.717 176.592 95.677 177.24 ;
     RECT  94.504 170.208 95.701 170.232 ;
     RECT  95.497 172.32 95.701 172.92 ;
     RECT  95.677 176.592 95.701 177.768 ;
     RECT  95.213 180.192 95.701 181.272 ;
     RECT  94.504 182.304 95.701 182.472 ;
     RECT  95.701 176.592 95.717 178.584 ;
     RECT  95.701 171.504 95.747 172.92 ;
     RECT  95.701 180.192 95.747 182.472 ;
     RECT  95.497 166.416 95.749 166.44 ;
     RECT  95.677 167.856 95.749 168.12 ;
     RECT  95.677 188.448 95.749 188.472 ;
     RECT  95.717 177.744 95.761 178.584 ;
     RECT  95.747 171.504 95.788 171.528 ;
     RECT  95.749 187.488 95.795 188.472 ;
     RECT  95.749 166.416 95.821 168.696 ;
     RECT  95.701 170.16 95.821 170.328 ;
     RECT  95.747 180.528 95.861 182.472 ;
     RECT  95.795 187.488 95.861 187.512 ;
     RECT  95.605 189.84 96.065 189.864 ;
     RECT  96.065 189.84 96.149 190.44 ;
     RECT  96.149 189.84 96.325 189.864 ;
     RECT  94.504 183.888 96.361 183.912 ;
     RECT  94.504 185.232 96.361 185.256 ;
     RECT  96.361 183.888 96.401 185.256 ;
     RECT  96.325 189.552 96.901 189.864 ;
     RECT  96.401 183.888 96.905 184.824 ;
     RECT  96.037 175.152 96.941 175.176 ;
     RECT  96.865 188.064 96.973 188.088 ;
     RECT  96.901 165.168 96.988 165.192 ;
     RECT  95.761 178.56 97.009 178.584 ;
     RECT  95.821 166.416 97.085 170.328 ;
     RECT  97.085 166.992 97.157 170.328 ;
     RECT  97.009 177.984 97.189 178.584 ;
     RECT  97.157 166.992 97.193 168.552 ;
     RECT  96.973 187.296 97.225 188.088 ;
     RECT  96.901 189.216 97.225 189.864 ;
     RECT  95.861 180.96 97.229 182.472 ;
     RECT  97.157 169.776 97.369 170.328 ;
     RECT  97.189 177.984 97.369 178.68 ;
     RECT  97.225 187.296 97.429 189.864 ;
     RECT  97.405 192.672 97.429 192.696 ;
     RECT  95.717 176.592 97.437 176.616 ;
     RECT  97.429 187.296 97.475 189.912 ;
     RECT  97.429 192.048 97.489 192.696 ;
     RECT  96.905 183.888 97.517 184.344 ;
     RECT  97.333 174.192 97.523 174.744 ;
     RECT  97.475 187.296 97.589 188.328 ;
     RECT  97.475 189.552 97.589 189.912 ;
     RECT  97.589 188.304 97.625 188.328 ;
     RECT  97.369 177.744 97.661 178.68 ;
     RECT  95.747 172.896 97.693 172.92 ;
     RECT  97.081 179.856 97.693 179.88 ;
     RECT  97.229 180.96 97.693 180.984 ;
     RECT  97.661 177.792 97.717 178.68 ;
     RECT  97.693 179.856 97.717 180.984 ;
     RECT  97.523 174.72 97.733 174.744 ;
     RECT  97.676 176.112 97.763 176.136 ;
     RECT  97.717 177.792 97.763 180.984 ;
     RECT  97.549 183.552 97.763 183.624 ;
     RECT  97.693 172.896 97.805 173.208 ;
     RECT  97.229 182.304 97.985 182.472 ;
     RECT  97.117 161.856 98.017 161.88 ;
     RECT  97.441 185.808 98.053 185.832 ;
     RECT  97.763 177.792 98.273 180.84 ;
     RECT  98.017 164.064 98.413 164.088 ;
     RECT  98.017 175.056 98.561 175.704 ;
     RECT  98.273 177.792 98.561 177.816 ;
     RECT  97.193 167.856 98.588 167.88 ;
     RECT  97.589 189.888 98.917 189.912 ;
     RECT  97.985 182.304 99.061 182.328 ;
     RECT  98.413 163.632 99.097 164.088 ;
     RECT  97.873 165.648 99.097 165.864 ;
     RECT  98.273 178.896 99.157 180.84 ;
     RECT  99.061 182.304 99.157 182.568 ;
     RECT  97.763 183.6 99.241 183.624 ;
     RECT  98.017 184.656 99.241 184.68 ;
     RECT  97.369 169.776 99.313 171.096 ;
     RECT  98.053 185.664 99.349 185.832 ;
     RECT  97.589 187.296 99.421 187.32 ;
     RECT  99.097 163.632 99.493 164.28 ;
     RECT  99.097 165.6 99.493 165.864 ;
     RECT  98.588 166.896 99.493 167.88 ;
     RECT  99.313 169.344 99.493 171.096 ;
     RECT  99.421 187.248 99.565 187.32 ;
     RECT  98.953 160.176 99.608 160.2 ;
     RECT  98.017 161.808 99.608 161.88 ;
     RECT  99.493 162.96 99.608 164.28 ;
     RECT  99.493 165.36 99.608 165.864 ;
     RECT  99.493 166.896 99.608 171.096 ;
     RECT  97.805 172.896 99.608 173.16 ;
     RECT  99.421 174.24 99.608 174.264 ;
     RECT  98.561 175.68 99.608 175.704 ;
     RECT  99.205 176.736 99.608 177.528 ;
     RECT  99.157 178.896 99.608 182.568 ;
     RECT  99.241 183.6 99.608 184.68 ;
     RECT  99.349 185.664 99.608 186.216 ;
     RECT  99.565 187.248 99.608 187.464 ;
     RECT  98.917 189.6 99.608 189.912 ;
     RECT  97.489 192.048 99.608 192.072 ;
     RECT  99.608 2.148 99.712 369.372 ;
     RECT  99.712 2.418 99.904 369.102 ;
     RECT  99.904 173.136 99.965 173.16 ;
     RECT  99.904 181.632 100.073 185.88 ;
     RECT  100.073 181.632 100.145 182.088 ;
     RECT  99.904 177.216 100.181 180.456 ;
     RECT  100.073 183.168 100.289 185.88 ;
     RECT  99.904 167.952 100.307 168.84 ;
     RECT  99.904 170.208 100.355 171.624 ;
     RECT  99.904 186.912 100.355 187.8 ;
     RECT  99.904 160.176 100.361 160.2 ;
     RECT  99.904 161.856 100.361 164.232 ;
     RECT  100.355 171.6 100.361 171.624 ;
     RECT  99.904 189.6 100.397 192.072 ;
     RECT  100.361 162.48 100.433 164.232 ;
     RECT  100.289 183.408 100.433 185.88 ;
     RECT  100.433 162.72 100.505 164.232 ;
     RECT  100.433 183.696 100.541 185.88 ;
     RECT  100.355 187.248 100.613 187.8 ;
     RECT  100.397 189.6 100.636 191.496 ;
     RECT  100.541 183.696 100.649 185.352 ;
     RECT  99.904 175.536 100.721 175.992 ;
     RECT  100.613 187.296 100.721 187.8 ;
     RECT  100.721 175.968 100.739 175.992 ;
     RECT  100.649 184.32 100.757 185.352 ;
     RECT  100.145 181.632 100.865 181.8 ;
     RECT  100.307 168.48 100.885 168.84 ;
     RECT  100.885 168.48 100.972 170.184 ;
     RECT  100.505 162.72 100.973 162.984 ;
     RECT  99.904 165.312 100.973 165.432 ;
     RECT  100.865 181.632 100.973 181.656 ;
     RECT  100.181 177.216 101.045 179.688 ;
     RECT  100.972 168.48 101.081 169.224 ;
     RECT  101.081 168.576 101.189 169.224 ;
     RECT  100.636 189.6 101.261 189.912 ;
     RECT  101.393 176.688 101.477 176.712 ;
     RECT  101.045 177.792 101.513 179.688 ;
     RECT  100.973 165.36 101.549 165.432 ;
     RECT  100.757 185.328 101.549 185.352 ;
     RECT  100.721 187.392 101.549 187.8 ;
     RECT  100.973 162.72 101.617 162.744 ;
     RECT  101.221 174.384 101.725 174.408 ;
     RECT  101.725 173.952 101.941 174.408 ;
     RECT  101.617 162.432 101.977 162.744 ;
     RECT  100.505 164.208 101.977 164.232 ;
     RECT  101.189 168.672 102.013 169.224 ;
     RECT  101.941 173.328 102.085 174.408 ;
     RECT  102.049 167.328 102.193 167.352 ;
     RECT  102.013 168.672 102.193 169.704 ;
     RECT  101.977 162.432 102.197 164.232 ;
     RECT  102.085 173.328 102.233 174.456 ;
     RECT  101.869 188.592 102.237 188.616 ;
     RECT  101.261 189.888 102.237 189.912 ;
     RECT  100.636 190.992 102.257 191.496 ;
     RECT  102.237 188.592 102.305 189.912 ;
     RECT  101.549 165.408 102.332 165.432 ;
     RECT  102.257 190.944 102.341 191.496 ;
     RECT  102.121 172.08 102.409 172.104 ;
     RECT  102.332 165.408 102.419 166.296 ;
     RECT  100.757 184.32 102.485 184.344 ;
     RECT  101.549 187.392 102.515 187.512 ;
     RECT  102.193 167.328 102.521 169.704 ;
     RECT  102.305 188.784 102.557 189.912 ;
     RECT  102.233 173.328 102.565 174.36 ;
     RECT  102.341 191.376 102.565 191.496 ;
     RECT  102.373 192.768 102.565 192.792 ;
     RECT  102.049 181.68 102.572 181.704 ;
     RECT  102.197 163.44 102.589 164.232 ;
     RECT  102.521 169.68 102.593 169.704 ;
     RECT  102.565 191.376 102.611 192.792 ;
     RECT  102.572 181.104 102.613 181.704 ;
     RECT  102.419 165.408 102.629 165.432 ;
     RECT  102.613 180.72 102.659 181.704 ;
     RECT  102.659 180.72 102.661 181.128 ;
     RECT  101.401 182.736 102.693 182.76 ;
     RECT  102.193 175.536 102.697 175.56 ;
     RECT  102.565 173.232 102.701 174.36 ;
     RECT  102.517 170.88 102.769 170.904 ;
     RECT  102.521 167.328 102.809 168.696 ;
     RECT  102.809 168.336 102.953 168.696 ;
     RECT  102.697 175.536 102.997 176.424 ;
     RECT  102.997 175.488 103.021 176.424 ;
     RECT  101.513 177.792 103.021 179.448 ;
     RECT  102.661 180.432 103.021 181.128 ;
     RECT  102.701 173.232 103.025 173.256 ;
     RECT  103.021 177.792 103.043 181.128 ;
     RECT  102.611 191.376 103.097 192.6 ;
     RECT  103.021 175.488 103.165 176.472 ;
     RECT  102.409 172.032 103.385 172.104 ;
     RECT  102.157 160.704 103.417 160.728 ;
     RECT  103.417 160.128 103.457 160.728 ;
     RECT  102.373 185.808 103.457 185.832 ;
     RECT  103.165 175.488 103.489 176.712 ;
     RECT  102.557 189.456 103.561 189.912 ;
     RECT  103.489 175.392 103.564 176.712 ;
     RECT  103.385 172.08 103.565 172.104 ;
     RECT  103.097 191.376 103.633 192.36 ;
     RECT  102.953 168.624 103.669 168.696 ;
     RECT  102.301 161.808 103.673 161.832 ;
     RECT  102.589 163.44 103.745 164.424 ;
     RECT  103.745 163.536 103.763 164.424 ;
     RECT  103.763 164.304 103.772 164.424 ;
     RECT  103.705 166.224 103.775 166.248 ;
     RECT  103.564 175.392 103.781 176.472 ;
     RECT  103.043 178.128 103.817 181.128 ;
     RECT  103.772 164.304 103.859 165.192 ;
     RECT  103.457 160.128 103.889 160.152 ;
     RECT  103.817 181.104 103.961 181.128 ;
     RECT  103.669 168.624 103.993 168.792 ;
     RECT  103.781 176.448 104.033 176.472 ;
     RECT  103.775 166.224 104.245 166.296 ;
     RECT  102.809 167.328 104.245 167.352 ;
     RECT  102.877 184.704 104.317 184.728 ;
     RECT  102.515 187.392 104.348 187.416 ;
     RECT  103.561 189.312 104.348 189.912 ;
     RECT  103.993 168.624 104.353 169.224 ;
     RECT  102.769 170.592 104.353 170.904 ;
     RECT  104.353 168.624 104.425 170.904 ;
     RECT  104.317 184.704 104.569 185.592 ;
     RECT  104.317 183.12 104.605 183.144 ;
     RECT  104.605 183.12 104.713 183.72 ;
     RECT  104.569 184.704 104.713 186.408 ;
     RECT  103.633 190.992 104.785 192.36 ;
     RECT  103.813 172.992 104.869 173.016 ;
     RECT  104.869 160.704 105.008 160.728 ;
     RECT  104.869 162.864 105.008 162.888 ;
     RECT  103.859 164.304 105.008 164.328 ;
     RECT  104.245 166.224 105.008 167.352 ;
     RECT  104.425 168.624 105.008 171 ;
     RECT  104.869 172.992 105.008 173.256 ;
     RECT  102.701 174.288 105.008 174.36 ;
     RECT  103.781 175.392 105.008 175.416 ;
     RECT  103.817 178.128 105.008 180.024 ;
     RECT  104.893 181.056 105.008 181.08 ;
     RECT  104.713 183.12 105.008 186.408 ;
     RECT  104.348 187.392 105.008 187.512 ;
     RECT  104.348 188.784 105.008 189.912 ;
     RECT  104.785 190.944 105.008 192.36 ;
     RECT  105.008 2.148 105.112 369.372 ;
     RECT  105.112 2.418 105.304 369.102 ;
     RECT  105.304 169.92 105.365 171 ;
     RECT  105.304 160.704 105.437 160.728 ;
     RECT  105.304 182.256 105.437 184.776 ;
     RECT  105.437 182.256 105.443 184.152 ;
     RECT  105.304 166.224 105.509 166.824 ;
     RECT  105.304 190.944 105.545 191.016 ;
     RECT  105.304 171.984 105.58 172.008 ;
     RECT  105.304 189.36 105.617 189.912 ;
     RECT  105.304 178.608 105.971 181.08 ;
     RECT  105.443 182.256 106.012 183.864 ;
     RECT  105.304 168.672 106.229 168.696 ;
     RECT  105.304 186.384 106.229 186.408 ;
     RECT  105.545 190.992 106.229 191.016 ;
     RECT  105.304 163.44 106.297 164.52 ;
     RECT  105.509 166.8 106.297 166.824 ;
     RECT  105.365 170.784 106.369 171 ;
     RECT  105.304 173.28 106.373 173.832 ;
     RECT  106.297 166.8 106.445 166.968 ;
     RECT  106.369 170.784 106.46 171.48 ;
     RECT  106.445 166.944 106.501 166.968 ;
     RECT  106.501 166.944 106.547 167.208 ;
     RECT  106.46 170.352 106.547 171.48 ;
     RECT  105.971 178.608 106.553 180.36 ;
     RECT  105.304 174.816 106.589 176.376 ;
     RECT  106.553 178.608 106.621 179.208 ;
     RECT  106.012 183.12 106.645 183.864 ;
     RECT  106.589 174.816 106.697 176.232 ;
     RECT  106.645 183.12 106.697 184.488 ;
     RECT  106.697 184.464 106.732 184.488 ;
     RECT  106.297 163.44 106.796 164.76 ;
     RECT  106.796 163.296 106.877 164.76 ;
     RECT  105.304 187.44 106.877 187.464 ;
     RECT  106.877 163.296 106.883 164.328 ;
     RECT  105.617 189.408 106.985 189.912 ;
     RECT  106.373 173.808 107.053 173.832 ;
     RECT  106.697 174.816 107.053 175.608 ;
     RECT  106.697 183.12 107.057 183.144 ;
     RECT  106.501 165.84 107.093 165.864 ;
     RECT  107.053 173.808 107.171 175.608 ;
     RECT  106.549 172.08 107.201 172.104 ;
     RECT  107.305 172.128 107.341 172.728 ;
     RECT  107.171 173.808 107.341 175.32 ;
     RECT  106.547 167.184 107.453 167.208 ;
     RECT  106.621 178.368 107.612 179.208 ;
     RECT  107.612 178.272 107.699 179.208 ;
     RECT  107.341 172.128 107.795 175.32 ;
     RECT  107.795 172.128 107.813 173.304 ;
     RECT  107.813 173.232 107.885 173.304 ;
     RECT  107.885 173.28 107.993 173.304 ;
     RECT  107.699 178.272 107.993 179.016 ;
     RECT  107.485 182.688 107.993 182.712 ;
     RECT  106.553 180.336 108.061 180.36 ;
     RECT  108.061 180.336 108.245 180.744 ;
     RECT  106.883 163.44 108.353 164.328 ;
     RECT  107.795 174.528 108.533 175.32 ;
     RECT  108.353 163.536 108.563 164.328 ;
     RECT  106.945 185.808 108.563 185.832 ;
     RECT  107.993 178.992 108.605 179.016 ;
     RECT  108.533 175.296 108.713 175.32 ;
     RECT  108.313 181.824 108.851 181.848 ;
     RECT  108.245 180.336 109.109 180.36 ;
     RECT  106.547 170.784 109.388 170.808 ;
     RECT  107.813 172.128 109.388 172.152 ;
     RECT  109.388 170.784 110.156 172.152 ;
     RECT  107.653 176.928 110.197 176.952 ;
     RECT  108.563 164.304 110.408 164.328 ;
     RECT  108.517 168.288 110.408 168.312 ;
     RECT  110.156 170.784 110.408 172.248 ;
     RECT  110.197 176.4 110.408 176.952 ;
     RECT  108.517 183.792 110.408 183.816 ;
     RECT  106.985 189.888 110.408 189.912 ;
     RECT  110.408 2.148 110.512 369.372 ;
     RECT  110.512 2.418 110.704 369.102 ;
     RECT  110.704 176.4 110.867 176.952 ;
     RECT  110.704 179.376 110.908 180.552 ;
     RECT  110.704 171.888 111.059 171.912 ;
     RECT  110.704 164.208 114.109 164.232 ;
     RECT  114.109 164.208 114.419 164.712 ;
     RECT  110.867 176.928 114.497 176.952 ;
     RECT  114.497 176.688 114.581 176.952 ;
     RECT  114.419 164.208 115.808 164.232 ;
     RECT  114.373 166.128 115.808 166.152 ;
     RECT  110.704 168.288 115.808 169.08 ;
     RECT  114.577 171.888 115.808 171.912 ;
     RECT  114.581 176.928 115.808 176.952 ;
     RECT  110.908 179.376 115.808 180.216 ;
     RECT  110.704 182.016 115.808 182.04 ;
     RECT  110.704 189.888 115.808 189.912 ;
     RECT  115.808 2.148 115.912 369.372 ;
     RECT  115.912 2.418 116.104 369.102 ;
     RECT  116.104 168.288 116.525 168.312 ;
     RECT  119.185 193.104 119.365 193.128 ;
     RECT  119.365 192.672 119.449 193.128 ;
     RECT  116.104 164.208 121.208 164.232 ;
     RECT  116.104 166.128 121.208 166.152 ;
     RECT  116.104 171.888 121.208 171.912 ;
     RECT  116.104 176.928 121.208 176.952 ;
     RECT  116.104 179.376 121.208 180.216 ;
     RECT  116.104 182.016 121.208 182.04 ;
     RECT  116.104 189.888 121.208 189.912 ;
     RECT  119.449 193.104 121.208 193.128 ;
     RECT  121.208 2.148 121.312 369.372 ;
     RECT  121.312 2.418 121.504 369.102 ;
     RECT  121.504 171.888 122.533 171.912 ;
     RECT  121.504 164.208 122.588 164.232 ;
     RECT  121.504 165.408 122.588 166.152 ;
     RECT  122.533 170.448 122.617 170.472 ;
     RECT  122.588 164.208 122.675 166.152 ;
     RECT  121.504 162.192 123.013 162.216 ;
     RECT  123.013 161.76 123.059 162.216 ;
     RECT  121.504 193.104 123.073 193.128 ;
     RECT  121.504 179.376 123.109 180.312 ;
     RECT  123.109 178.416 123.181 180.312 ;
     RECT  122.641 195.504 123.253 195.528 ;
     RECT  123.181 178.416 123.289 180.552 ;
     RECT  123.253 194.928 123.293 195.528 ;
     RECT  121.504 191.376 123.325 191.4 ;
     RECT  123.073 192.624 123.325 193.128 ;
     RECT  122.497 160.704 123.329 160.728 ;
     RECT  122.605 188.064 123.349 188.088 ;
     RECT  123.325 191.376 123.349 193.128 ;
     RECT  123.349 191.376 123.365 193.944 ;
     RECT  123.365 191.808 123.395 193.944 ;
     RECT  122.675 166.128 123.397 166.152 ;
     RECT  123.349 188.064 123.401 188.328 ;
     RECT  123.401 188.304 123.436 188.328 ;
     RECT  123.395 193.104 123.437 193.944 ;
     RECT  121.504 189.84 123.469 189.912 ;
     RECT  123.469 189.84 123.541 190.344 ;
     RECT  123.289 178.416 123.637 180.696 ;
     RECT  121.504 182.016 123.637 182.04 ;
     RECT  123.637 177.936 123.683 182.04 ;
     RECT  123.683 181.584 123.833 182.04 ;
     RECT  123.397 166.128 123.865 167.016 ;
     RECT  122.533 171.504 124.117 171.912 ;
     RECT  123.541 189.84 124.153 190.824 ;
     RECT  123.683 179.376 124.229 180.552 ;
     RECT  123.865 165.312 124.301 167.016 ;
     RECT  123.395 191.808 124.301 191.832 ;
     RECT  124.301 165.84 124.441 167.016 ;
     RECT  124.117 170.976 124.445 171.912 ;
     RECT  124.445 171.312 124.46 171.912 ;
     RECT  122.569 185.28 124.46 185.304 ;
     RECT  124.46 185.28 124.547 185.832 ;
     RECT  124.501 169.296 124.588 169.32 ;
     RECT  124.153 189.456 124.589 190.824 ;
     RECT  121.504 186.912 124.597 186.936 ;
     RECT  124.556 188.064 124.597 188.088 ;
     RECT  124.597 186.912 124.643 188.088 ;
     RECT  124.46 171.312 124.657 172.152 ;
     RECT  124.657 183.504 124.729 183.528 ;
     RECT  123.293 194.928 124.729 194.952 ;
     RECT  124.729 194.832 124.765 194.952 ;
     RECT  124.657 205.728 124.765 205.752 ;
     RECT  124.547 185.28 124.789 185.304 ;
     RECT  124.765 194.832 124.801 195.576 ;
     RECT  124.117 196.656 124.801 196.68 ;
     RECT  124.441 165.84 124.835 168.168 ;
     RECT  124.729 183.456 124.835 183.528 ;
     RECT  124.789 184.512 124.835 185.304 ;
     RECT  124.765 205.728 124.849 206.376 ;
     RECT  123.059 161.76 124.873 161.784 ;
     RECT  124.835 167.568 124.949 168.168 ;
     RECT  121.504 176.928 125.017 176.952 ;
     RECT  123.683 177.936 125.017 177.96 ;
     RECT  122.675 164.208 125.027 164.232 ;
     RECT  124.873 161.76 125.089 162.456 ;
     RECT  124.835 165.84 125.165 166.488 ;
     RECT  124.643 186.912 125.165 187.512 ;
     RECT  124.835 184.512 125.237 184.536 ;
     RECT  124.949 168.144 125.305 168.168 ;
     RECT  124.873 169.2 125.305 169.224 ;
     RECT  124.801 194.832 125.309 196.68 ;
     RECT  125.017 176.928 125.372 177.96 ;
     RECT  125.372 176.736 125.413 177.96 ;
     RECT  123.437 193.104 125.413 193.128 ;
     RECT  125.309 194.832 125.413 194.856 ;
     RECT  124.873 213.696 125.413 213.72 ;
     RECT  125.233 214.896 125.413 214.92 ;
     RECT  125.413 176.16 125.459 177.96 ;
     RECT  125.413 213.696 125.459 214.92 ;
     RECT  125.413 192.624 125.497 194.856 ;
     RECT  124.837 209.856 125.509 209.88 ;
     RECT  124.981 202.368 125.521 202.392 ;
     RECT  123.833 182.016 125.557 182.04 ;
     RECT  125.309 196.032 125.557 196.68 ;
     RECT  125.305 168.144 125.561 169.224 ;
     RECT  125.521 202.368 125.561 202.872 ;
     RECT  125.509 209.856 125.596 210.936 ;
     RECT  124.589 189.456 125.597 189.912 ;
     RECT  125.459 213.696 125.597 214.44 ;
     RECT  125.593 206.88 125.708 206.904 ;
     RECT  124.981 208.08 125.708 208.104 ;
     RECT  125.708 206.88 125.749 208.104 ;
     RECT  124.229 179.376 125.809 180.216 ;
     RECT  124.549 198.384 125.845 198.408 ;
     RECT  124.849 205.728 125.845 205.752 ;
     RECT  125.749 206.88 125.845 208.776 ;
     RECT  125.597 189.888 125.881 189.912 ;
     RECT  125.561 202.848 125.917 202.872 ;
     RECT  124.945 204.336 125.917 204.36 ;
     RECT  124.835 183.456 126.133 183.48 ;
     RECT  125.593 164.784 126.169 164.808 ;
     RECT  125.165 165.936 126.169 166.488 ;
     RECT  125.557 196.032 126.205 196.92 ;
     RECT  125.845 198.384 126.205 198.552 ;
     RECT  125.653 173.76 126.277 173.784 ;
     RECT  125.629 174.768 126.277 174.792 ;
     RECT  125.165 186.912 126.349 187.464 ;
     RECT  125.845 205.728 126.385 208.776 ;
     RECT  125.596 209.856 126.385 210.36 ;
     RECT  125.459 176.16 126.457 177.24 ;
     RECT  125.809 178.512 126.457 180.216 ;
     RECT  124.657 171.312 126.493 172.68 ;
     RECT  126.277 173.76 126.493 174.792 ;
     RECT  125.701 170.208 126.529 170.232 ;
     RECT  125.557 182.016 126.529 182.136 ;
     RECT  125.089 161.76 126.565 163.032 ;
     RECT  125.233 200.352 126.565 200.376 ;
     RECT  125.917 202.848 126.565 204.36 ;
     RECT  126.385 205.728 126.565 210.36 ;
     RECT  126.493 160.704 126.608 160.728 ;
     RECT  126.565 161.76 126.608 163.464 ;
     RECT  126.169 164.784 126.608 166.488 ;
     RECT  125.561 168.288 126.608 169.224 ;
     RECT  126.529 170.208 126.608 170.28 ;
     RECT  126.493 171.312 126.608 174.792 ;
     RECT  126.457 176.16 126.608 180.216 ;
     RECT  126.529 182.016 126.608 182.424 ;
     RECT  126.133 183.456 126.608 184.056 ;
     RECT  125.953 185.04 126.608 185.064 ;
     RECT  126.349 186.912 126.608 187.512 ;
     RECT  126.601 188.832 126.608 188.856 ;
     RECT  125.881 189.888 126.608 190.392 ;
     RECT  125.497 193.104 126.608 194.856 ;
     RECT  126.205 196.032 126.608 198.552 ;
     RECT  126.565 200.352 126.608 201.048 ;
     RECT  126.565 202.848 126.608 210.36 ;
     RECT  125.597 214.272 126.608 214.44 ;
     RECT  126.608 2.148 126.712 369.372 ;
     RECT  126.712 2.418 126.904 369.102 ;
     RECT  126.904 160.704 127.043 160.728 ;
     RECT  126.904 174.24 127.043 174.792 ;
     RECT  126.904 176.16 127.043 177.864 ;
     RECT  126.904 165.696 127.073 166.488 ;
     RECT  127.043 176.16 127.109 177.72 ;
     RECT  126.904 205.104 127.109 205.896 ;
     RECT  126.904 209.664 127.181 210.264 ;
     RECT  126.904 178.848 127.289 183.192 ;
     RECT  127.109 205.776 127.361 205.896 ;
     RECT  126.904 192.336 127.397 193.944 ;
     RECT  126.904 196.896 127.433 197.448 ;
     RECT  126.904 173.088 127.469 173.256 ;
     RECT  126.904 167.568 127.523 171.912 ;
     RECT  126.904 186.24 127.541 186.936 ;
     RECT  126.904 198.528 127.541 198.552 ;
     RECT  127.181 209.664 127.541 210.216 ;
     RECT  126.904 220.032 127.549 220.056 ;
     RECT  126.904 161.904 127.577 163.032 ;
     RECT  127.043 174.24 127.649 174.264 ;
     RECT  126.904 207.168 127.649 207.192 ;
     RECT  126.904 203.376 127.715 203.496 ;
     RECT  127.469 173.232 127.721 173.256 ;
     RECT  127.109 176.976 127.793 177.72 ;
     RECT  126.904 187.968 127.793 190.92 ;
     RECT  127.523 167.568 127.865 169.224 ;
     RECT  126.904 217.728 127.865 217.752 ;
     RECT  127.523 170.4 127.901 171.912 ;
     RECT  127.289 178.896 127.937 183.192 ;
     RECT  126.904 215.088 127.964 215.112 ;
     RECT  126.904 216.096 127.964 216.12 ;
     RECT  127.397 192.336 127.969 193.176 ;
     RECT  127.577 163.008 127.973 163.032 ;
     RECT  127.964 215.088 128.051 216.12 ;
     RECT  127.433 196.896 128.113 197.208 ;
     RECT  126.904 185.04 128.117 185.064 ;
     RECT  127.969 194.352 128.185 194.376 ;
     RECT  126.904 202.128 128.188 202.152 ;
     RECT  128.185 194.352 128.189 194.856 ;
     RECT  126.904 201.024 128.189 201.048 ;
     RECT  127.715 203.472 128.189 203.496 ;
     RECT  127.969 192.096 128.225 193.176 ;
     RECT  127.793 188.064 128.245 190.92 ;
     RECT  128.225 192.096 128.245 193.128 ;
     RECT  128.245 188.064 128.291 193.128 ;
     RECT  128.051 216.096 128.297 216.12 ;
     RECT  127.865 168.048 128.333 169.224 ;
     RECT  127.937 178.896 128.333 182.952 ;
     RECT  127.541 186.336 128.333 186.936 ;
     RECT  128.291 188.064 128.333 189.048 ;
     RECT  127.073 165.696 128.365 166.152 ;
     RECT  128.365 165.696 128.369 166.776 ;
     RECT  127.361 205.776 128.437 205.8 ;
     RECT  128.189 194.4 128.441 194.856 ;
     RECT  128.329 207.504 128.483 207.528 ;
     RECT  126.904 213.888 128.509 214.104 ;
     RECT  127.793 176.976 128.513 177.048 ;
     RECT  128.437 205.008 128.524 206.328 ;
     RECT  128.113 196.176 128.549 197.208 ;
     RECT  128.549 196.896 128.581 197.208 ;
     RECT  128.581 196.896 128.609 197.832 ;
     RECT  128.437 198.912 128.609 198.936 ;
     RECT  128.513 176.976 128.621 177 ;
     RECT  127.577 161.904 128.653 161.928 ;
     RECT  128.609 196.896 128.693 198.936 ;
     RECT  128.693 196.896 128.723 197.832 ;
     RECT  128.684 157.44 128.725 157.464 ;
     RECT  127.541 209.664 128.761 209.688 ;
     RECT  128.725 157.44 128.771 157.896 ;
     RECT  128.689 156.144 128.773 156.168 ;
     RECT  128.653 161.904 128.773 162.504 ;
     RECT  128.653 218.928 128.773 219.432 ;
     RECT  128.773 161.664 128.819 162.504 ;
     RECT  128.509 213.888 128.819 214.872 ;
     RECT  128.773 217.2 128.86 217.224 ;
     RECT  128.441 194.736 128.869 194.856 ;
     RECT  127.901 170.448 128.873 171.912 ;
     RECT  128.221 200.784 128.873 200.808 ;
     RECT  128.761 209.376 128.905 209.688 ;
     RECT  128.333 188.064 128.915 188.856 ;
     RECT  128.291 190.416 128.937 193.128 ;
     RECT  128.333 178.896 128.977 180.216 ;
     RECT  128.797 175.104 129.013 175.128 ;
     RECT  128.905 208.512 129.013 209.688 ;
     RECT  128.797 176.64 129.017 176.664 ;
     RECT  128.333 186.384 129.053 186.936 ;
     RECT  128.915 188.592 129.053 188.856 ;
     RECT  128.369 166.08 129.085 166.776 ;
     RECT  128.524 205.776 129.161 206.328 ;
     RECT  129.013 208.512 129.161 210.264 ;
     RECT  128.977 178.464 129.229 180.216 ;
     RECT  128.473 203.712 129.265 203.736 ;
     RECT  128.819 161.664 129.337 161.88 ;
     RECT  128.797 164.88 129.341 165.096 ;
     RECT  129.265 210.432 129.373 210.456 ;
     RECT  128.773 218.256 129.377 219.432 ;
     RECT  129.265 203.088 129.409 203.736 ;
     RECT  129.053 188.832 129.413 188.856 ;
     RECT  129.409 203.088 129.445 204.36 ;
     RECT  129.337 201.216 129.449 201.24 ;
     RECT  128.873 170.544 129.517 171.912 ;
     RECT  128.401 160.128 129.541 160.152 ;
     RECT  128.333 181.344 129.541 182.952 ;
     RECT  128.833 184.704 129.541 184.728 ;
     RECT  129.013 174.624 129.548 175.128 ;
     RECT  129.5 158.976 129.587 159 ;
     RECT  129.541 181.344 129.587 184.728 ;
     RECT  129.229 178.368 129.589 180.216 ;
     RECT  129.587 181.344 129.589 184.056 ;
     RECT  126.904 211.968 129.593 211.992 ;
     RECT  129.053 186.48 129.625 186.936 ;
     RECT  129.589 178.368 129.628 184.056 ;
     RECT  129.548 174.48 129.635 175.128 ;
     RECT  129.541 160.032 129.665 160.152 ;
     RECT  129.445 216.336 129.665 216.36 ;
     RECT  128.937 190.896 129.685 193.128 ;
     RECT  129.373 210.432 129.697 210.888 ;
     RECT  129.341 165.072 129.737 165.096 ;
     RECT  129.085 166.08 129.769 167.112 ;
     RECT  128.333 168.816 129.769 169.224 ;
     RECT  129.685 190.896 129.773 193.512 ;
     RECT  129.377 219.024 129.773 219.432 ;
     RECT  129.445 202.848 129.779 204.36 ;
     RECT  128.723 197.088 129.805 197.832 ;
     RECT  128.693 198.912 129.805 198.936 ;
     RECT  129.769 166.08 129.829 169.224 ;
     RECT  129.829 166.08 129.841 169.512 ;
     RECT  129.517 170.544 129.841 172.152 ;
     RECT  126.904 274.896 129.841 274.92 ;
     RECT  129.337 161.136 129.845 161.88 ;
     RECT  129.628 178.368 129.877 183.432 ;
     RECT  129.877 178.128 129.913 183.432 ;
     RECT  129.779 203.088 129.917 204.36 ;
     RECT  129.625 186.48 129.949 187.56 ;
     RECT  129.697 210.432 129.953 210.984 ;
     RECT  129.589 173.232 129.985 173.256 ;
     RECT  129.161 208.512 129.989 209.4 ;
     RECT  129.733 185.04 130.025 185.064 ;
     RECT  129.913 177.936 130.061 183.432 ;
     RECT  129.773 219.024 130.061 219.384 ;
     RECT  128.869 194.736 130.093 195.336 ;
     RECT  129.805 197.088 130.117 198.936 ;
     RECT  129.841 199.92 130.117 199.944 ;
     RECT  129.665 160.032 130.129 160.056 ;
     RECT  129.773 190.896 130.129 193.32 ;
     RECT  130.129 190.032 130.133 193.32 ;
     RECT  130.133 190.032 130.165 191.4 ;
     RECT  130.117 197.088 130.165 199.944 ;
     RECT  129.589 176.304 130.169 176.328 ;
     RECT  129.841 274.896 130.169 275.256 ;
     RECT  128.819 213.888 130.201 213.912 ;
     RECT  130.061 183.408 130.205 183.432 ;
     RECT  130.093 194.4 130.205 195.336 ;
     RECT  130.165 196.368 130.205 199.944 ;
     RECT  130.205 196.368 130.211 198.936 ;
     RECT  129.841 166.08 130.241 172.152 ;
     RECT  129.949 186.48 130.273 187.848 ;
     RECT  129.953 210.96 130.309 210.984 ;
     RECT  130.211 196.368 130.313 197.784 ;
     RECT  129.161 205.776 130.345 205.848 ;
     RECT  130.345 205.776 130.384 205.896 ;
     RECT  130.061 177.936 130.385 182.136 ;
     RECT  130.241 166.08 130.392 171.912 ;
     RECT  129.301 221.184 130.417 221.208 ;
     RECT  129.917 204.336 130.453 204.36 ;
     RECT  130.384 205.728 130.453 205.896 ;
     RECT  130.129 159.984 130.493 160.056 ;
     RECT  130.165 189.312 130.493 191.4 ;
     RECT  130.417 220.608 130.501 221.208 ;
     RECT  130.385 177.936 130.525 180.264 ;
     RECT  130.453 204.336 130.525 205.896 ;
     RECT  129.625 207.312 130.525 207.336 ;
     RECT  130.057 155.184 130.549 155.208 ;
     RECT  130.273 185.616 130.549 187.848 ;
     RECT  130.549 155.184 130.595 155.592 ;
     RECT  128.771 157.872 130.597 157.896 ;
     RECT  130.205 199.92 130.633 199.944 ;
     RECT  129.409 163.824 130.645 163.848 ;
     RECT  130.561 164.832 130.645 164.856 ;
     RECT  129.845 161.28 130.681 161.88 ;
     RECT  130.201 213.888 130.705 214.536 ;
     RECT  130.501 221.184 130.745 221.208 ;
     RECT  130.313 197.04 130.78 197.784 ;
     RECT  130.645 163.824 130.781 164.856 ;
     RECT  130.525 204.336 130.781 207.336 ;
     RECT  130.681 161.856 130.813 161.88 ;
     RECT  130.493 160.032 130.837 160.056 ;
     RECT  129.635 174.624 130.849 174.648 ;
     RECT  130.837 160.032 130.883 160.776 ;
     RECT  130.061 219.024 130.883 219.048 ;
     RECT  130.781 204.336 130.921 206.616 ;
     RECT  130.837 220.08 130.924 220.104 ;
     RECT  130.849 174.624 130.957 174.744 ;
     RECT  130.549 185.616 131.065 188.136 ;
     RECT  129.989 208.512 131.093 208.584 ;
     RECT  130.597 157.488 131.101 157.896 ;
     RECT  131.065 185.424 131.101 188.136 ;
     RECT  130.705 213.072 131.101 214.536 ;
     RECT  130.309 210.96 131.125 211.128 ;
     RECT  129.985 173.232 131.173 173.304 ;
     RECT  129.917 203.088 131.173 203.208 ;
     RECT  131.125 210.96 131.173 211.944 ;
     RECT  131.101 213.072 131.173 214.776 ;
     RECT  130.345 216.048 131.209 216.072 ;
     RECT  130.392 165.84 131.245 171.912 ;
     RECT  131.173 173.232 131.245 173.448 ;
     RECT  131.173 210.96 131.281 214.776 ;
     RECT  131.209 215.76 131.281 216.072 ;
     RECT  130.205 195.312 131.317 195.336 ;
     RECT  131.101 185.136 131.353 188.136 ;
     RECT  130.493 189.312 131.353 191.256 ;
     RECT  130.781 164.16 131.413 164.856 ;
     RECT  131.245 165.84 131.413 173.448 ;
     RECT  130.133 192.432 131.413 193.32 ;
     RECT  131.413 192.432 131.569 193.848 ;
     RECT  131.317 195.312 131.569 195.624 ;
     RECT  130.633 199.92 131.569 200.136 ;
     RECT  130.595 155.568 131.641 155.592 ;
     RECT  131.101 157.488 131.653 157.944 ;
     RECT  131.281 210.96 131.713 216.072 ;
     RECT  130.385 182.112 131.749 182.136 ;
     RECT  131.569 192.432 131.785 195.624 ;
     RECT  129.841 201.36 131.857 201.384 ;
     RECT  131.173 202.368 131.857 203.208 ;
     RECT  131.353 185.136 131.893 191.256 ;
     RECT  131.209 218.592 131.893 218.808 ;
     RECT  131.065 222.096 131.929 222.12 ;
     RECT  131.785 149.904 132.008 149.928 ;
     RECT  131.785 151.584 132.008 151.608 ;
     RECT  131.713 152.784 132.008 152.808 ;
     RECT  131.641 155.568 132.008 156.504 ;
     RECT  131.653 157.488 132.008 158.52 ;
     RECT  130.883 160.752 132.008 160.776 ;
     RECT  130.813 161.856 132.008 162.552 ;
     RECT  131.413 164.16 132.008 173.448 ;
     RECT  130.957 174.624 132.008 175.128 ;
     RECT  130.525 177.888 132.008 180.264 ;
     RECT  131.749 181.248 132.008 182.136 ;
     RECT  131.893 184.512 132.008 191.256 ;
     RECT  131.785 192.432 132.008 195.672 ;
     RECT  130.78 197.04 132.008 197.448 ;
     RECT  130.211 198.912 132.008 198.936 ;
     RECT  131.569 199.92 132.008 200.232 ;
     RECT  131.857 201.36 132.008 203.208 ;
     RECT  130.921 204.192 132.008 206.616 ;
     RECT  131.093 208.08 132.008 208.584 ;
     RECT  131.713 210.528 132.008 216.072 ;
     RECT  131.893 218.592 132.008 219.096 ;
     RECT  131.929 222.096 132.008 222.36 ;
     RECT  130.169 275.232 132.008 275.256 ;
     RECT  132.008 2.148 132.112 369.372 ;
     RECT  132.112 2.418 132.133 369.372 ;
     RECT  130.309 371.472 132.229 371.496 ;
     RECT  132.133 2.418 132.304 369.912 ;
     RECT  132.304 152.112 132.365 154.488 ;
     RECT  132.304 155.664 132.365 157.848 ;
     RECT  132.304 169.296 132.401 172.152 ;
     RECT  132.304 220.656 132.419 221.064 ;
     RECT  132.304 222.096 132.419 223.944 ;
     RECT  132.304 225.072 132.419 225.096 ;
     RECT  132.304 226.272 132.419 226.968 ;
     RECT  132.304 275.232 132.467 275.256 ;
     RECT  132.304 211.584 132.509 211.608 ;
     RECT  132.304 235.44 132.563 235.656 ;
     RECT  132.229 371.136 132.563 371.496 ;
     RECT  132.401 169.296 132.611 171.912 ;
     RECT  132.563 371.136 132.659 371.304 ;
     RECT  132.563 235.44 132.755 235.464 ;
     RECT  132.304 198.288 132.797 206.472 ;
     RECT  132.419 222.096 132.803 223.416 ;
     RECT  132.304 188.496 132.833 193.224 ;
     RECT  132.304 212.592 132.851 214.296 ;
     RECT  132.803 222.096 132.941 222.696 ;
     RECT  132.797 198.288 132.947 206.328 ;
     RECT  132.947 200.64 133.013 206.328 ;
     RECT  132.304 369.888 133.085 369.912 ;
     RECT  132.365 152.112 133.139 154.44 ;
     RECT  133.013 200.784 133.139 206.328 ;
     RECT  132.833 188.592 133.157 193.224 ;
     RECT  133.139 152.448 133.193 154.44 ;
     RECT  133.193 152.448 133.229 153.768 ;
     RECT  132.365 156.768 133.229 157.848 ;
     RECT  132.304 165.216 133.229 167.064 ;
     RECT  132.304 216.384 133.265 216.408 ;
     RECT  132.304 164.016 133.297 164.136 ;
     RECT  133.229 165.216 133.297 166.776 ;
     RECT  132.304 168.144 133.297 168.168 ;
     RECT  132.304 179.376 133.297 182.616 ;
     RECT  132.304 183.6 133.297 187.512 ;
     RECT  132.304 173.424 133.333 173.448 ;
     RECT  132.304 175.104 133.333 177.096 ;
     RECT  133.297 168.144 133.337 168.792 ;
     RECT  133.229 156.768 133.345 156.792 ;
     RECT  133.297 209.328 133.381 209.352 ;
     RECT  133.297 179.376 133.405 187.512 ;
     RECT  133.139 204.624 133.409 206.328 ;
     RECT  133.297 211.488 133.427 211.512 ;
     RECT  132.304 196.656 133.441 197.208 ;
     RECT  133.381 208.656 133.468 209.352 ;
     RECT  133.297 164.016 133.481 166.776 ;
     RECT  132.419 226.272 133.525 226.296 ;
     RECT  132.304 159.168 133.553 160.056 ;
     RECT  133.484 224.304 133.571 224.328 ;
     RECT  133.333 173.424 133.621 177.096 ;
     RECT  133.405 179.376 133.621 187.56 ;
     RECT  132.304 194.544 133.693 194.568 ;
     RECT  133.553 159.792 133.729 160.056 ;
     RECT  133.157 188.592 133.763 193.128 ;
     RECT  133.621 173.424 133.765 177.144 ;
     RECT  132.365 155.664 133.801 155.688 ;
     RECT  133.765 173.424 133.801 178.008 ;
     RECT  132.611 170.16 133.868 171.912 ;
     RECT  133.801 173.424 133.868 178.248 ;
     RECT  133.868 170.16 133.873 178.248 ;
     RECT  133.621 179.328 133.873 187.56 ;
     RECT  133.693 194.544 133.873 194.808 ;
     RECT  133.801 154.992 133.885 155.688 ;
     RECT  133.441 196.656 133.909 197.256 ;
     RECT  132.304 218.16 133.913 219.432 ;
     RECT  132.304 149.904 133.945 150.504 ;
     RECT  133.909 196.608 133.945 197.256 ;
     RECT  133.873 170.16 133.955 187.56 ;
     RECT  133.945 149.856 133.985 150.504 ;
     RECT  133.525 225.6 134.005 226.296 ;
     RECT  133.955 173.136 134.017 187.56 ;
     RECT  133.763 188.592 134.017 192.456 ;
     RECT  134.005 225.6 134.051 226.92 ;
     RECT  132.851 212.976 134.089 214.296 ;
     RECT  134.051 226.896 134.161 226.92 ;
     RECT  134.017 209.568 134.165 209.592 ;
     RECT  133.229 152.448 134.197 152.472 ;
     RECT  133.229 153.744 134.197 153.768 ;
     RECT  132.304 163.008 134.197 163.032 ;
     RECT  134.161 226.896 134.201 227.16 ;
     RECT  132.304 148.224 134.233 148.248 ;
     RECT  134.197 152.448 134.233 153.768 ;
     RECT  133.229 157.824 134.243 157.848 ;
     RECT  134.156 161.712 134.243 161.736 ;
     RECT  133.945 195.888 134.293 197.256 ;
     RECT  132.947 198.288 134.293 199.416 ;
     RECT  133.729 159.792 134.305 160.68 ;
     RECT  133.409 204.624 134.341 205.992 ;
     RECT  134.089 212.928 134.341 214.296 ;
     RECT  133.139 200.784 134.345 203.208 ;
     RECT  133.909 208.464 134.377 208.488 ;
     RECT  133.337 168.768 134.396 168.792 ;
     RECT  134.345 200.832 134.413 203.208 ;
     RECT  134.341 204.192 134.413 205.992 ;
     RECT  134.293 195.888 134.449 199.416 ;
     RECT  134.051 225.6 134.453 225.624 ;
     RECT  134.396 168.768 134.483 169.032 ;
     RECT  134.437 137.904 134.485 137.928 ;
     RECT  134.413 139.104 134.485 139.224 ;
     RECT  133.885 155.664 134.485 155.688 ;
     RECT  134.413 200.832 134.489 205.992 ;
     RECT  134.485 137.904 134.497 139.224 ;
     RECT  134.497 137.904 134.525 139.128 ;
     RECT  134.017 173.136 134.525 192.456 ;
     RECT  134.489 200.832 134.525 205.8 ;
     RECT  134.525 138.576 134.531 139.128 ;
     RECT  134.525 189.696 134.561 192.456 ;
     RECT  133.873 194.448 134.593 194.808 ;
     RECT  134.269 230.928 134.593 230.952 ;
     RECT  134.483 168.768 134.597 168.84 ;
     RECT  134.305 215.904 134.597 215.928 ;
     RECT  133.913 218.16 134.597 219.096 ;
     RECT  134.233 147.552 134.633 148.248 ;
     RECT  134.485 155.664 134.633 156.312 ;
     RECT  134.597 218.16 134.633 218.856 ;
     RECT  134.593 230.928 134.633 231.432 ;
     RECT  134.561 189.984 134.669 192.456 ;
     RECT  134.633 148.176 134.705 148.248 ;
     RECT  134.233 152.448 134.705 154.536 ;
     RECT  134.449 195.888 134.705 199.464 ;
     RECT  134.197 163.008 134.732 163.176 ;
     RECT  132.419 221.04 134.741 221.064 ;
     RECT  133.955 170.16 134.773 171.912 ;
     RECT  134.705 195.888 134.777 199.416 ;
     RECT  134.732 162.24 134.819 163.176 ;
     RECT  133.481 164.448 134.845 166.776 ;
     RECT  133.985 149.856 134.881 149.88 ;
     RECT  134.845 164.448 134.885 167.304 ;
     RECT  134.777 195.888 134.885 199.32 ;
     RECT  134.233 228.144 134.885 228.168 ;
     RECT  134.593 206.928 134.917 206.952 ;
     RECT  134.377 208.032 134.917 208.488 ;
     RECT  134.341 212.544 134.989 214.296 ;
     RECT  134.881 149.808 135.011 149.88 ;
     RECT  134.233 150.912 135.029 150.936 ;
     RECT  134.989 216.576 135.061 216.6 ;
     RECT  134.633 218.16 135.061 218.52 ;
     RECT  134.885 195.888 135.065 198.312 ;
     RECT  134.633 155.664 135.097 155.688 ;
     RECT  134.593 193.632 135.101 194.808 ;
     RECT  135.061 216.576 135.107 218.52 ;
     RECT  135.068 233.616 135.109 233.64 ;
     RECT  134.633 231.264 135.133 231.432 ;
     RECT  135.065 195.888 135.137 197.064 ;
     RECT  135.011 149.856 135.155 149.88 ;
     RECT  135.109 233.616 135.155 234.168 ;
     RECT  134.989 235.2 135.155 235.992 ;
     RECT  134.809 209.76 135.157 210.36 ;
     RECT  134.525 173.136 135.169 188.616 ;
     RECT  134.917 206.928 135.169 208.488 ;
     RECT  134.989 212.544 135.173 214.872 ;
     RECT  135.157 209.76 135.244 210.984 ;
     RECT  135.097 155.28 135.281 155.688 ;
     RECT  134.917 222.144 135.308 222.168 ;
     RECT  134.819 162.624 135.313 163.176 ;
     RECT  134.885 164.448 135.313 164.712 ;
     RECT  134.669 190.176 135.313 192.456 ;
     RECT  135.101 193.632 135.313 194.52 ;
     RECT  134.705 152.448 135.317 153.96 ;
     RECT  134.773 169.92 135.349 171.912 ;
     RECT  135.169 173.04 135.349 188.616 ;
     RECT  135.349 169.92 135.353 188.616 ;
     RECT  135.308 221.616 135.395 222.168 ;
     RECT  134.377 229.152 135.421 229.176 ;
     RECT  134.525 203.136 135.425 205.8 ;
     RECT  135.107 217.392 135.425 218.52 ;
     RECT  134.885 165.84 135.457 167.304 ;
     RECT  135.395 221.76 135.457 222.168 ;
     RECT  135.155 235.968 135.493 235.992 ;
     RECT  135.317 152.448 135.532 153.912 ;
     RECT  135.493 235.968 135.539 236.808 ;
     RECT  135.421 229.152 135.566 230.184 ;
     RECT  134.885 199.296 135.569 199.32 ;
     RECT  135.133 231.264 135.569 231.864 ;
     RECT  135.539 236.352 135.58 236.808 ;
     RECT  135.457 221.76 135.589 222.264 ;
     RECT  135.421 223.296 135.589 223.32 ;
     RECT  134.665 147.072 135.605 147.096 ;
     RECT  135.457 165.84 135.635 167.544 ;
     RECT  135.589 221.76 135.635 223.32 ;
     RECT  135.313 190.176 135.637 194.52 ;
     RECT  134.201 227.136 135.641 227.16 ;
     RECT  135.109 151.344 135.673 151.368 ;
     RECT  135.532 152.448 135.673 152.76 ;
     RECT  134.597 168.816 135.673 168.84 ;
     RECT  135.169 206.928 135.709 208.632 ;
     RECT  135.244 209.76 135.709 210.168 ;
     RECT  134.531 138.576 135.713 138.6 ;
     RECT  135.565 145.344 135.713 145.368 ;
     RECT  135.353 175.392 135.731 188.616 ;
     RECT  135.425 203.376 135.733 205.8 ;
     RECT  135.566 230.16 135.749 230.184 ;
     RECT  135.313 158.448 135.781 158.472 ;
     RECT  135.313 162.624 135.781 164.712 ;
     RECT  135.731 178.224 135.781 188.616 ;
     RECT  135.173 212.544 135.781 212.616 ;
     RECT  135.709 206.928 135.793 210.168 ;
     RECT  135.793 209.76 135.821 210.168 ;
     RECT  135.173 213.744 135.821 214.872 ;
     RECT  135.566 229.152 135.821 229.176 ;
     RECT  135.155 234.144 135.821 234.168 ;
     RECT  135.635 165.84 135.857 166.968 ;
     RECT  135.673 168 135.877 168.84 ;
     RECT  135.353 169.92 135.877 174.312 ;
     RECT  134.525 200.832 135.877 201.768 ;
     RECT  134.989 137.28 135.889 137.304 ;
     RECT  135.781 162.576 135.889 164.712 ;
     RECT  135.169 225.168 135.889 225.192 ;
     RECT  135.569 231.312 135.889 231.864 ;
     RECT  135.889 225.168 135.929 225.288 ;
     RECT  135.781 140.784 135.961 140.808 ;
     RECT  135.821 214.848 135.961 214.872 ;
     RECT  135.877 168 135.964 174.312 ;
     RECT  135.964 169.92 135.971 174.312 ;
     RECT  135.877 199.968 135.997 201.768 ;
     RECT  134.305 159.792 136.033 160.824 ;
     RECT  135.673 151.344 136.037 152.76 ;
     RECT  135.635 221.76 136.037 222.36 ;
     RECT  135.733 203.376 136.069 205.896 ;
     RECT  135.793 206.928 136.069 208.632 ;
     RECT  134.521 143.088 136.105 143.112 ;
     RECT  135.637 189.984 136.105 194.52 ;
     RECT  136.105 143.088 136.145 143.208 ;
     RECT  135.781 158.448 136.165 158.568 ;
     RECT  136.165 158.016 136.177 158.568 ;
     RECT  136.033 159.792 136.177 161.064 ;
     RECT  136.105 189.888 136.177 194.52 ;
     RECT  136.033 139.056 136.211 139.128 ;
     RECT  136.177 157.776 136.211 158.568 ;
     RECT  135.781 178.224 136.213 188.856 ;
     RECT  136.177 189.84 136.213 194.52 ;
     RECT  135.889 162.576 136.253 165.432 ;
     RECT  136.037 152.736 136.289 152.76 ;
     RECT  135.817 149.952 136.321 149.976 ;
     RECT  136.037 151.344 136.321 151.368 ;
     RECT  135.532 153.888 136.321 153.912 ;
     RECT  135.877 219.648 136.357 219.672 ;
     RECT  135.781 212.016 136.361 212.616 ;
     RECT  135.961 214.848 136.361 215.4 ;
     RECT  136.285 234.288 136.369 234.888 ;
     RECT  135.137 195.888 136.393 197.016 ;
     RECT  135.065 198.288 136.393 198.312 ;
     RECT  136.069 203.376 136.403 208.632 ;
     RECT  136.213 178.224 136.412 194.52 ;
     RECT  136.393 195.6 136.412 197.016 ;
     RECT  136.253 162.576 136.433 165.288 ;
     RECT  135.821 213.744 136.433 213.768 ;
     RECT  135.425 218.208 136.433 218.52 ;
     RECT  136.429 233.088 136.501 233.112 ;
     RECT  135.961 140.784 136.537 141.384 ;
     RECT  135.281 155.28 136.537 155.304 ;
     RECT  135.493 156.72 136.537 156.744 ;
     RECT  136.361 212.448 136.609 212.616 ;
     RECT  136.604 134.736 136.645 134.76 ;
     RECT  135.889 231.312 136.681 231.912 ;
     RECT  135.971 169.968 136.741 174.312 ;
     RECT  135.731 175.392 136.741 177.24 ;
     RECT  136.321 153.888 136.789 154.152 ;
     RECT  135.857 166.464 136.789 166.968 ;
     RECT  135.964 168 136.789 168.84 ;
     RECT  136.412 178.224 136.789 197.016 ;
     RECT  136.393 198.288 136.789 198.504 ;
     RECT  136.403 204.816 136.789 208.632 ;
     RECT  134.705 148.176 136.825 148.2 ;
     RECT  136.681 230.88 136.861 231.912 ;
     RECT  136.177 159.552 136.885 161.064 ;
     RECT  136.433 162.576 136.885 164.472 ;
     RECT  136.681 217.536 136.933 217.56 ;
     RECT  136.861 230.4 136.933 231.912 ;
     RECT  136.501 233.04 136.933 233.112 ;
     RECT  136.357 219.648 136.988 220.152 ;
     RECT  136.033 224.016 137.036 224.04 ;
     RECT  136.145 143.184 137.041 143.208 ;
     RECT  135.997 199.968 137.077 202.344 ;
     RECT  136.403 203.376 137.077 203.496 ;
     RECT  136.988 219.648 137.077 220.392 ;
     RECT  136.037 222.144 137.077 222.36 ;
     RECT  136.573 227.184 137.077 227.208 ;
     RECT  136.789 178.224 137.149 198.504 ;
     RECT  137.077 199.584 137.149 203.496 ;
     RECT  136.933 217.248 137.221 217.56 ;
     RECT  136.933 230.4 137.221 233.112 ;
     RECT  136.369 234.288 137.221 234.312 ;
     RECT  137.077 219.648 137.257 220.488 ;
     RECT  136.361 215.376 137.269 215.4 ;
     RECT  137.221 216.624 137.269 217.56 ;
     RECT  136.789 153.6 137.293 154.152 ;
     RECT  136.537 155.28 137.293 156.744 ;
     RECT  136.789 166.464 137.329 168.84 ;
     RECT  137.077 222.144 137.329 222.6 ;
     RECT  137.149 178.224 137.365 203.496 ;
     RECT  136.789 204.816 137.365 208.824 ;
     RECT  136.609 212.448 137.365 213.672 ;
     RECT  137.329 221.76 137.401 222.6 ;
     RECT  136.645 134.496 137.408 134.76 ;
     RECT  136.165 136.176 137.408 136.2 ;
     RECT  135.889 137.28 137.408 138.024 ;
     RECT  136.211 139.056 137.408 139.08 ;
     RECT  136.537 140.784 137.408 141.912 ;
     RECT  137.041 143.184 137.408 143.928 ;
     RECT  137.041 146.784 137.408 146.808 ;
     RECT  136.825 148.176 137.408 148.872 ;
     RECT  136.321 149.952 137.408 151.368 ;
     RECT  137.293 153.6 137.408 156.744 ;
     RECT  136.211 157.776 137.408 158.04 ;
     RECT  136.885 159.552 137.408 164.472 ;
     RECT  137.329 165.84 137.408 168.84 ;
     RECT  136.741 169.968 137.408 177.24 ;
     RECT  137.365 178.224 137.408 208.824 ;
     RECT  135.821 210.144 137.408 210.168 ;
     RECT  137.365 212.064 137.408 213.672 ;
     RECT  137.269 215.376 137.408 217.56 ;
     RECT  137.257 219.456 137.408 220.488 ;
     RECT  137.401 221.76 137.408 222.84 ;
     RECT  137.036 223.824 137.408 224.04 ;
     RECT  135.929 225.264 137.408 225.288 ;
     RECT  137.077 226.56 137.408 227.208 ;
     RECT  137.221 230.4 137.408 234.312 ;
     RECT  135.58 236.352 137.408 236.376 ;
     RECT  136.652 237.696 137.408 237.72 ;
     RECT  137.408 2.148 137.512 369.372 ;
     RECT  137.512 2.418 137.704 369.102 ;
     RECT  137.704 175.584 137.729 177.24 ;
     RECT  137.729 175.584 137.765 177.048 ;
     RECT  137.704 225.264 137.765 232.008 ;
     RECT  137.704 148.848 137.801 152.088 ;
     RECT  137.765 225.552 137.843 232.008 ;
     RECT  137.704 178.656 137.909 208.824 ;
     RECT  137.909 178.992 137.945 208.824 ;
     RECT  137.801 148.848 138.035 150.312 ;
     RECT  137.945 178.992 138.089 197.784 ;
     RECT  137.704 222.816 138.197 222.84 ;
     RECT  137.704 224.016 138.269 224.04 ;
     RECT  137.704 146.448 138.341 147 ;
     RECT  137.704 154.56 138.371 157.368 ;
     RECT  137.704 161.904 138.377 174.552 ;
     RECT  137.843 230.736 138.377 232.008 ;
     RECT  138.371 154.656 138.412 157.368 ;
     RECT  138.035 148.848 138.413 149.496 ;
     RECT  138.377 161.904 138.413 174.456 ;
     RECT  138.341 146.784 138.515 147 ;
     RECT  138.413 148.848 138.515 149.352 ;
     RECT  137.843 225.552 138.515 229.56 ;
     RECT  137.704 233.088 138.515 236.424 ;
     RECT  138.377 231.312 138.557 232.008 ;
     RECT  137.945 198.912 138.593 208.824 ;
     RECT  138.515 225.552 138.629 228.264 ;
     RECT  138.557 231.792 138.665 232.008 ;
     RECT  137.704 158.544 138.701 160.824 ;
     RECT  137.704 210.624 138.733 210.792 ;
     RECT  137.704 218.352 138.733 220.68 ;
     RECT  138.701 158.592 138.737 160.824 ;
     RECT  138.413 161.904 138.737 174.216 ;
     RECT  137.704 212.016 138.737 214.104 ;
     RECT  138.737 158.592 138.773 159 ;
     RECT  138.737 165.408 138.803 174.216 ;
     RECT  138.737 159.984 138.805 160.824 ;
     RECT  138.773 158.976 138.809 159 ;
     RECT  138.515 234.816 138.809 236.424 ;
     RECT  137.704 140.16 138.841 140.184 ;
     RECT  138.805 159.984 138.841 160.92 ;
     RECT  138.737 161.904 138.841 164.376 ;
     RECT  138.089 181.632 138.845 197.784 ;
     RECT  138.841 140.064 138.877 140.184 ;
     RECT  138.737 212.016 138.917 213.672 ;
     RECT  137.801 151.344 138.949 152.088 ;
     RECT  138.841 159.984 138.953 164.376 ;
     RECT  137.704 221.76 138.953 221.784 ;
     RECT  138.733 209.712 138.956 210.792 ;
     RECT  138.917 212.016 138.956 213.624 ;
     RECT  137.704 136.176 138.985 137.592 ;
     RECT  138.913 138.912 138.985 138.936 ;
     RECT  137.704 144.816 138.985 144.84 ;
     RECT  138.733 218.304 138.985 220.68 ;
     RECT  138.809 236.352 138.989 236.424 ;
     RECT  138.845 183.744 139.013 197.784 ;
     RECT  138.593 198.912 139.013 208.68 ;
     RECT  138.985 144.48 139.025 144.84 ;
     RECT  138.956 209.712 139.025 213.624 ;
     RECT  138.809 234.816 139.025 234.84 ;
     RECT  139.025 211.392 139.043 213.624 ;
     RECT  137.704 215.568 139.052 216.024 ;
     RECT  138.985 218.304 139.061 220.776 ;
     RECT  137.765 175.584 139.091 177 ;
     RECT  139.013 183.744 139.091 208.68 ;
     RECT  139.091 183.744 139.097 200.568 ;
     RECT  139.025 144.48 139.129 144.504 ;
     RECT  138.803 165.408 139.133 168.36 ;
     RECT  139.052 215.568 139.139 216.888 ;
     RECT  139.139 215.568 139.169 216.024 ;
     RECT  138.629 225.552 139.169 228.12 ;
     RECT  138.089 178.992 139.237 180.552 ;
     RECT  138.845 181.632 139.237 182.616 ;
     RECT  138.985 135.648 139.313 137.592 ;
     RECT  139.097 198.816 139.313 200.568 ;
     RECT  138.877 140.064 139.345 140.28 ;
     RECT  137.704 141.888 139.345 141.912 ;
     RECT  139.091 176.592 139.345 177 ;
     RECT  139.237 178.992 139.345 182.616 ;
     RECT  138.949 151.344 139.381 152.76 ;
     RECT  138.515 233.088 139.381 233.64 ;
     RECT  138.515 146.976 139.417 147 ;
     RECT  138.412 156.768 139.42 157.368 ;
     RECT  139.381 151.344 139.427 153.192 ;
     RECT  139.133 165.84 139.523 168.36 ;
     RECT  139.169 225.552 139.529 226.872 ;
     RECT  138.803 169.344 139.561 174.216 ;
     RECT  139.091 201.6 139.561 208.68 ;
     RECT  139.025 209.712 139.561 210.072 ;
     RECT  139.061 218.352 139.601 220.776 ;
     RECT  138.989 236.4 139.601 236.424 ;
     RECT  139.427 153.168 139.621 153.192 ;
     RECT  138.412 154.656 139.621 155.736 ;
     RECT  138.985 138.912 139.628 139.032 ;
     RECT  139.345 140.064 139.628 141.912 ;
     RECT  139.621 153.168 139.667 155.736 ;
     RECT  139.313 136.944 139.669 137.592 ;
     RECT  139.628 138.912 139.669 141.912 ;
     RECT  139.381 232.608 139.669 233.64 ;
     RECT  138.515 149.328 139.673 149.352 ;
     RECT  137.704 237.792 139.709 237.816 ;
     RECT  139.345 176.592 139.763 177.288 ;
     RECT  139.669 136.944 139.781 141.912 ;
     RECT  139.561 169.344 139.813 174.408 ;
     RECT  139.601 218.976 139.813 220.776 ;
     RECT  137.704 239.808 139.813 239.832 ;
     RECT  139.313 135.648 139.817 135.912 ;
     RECT  139.523 168.24 139.849 168.36 ;
     RECT  139.813 169.344 139.849 174.456 ;
     RECT  139.345 178.368 139.849 182.616 ;
     RECT  139.097 183.744 139.849 197.784 ;
     RECT  139.781 140.688 139.916 141.912 ;
     RECT  139.561 222.336 139.921 222.36 ;
     RECT  139.781 136.944 139.925 139.704 ;
     RECT  139.667 153.168 139.925 153.768 ;
     RECT  138.985 143.28 139.957 143.304 ;
     RECT  139.129 144.288 139.957 144.504 ;
     RECT  139.925 138.912 139.961 139.704 ;
     RECT  139.957 143.28 139.997 144.504 ;
     RECT  139.916 140.688 140.003 142.104 ;
     RECT  139.561 201.6 140.029 210.072 ;
     RECT  139.043 212.016 140.029 213.624 ;
     RECT  138.515 229.536 140.029 229.56 ;
     RECT  139.091 175.584 140.065 175.608 ;
     RECT  139.763 176.592 140.065 177.24 ;
     RECT  139.849 149.184 140.101 149.208 ;
     RECT  139.42 157.296 140.137 157.368 ;
     RECT  139.849 178.368 140.137 197.784 ;
     RECT  139.313 198.816 140.137 200.376 ;
     RECT  140.029 201.6 140.137 213.624 ;
     RECT  139.997 143.28 140.147 144.216 ;
     RECT  140.029 132.72 140.197 132.744 ;
     RECT  138.769 134.064 140.197 134.088 ;
     RECT  139.417 146.976 140.197 147.768 ;
     RECT  140.101 148.992 140.197 149.208 ;
     RECT  140.029 229.536 140.197 230.328 ;
     RECT  138.953 159.984 140.209 164.28 ;
     RECT  140.197 131.568 140.243 134.088 ;
     RECT  140.197 146.496 140.243 149.208 ;
     RECT  139.621 225.072 140.243 225.096 ;
     RECT  139.669 232.032 140.243 233.64 ;
     RECT  139.667 155.616 140.249 155.736 ;
     RECT  140.209 159.744 140.249 164.28 ;
     RECT  139.849 168.24 140.281 174.456 ;
     RECT  140.065 175.584 140.281 177.24 ;
     RECT  139.669 217.152 140.281 217.176 ;
     RECT  140.197 223.92 140.284 223.944 ;
     RECT  140.137 157.296 140.285 157.704 ;
     RECT  139.961 139.68 140.321 139.704 ;
     RECT  140.197 229.536 140.393 230.952 ;
     RECT  140.137 178.368 140.425 200.376 ;
     RECT  140.137 201.6 140.425 214.2 ;
     RECT  139.169 215.568 140.425 215.592 ;
     RECT  140.281 217.152 140.425 217.56 ;
     RECT  140.243 146.496 140.461 146.52 ;
     RECT  139.427 151.344 140.461 151.944 ;
     RECT  139.925 153.168 140.461 153.528 ;
     RECT  140.425 215.568 140.465 217.56 ;
     RECT  139.813 218.976 140.485 221.16 ;
     RECT  139.921 222.336 140.485 222.888 ;
     RECT  139.523 165.84 140.497 167.064 ;
     RECT  140.281 168.24 140.497 177.24 ;
     RECT  139.529 226.464 140.533 226.872 ;
     RECT  140.243 133.536 140.573 133.56 ;
     RECT  140.003 140.688 140.573 141.336 ;
     RECT  139.169 228.096 140.579 228.12 ;
     RECT  140.393 229.632 140.605 230.952 ;
     RECT  140.465 215.568 140.609 217.32 ;
     RECT  140.485 218.976 140.627 222.888 ;
     RECT  140.249 160.992 140.641 164.28 ;
     RECT  140.243 131.568 140.681 132.12 ;
     RECT  139.925 136.944 140.681 137.784 ;
     RECT  140.425 178.368 140.681 214.2 ;
     RECT  140.147 144.192 140.717 144.216 ;
     RECT  140.497 165.84 140.725 177.24 ;
     RECT  140.681 178.368 140.725 209.304 ;
     RECT  140.681 210.672 140.749 214.2 ;
     RECT  140.641 160.992 140.785 164.472 ;
     RECT  140.605 229.632 140.812 231 ;
     RECT  140.461 145.632 140.819 146.52 ;
     RECT  140.243 148.176 140.821 149.208 ;
     RECT  140.627 218.976 140.825 221.16 ;
     RECT  140.627 222.864 140.825 222.888 ;
     RECT  140.785 160.992 140.849 164.568 ;
     RECT  140.725 165.84 140.861 209.304 ;
     RECT  140.821 148.176 140.867 149.4 ;
     RECT  140.867 148.272 140.905 149.4 ;
     RECT  140.861 194.976 140.915 209.304 ;
     RECT  140.825 218.976 140.929 220.248 ;
     RECT  140.461 151.344 140.965 153.528 ;
     RECT  140.905 148.8 140.969 149.4 ;
     RECT  140.249 159.744 140.969 159.768 ;
     RECT  140.749 210.672 140.969 214.488 ;
     RECT  140.573 141.312 141.005 141.336 ;
     RECT  140.915 194.976 141.005 202.728 ;
     RECT  140.969 210.672 141.005 211.32 ;
     RECT  140.243 232.608 141.041 233.64 ;
     RECT  140.861 165.84 141.107 193.848 ;
     RECT  139.817 135.888 141.109 135.912 ;
     RECT  140.965 151.344 141.145 154.488 ;
     RECT  140.749 235.872 141.149 235.896 ;
     RECT  139.669 241.488 141.149 241.512 ;
     RECT  140.969 212.64 141.164 214.488 ;
     RECT  141.041 232.608 141.185 233.112 ;
     RECT  141.164 212.64 141.217 214.584 ;
     RECT  140.609 215.568 141.217 215.592 ;
     RECT  141.005 194.976 141.257 202.68 ;
     RECT  140.915 203.712 141.257 209.304 ;
     RECT  141.217 212.64 141.257 215.592 ;
     RECT  140.681 137.76 141.289 137.784 ;
     RECT  140.969 148.992 141.293 149.208 ;
     RECT  141.257 203.712 141.293 208.056 ;
     RECT  141.257 212.688 141.301 215.592 ;
     RECT  140.681 132.096 141.329 132.12 ;
     RECT  140.819 145.632 141.329 146.28 ;
     RECT  141.293 149.184 141.329 149.208 ;
     RECT  141.257 194.976 141.329 202.632 ;
     RECT  141.145 150.432 141.347 154.488 ;
     RECT  141.107 165.84 141.347 193.8 ;
     RECT  141.145 237.312 141.349 237.336 ;
     RECT  139.813 239.808 141.349 240.12 ;
     RECT  141.289 137.76 141.401 138.6 ;
     RECT  141.347 151.296 141.437 154.488 ;
     RECT  141.349 236.736 141.437 237.336 ;
     RECT  141.349 238.848 141.437 240.12 ;
     RECT  140.929 218.64 141.469 220.248 ;
     RECT  141.437 151.296 141.473 152.904 ;
     RECT  141.293 204.288 141.509 208.056 ;
     RECT  141.257 209.088 141.509 209.304 ;
     RECT  141.109 135.888 141.541 136.776 ;
     RECT  140.533 158.352 141.541 158.376 ;
     RECT  141.109 159.456 141.541 159.48 ;
     RECT  141.473 151.296 141.545 151.368 ;
     RECT  141.301 212.688 141.545 214.2 ;
     RECT  141.469 218.592 141.613 220.248 ;
     RECT  140.849 160.992 141.617 164.808 ;
     RECT  140.249 155.616 141.649 155.64 ;
     RECT  140.285 157.296 141.649 157.368 ;
     RECT  141.617 162.336 141.649 164.808 ;
     RECT  141.613 218.544 141.649 220.248 ;
     RECT  141.329 194.976 141.653 198.456 ;
     RECT  141.545 213.12 141.653 214.2 ;
     RECT  141.649 155.616 141.689 157.368 ;
     RECT  141.541 158.352 141.689 159.48 ;
     RECT  141.653 213.36 141.689 214.2 ;
     RECT  140.533 226.464 141.689 227.016 ;
     RECT  140.609 217.152 141.721 217.32 ;
     RECT  141.689 159.168 141.797 159.48 ;
     RECT  141.541 135.648 141.829 136.776 ;
     RECT  141.329 146.256 141.829 146.28 ;
     RECT  141.473 152.88 141.833 152.904 ;
     RECT  141.301 215.568 141.901 215.592 ;
     RECT  141.721 216.576 141.901 217.32 ;
     RECT  141.325 223.392 141.901 223.416 ;
     RECT  141.829 134.592 141.925 136.776 ;
     RECT  141.437 239.088 141.973 240.12 ;
     RECT  140.812 230.976 142.081 231 ;
     RECT  141.185 233.088 142.081 233.112 ;
     RECT  142.009 234.192 142.081 234.216 ;
     RECT  141.973 239.088 142.081 240.168 ;
     RECT  141.005 210.672 142.225 211.128 ;
     RECT  141.685 142.176 142.261 142.2 ;
     RECT  141.329 199.536 142.297 202.632 ;
     RECT  140.812 229.632 142.297 229.656 ;
     RECT  141.437 236.976 142.297 237.336 ;
     RECT  142.225 149.952 142.309 149.976 ;
     RECT  141.401 138.576 142.333 138.6 ;
     RECT  142.309 149.376 142.333 149.976 ;
     RECT  141.797 159.36 142.333 159.48 ;
     RECT  141.617 160.992 142.333 161.016 ;
     RECT  142.225 144.528 142.357 144.552 ;
     RECT  141.829 146.256 142.357 147.096 ;
     RECT  141.347 165.84 142.405 174.024 ;
     RECT  142.081 233.088 142.405 234.216 ;
     RECT  141.653 195.024 142.441 198.456 ;
     RECT  142.297 199.536 142.441 202.92 ;
     RECT  142.225 210.672 142.477 211.32 ;
     RECT  142.261 141.936 142.501 142.2 ;
     RECT  142.297 229.632 142.501 229.704 ;
     RECT  142.081 230.976 142.501 231.864 ;
     RECT  141.509 209.088 142.513 209.208 ;
     RECT  142.477 210.528 142.513 211.32 ;
     RECT  142.405 232.944 142.513 234.216 ;
     RECT  142.513 209.088 142.556 211.32 ;
     RECT  142.549 212.304 142.556 212.328 ;
     RECT  141.347 175.392 142.597 193.8 ;
     RECT  142.333 149.376 142.604 150.024 ;
     RECT  142.597 175.392 142.621 193.848 ;
     RECT  141.509 204.288 142.621 208.008 ;
     RECT  142.556 209.088 142.621 212.328 ;
     RECT  141.649 162.336 142.652 164.856 ;
     RECT  142.405 165.84 142.652 174.072 ;
     RECT  142.501 141.84 142.693 142.2 ;
     RECT  142.333 159.36 142.693 161.016 ;
     RECT  141.689 226.656 142.693 227.016 ;
     RECT  142.081 239.088 142.693 240.504 ;
     RECT  142.477 242.256 142.693 242.28 ;
     RECT  142.501 229.632 142.729 231.864 ;
     RECT  141.689 214.176 142.801 214.2 ;
     RECT  142.693 131.616 142.808 131.64 ;
     RECT  142.693 132.672 142.808 132.696 ;
     RECT  141.925 133.68 142.808 136.776 ;
     RECT  142.333 138.576 142.808 138.936 ;
     RECT  142.693 141.84 142.808 143.016 ;
     RECT  142.357 144.528 142.808 147.096 ;
     RECT  142.604 149.28 142.808 150.024 ;
     RECT  141.545 151.344 142.808 151.368 ;
     RECT  141.437 153.888 142.808 154.488 ;
     RECT  141.689 155.616 142.808 157.032 ;
     RECT  142.693 159.36 142.808 161.112 ;
     RECT  142.652 162.336 142.808 174.072 ;
     RECT  142.621 175.392 142.808 193.944 ;
     RECT  142.441 195.024 142.808 202.92 ;
     RECT  142.621 204.288 142.808 212.328 ;
     RECT  142.801 213.648 142.808 214.2 ;
     RECT  141.901 215.568 142.808 217.32 ;
     RECT  141.649 218.304 142.808 220.248 ;
     RECT  142.153 222.24 142.808 222.264 ;
     RECT  141.901 223.296 142.808 223.416 ;
     RECT  142.433 224.784 142.808 224.808 ;
     RECT  142.693 226.08 142.808 227.016 ;
     RECT  142.632 228.048 142.808 228.072 ;
     RECT  142.729 229.056 142.808 231.864 ;
     RECT  142.513 232.848 142.808 234.216 ;
     RECT  142.297 236.976 142.808 237.912 ;
     RECT  142.693 239.088 142.808 241.032 ;
     RECT  142.693 242.016 142.808 242.28 ;
     RECT  142.808 2.148 142.912 369.372 ;
     RECT  142.912 2.418 143.104 369.102 ;
     RECT  143.104 152.16 143.201 214.296 ;
     RECT  143.104 229.056 143.219 233.208 ;
     RECT  143.219 231.312 143.237 233.208 ;
     RECT  143.104 215.28 143.309 216.6 ;
     RECT  143.201 152.16 143.381 211.512 ;
     RECT  143.104 134.496 143.417 136.056 ;
     RECT  143.381 152.16 143.453 157.512 ;
     RECT  143.104 217.728 143.489 222.36 ;
     RECT  143.104 228.048 143.489 228.072 ;
     RECT  143.104 240.48 143.525 240.504 ;
     RECT  143.489 217.728 143.596 221.64 ;
     RECT  143.381 158.496 143.605 211.512 ;
     RECT  143.453 152.16 143.633 154.872 ;
     RECT  143.104 131.616 143.669 131.64 ;
     RECT  143.104 241.536 143.669 242.04 ;
     RECT  143.417 134.496 143.677 134.52 ;
     RECT  143.104 140.784 143.699 143.352 ;
     RECT  143.104 144.336 143.699 147.096 ;
     RECT  143.605 158.496 143.705 211.32 ;
     RECT  143.705 159.12 143.733 211.32 ;
     RECT  143.699 140.784 143.741 143.016 ;
     RECT  143.104 149.376 143.741 151.032 ;
     RECT  143.104 236.88 143.741 236.904 ;
     RECT  143.453 156.192 143.777 157.512 ;
     RECT  143.699 145.872 143.813 147.096 ;
     RECT  143.596 218.832 143.813 221.64 ;
     RECT  143.104 223.632 143.813 224.808 ;
     RECT  143.201 212.64 143.885 214.296 ;
     RECT  143.417 135.648 143.939 136.056 ;
     RECT  143.741 142.992 143.939 143.016 ;
     RECT  143.813 223.824 143.939 224.808 ;
     RECT  143.741 140.784 143.965 141.864 ;
     RECT  143.965 141.648 143.985 141.864 ;
     RECT  143.309 215.28 143.993 216.312 ;
     RECT  143.733 159.12 144.035 210.984 ;
     RECT  143.104 226.128 144.065 227.016 ;
     RECT  143.633 152.16 144.083 152.664 ;
     RECT  143.633 153.648 144.083 154.872 ;
     RECT  144.083 152.64 144.137 152.664 ;
     RECT  143.237 231.312 144.205 231.432 ;
     RECT  143.237 232.416 144.205 233.208 ;
     RECT  143.104 138.816 144.245 139.704 ;
     RECT  143.219 229.056 144.245 230.328 ;
     RECT  143.939 224.448 144.277 224.808 ;
     RECT  144.065 226.128 144.277 226.872 ;
     RECT  143.741 150 144.281 151.032 ;
     RECT  144.035 159.984 144.281 205.272 ;
     RECT  144.205 231.312 144.317 233.208 ;
     RECT  143.104 238.224 144.353 238.248 ;
     RECT  143.699 144.336 144.421 144.36 ;
     RECT  144.245 229.632 144.421 230.328 ;
     RECT  144.317 231.312 144.421 232.44 ;
     RECT  143.939 136.032 144.461 136.056 ;
     RECT  144.281 160.032 144.497 205.272 ;
     RECT  143.596 217.728 144.565 217.752 ;
     RECT  144.083 153.744 144.605 154.872 ;
     RECT  144.421 133.392 144.661 133.416 ;
     RECT  144.245 138.816 144.677 139.512 ;
     RECT  143.813 145.872 144.709 145.992 ;
     RECT  144.385 233.52 144.709 233.544 ;
     RECT  143.104 235.056 144.709 235.08 ;
     RECT  144.097 236.304 144.709 236.328 ;
     RECT  144.529 237.744 144.709 237.768 ;
     RECT  143.885 212.784 144.745 214.296 ;
     RECT  143.993 215.28 144.745 215.64 ;
     RECT  144.709 233.52 144.755 237.768 ;
     RECT  144.661 133.392 144.785 134.04 ;
     RECT  144.755 235.584 144.796 235.608 ;
     RECT  144.755 236.832 144.796 236.856 ;
     RECT  144.421 144.192 144.817 144.36 ;
     RECT  144.709 145.344 144.817 145.992 ;
     RECT  144.605 153.936 144.821 154.872 ;
     RECT  144.277 224.448 144.893 226.872 ;
     RECT  143.777 157.296 144.901 157.32 ;
     RECT  144.889 158.544 144.901 158.568 ;
     RECT  144.565 217.728 144.925 218.328 ;
     RECT  143.813 219.312 144.925 221.64 ;
     RECT  144.133 137.376 144.929 137.4 ;
     RECT  144.817 144.192 144.929 145.992 ;
     RECT  144.893 224.448 144.929 225.24 ;
     RECT  144.853 222.864 144.937 222.888 ;
     RECT  143.669 241.536 144.961 241.56 ;
     RECT  144.901 157.296 145.034 158.568 ;
     RECT  144.925 217.728 145.037 221.64 ;
     RECT  144.755 234.24 145.037 234.264 ;
     RECT  144.497 199.536 145.045 205.272 ;
     RECT  143.104 239.376 145.093 239.4 ;
     RECT  145.045 199.536 145.1 205.32 ;
     RECT  144.035 206.304 145.1 210.984 ;
     RECT  144.929 145.584 145.105 145.992 ;
     RECT  144.497 160.032 145.109 198.12 ;
     RECT  144.961 241.104 145.139 241.56 ;
     RECT  145.093 239.376 145.145 239.688 ;
     RECT  144.997 148.224 145.177 148.248 ;
     RECT  145.145 239.664 145.18 239.688 ;
     RECT  145.034 157.296 145.181 158.52 ;
     RECT  144.745 212.784 145.181 215.64 ;
     RECT  144.281 150.432 145.213 151.032 ;
     RECT  145.069 152.736 145.213 152.76 ;
     RECT  144.785 133.392 145.217 133.416 ;
     RECT  145.1 199.536 145.244 210.984 ;
     RECT  145.177 148.224 145.325 149.064 ;
     RECT  145.244 199.536 145.331 211.512 ;
     RECT  145.181 213.072 145.357 215.64 ;
     RECT  145.213 150.432 145.361 151.416 ;
     RECT  145.037 219.312 145.379 221.64 ;
     RECT  144.421 229.632 145.379 232.44 ;
     RECT  143.985 141.648 145.393 141.672 ;
     RECT  144.929 144.192 145.393 144.6 ;
     RECT  144.677 139.104 145.397 139.512 ;
     RECT  145.139 241.536 145.397 241.56 ;
     RECT  143.777 156.192 145.429 156.216 ;
     RECT  145.325 148.224 145.465 148.248 ;
     RECT  145.393 143.952 145.469 144.6 ;
     RECT  145.465 148.032 145.505 148.248 ;
     RECT  145.361 150.48 145.505 151.416 ;
     RECT  145.357 213.072 145.505 216.12 ;
     RECT  144.893 226.32 145.505 226.872 ;
     RECT  145.429 155.232 145.516 156.216 ;
     RECT  145.331 199.536 145.523 210.936 ;
     RECT  145.516 155.712 145.525 156.216 ;
     RECT  145.181 157.296 145.525 158.424 ;
     RECT  145.105 145.584 145.532 146.28 ;
     RECT  145.379 229.92 145.537 232.44 ;
     RECT  145.505 226.752 145.541 226.872 ;
     RECT  145.213 152.736 145.573 152.952 ;
     RECT  144.821 153.936 145.573 153.96 ;
     RECT  145.537 229.92 145.577 232.68 ;
     RECT  145.525 155.712 145.613 158.424 ;
     RECT  145.532 145.584 145.619 146.664 ;
     RECT  145.037 217.728 145.669 217.992 ;
     RECT  145.321 135.552 145.681 135.576 ;
     RECT  145.109 160.032 145.685 193.704 ;
     RECT  145.669 216.96 145.756 217.992 ;
     RECT  145.393 140.832 145.757 141.672 ;
     RECT  145.469 143.952 145.789 144.552 ;
     RECT  145.523 199.536 145.801 210.216 ;
     RECT  145.505 151.008 145.811 151.416 ;
     RECT  145.109 194.784 145.82 198.12 ;
     RECT  145.801 204.144 145.829 210.216 ;
     RECT  145.789 143.664 145.901 144.552 ;
     RECT  145.685 160.032 145.901 185.4 ;
     RECT  145.82 194.784 145.907 198.504 ;
     RECT  145.501 212.016 145.907 212.04 ;
     RECT  145.505 213.072 145.907 215.16 ;
     RECT  145.789 222.144 145.933 222.168 ;
     RECT  145.861 131.088 145.945 131.928 ;
     RECT  145.397 139.104 145.969 139.128 ;
     RECT  145.573 152.736 145.973 153.96 ;
     RECT  145.829 204.144 145.973 209.88 ;
     RECT  145.901 160.032 146.005 185.352 ;
     RECT  145.756 217.152 146.041 217.992 ;
     RECT  145.379 219.312 146.041 221.112 ;
     RECT  145.973 204.24 146.045 209.88 ;
     RECT  144.929 224.448 146.077 224.616 ;
     RECT  145.541 226.848 146.081 226.872 ;
     RECT  145.811 151.392 146.113 151.416 ;
     RECT  145.973 152.736 146.113 152.76 ;
     RECT  145.969 227.952 146.113 227.976 ;
     RECT  145.933 222.144 146.117 222.888 ;
     RECT  145.901 143.952 146.153 144.552 ;
     RECT  145.577 230.16 146.153 232.68 ;
     RECT  146.153 230.832 146.189 232.68 ;
     RECT  145.613 157.296 146.221 158.424 ;
     RECT  146.005 159.552 146.221 185.352 ;
     RECT  145.685 186.528 146.221 193.704 ;
     RECT  145.907 194.784 146.221 197.976 ;
     RECT  146.153 144.192 146.297 144.552 ;
     RECT  145.505 148.032 146.329 148.104 ;
     RECT  145.801 199.536 146.329 202.968 ;
     RECT  146.221 157.296 146.333 185.352 ;
     RECT  146.221 186.528 146.369 197.976 ;
     RECT  145.945 131.904 146.405 131.928 ;
     RECT  146.333 157.776 146.405 185.352 ;
     RECT  146.405 157.776 146.428 182.952 ;
     RECT  145.681 135.552 146.437 135.672 ;
     RECT  146.329 147.84 146.437 148.104 ;
     RECT  145.907 213.072 146.473 213.144 ;
     RECT  146.405 183.936 146.477 185.352 ;
     RECT  146.113 227.664 146.485 227.976 ;
     RECT  145.969 138.96 146.545 139.128 ;
     RECT  146.428 157.776 146.549 158.184 ;
     RECT  145.907 214.272 146.653 215.16 ;
     RECT  146.077 224.448 146.653 225.336 ;
     RECT  146.437 147.744 146.657 148.104 ;
     RECT  146.297 144.528 146.725 144.552 ;
     RECT  145.613 155.712 146.725 156.216 ;
     RECT  146.428 159.168 146.729 182.952 ;
     RECT  146.369 195.024 146.819 197.976 ;
     RECT  146.477 184.08 146.837 185.352 ;
     RECT  146.657 147.84 146.909 148.104 ;
     RECT  146.653 224.448 146.941 226.296 ;
     RECT  146.437 135.216 146.972 135.672 ;
     RECT  146.725 136.656 146.972 136.68 ;
     RECT  146.329 199.056 146.972 202.968 ;
     RECT  146.041 217.152 146.981 221.112 ;
     RECT  146.972 134.64 147.013 136.68 ;
     RECT  146.113 151.392 147.013 152.76 ;
     RECT  145.973 153.888 147.013 153.96 ;
     RECT  146.972 198.816 147.049 202.968 ;
     RECT  146.905 132.48 147.059 132.504 ;
     RECT  146.581 133.584 147.059 133.608 ;
     RECT  147.013 134.64 147.059 137.064 ;
     RECT  147.049 198.816 147.059 203.064 ;
     RECT  146.189 230.832 147.059 231.864 ;
     RECT  146.653 234.288 147.059 234.312 ;
     RECT  146.437 236.496 147.061 236.52 ;
     RECT  147.013 151.392 147.085 153.96 ;
     RECT  146.941 223.968 147.085 226.296 ;
     RECT  147.061 236.496 147.107 236.76 ;
     RECT  146.545 138.432 147.121 139.128 ;
     RECT  146.725 144.528 147.121 145.176 ;
     RECT  146.045 204.672 147.121 209.88 ;
     RECT  146.117 222.144 147.125 222.36 ;
     RECT  147.049 238.848 147.133 238.872 ;
     RECT  147.121 204.624 147.193 209.88 ;
     RECT  147.059 136.656 147.197 137.064 ;
     RECT  147.121 144.528 147.229 145.32 ;
     RECT  146.977 149.136 147.301 149.16 ;
     RECT  147.085 150.432 147.301 153.96 ;
     RECT  146.725 155.712 147.308 156.456 ;
     RECT  147.229 144.528 147.337 145.656 ;
     RECT  147.059 198.912 147.445 203.064 ;
     RECT  147.193 204.576 147.445 209.88 ;
     RECT  146.473 212.832 147.445 213.144 ;
     RECT  147.197 137.04 147.452 137.064 ;
     RECT  147.121 138.432 147.452 140.04 ;
     RECT  146.837 184.08 147.517 185.016 ;
     RECT  147.085 223.968 147.548 226.44 ;
     RECT  147.301 149.136 147.553 153.96 ;
     RECT  146.653 214.272 147.553 215.496 ;
     RECT  147.553 214.272 147.625 216.024 ;
     RECT  147.553 149.136 147.769 154.008 ;
     RECT  147.308 155.136 147.769 156.456 ;
     RECT  146.729 160.752 147.805 182.952 ;
     RECT  147.517 183.984 147.805 185.016 ;
     RECT  146.369 186.528 147.805 193.704 ;
     RECT  146.819 195.024 147.805 197.832 ;
     RECT  146.797 141.84 147.829 141.864 ;
     RECT  147.337 144.24 147.829 145.656 ;
     RECT  147.548 223.872 147.877 226.44 ;
     RECT  147.805 160.752 147.949 185.016 ;
     RECT  147.125 222.144 147.949 222.168 ;
     RECT  147.877 230.736 147.985 230.76 ;
     RECT  146.653 237.84 147.985 237.864 ;
     RECT  146.981 217.152 148.021 220.632 ;
     RECT  147.949 221.664 148.021 222.168 ;
     RECT  147.769 149.136 148.057 156.456 ;
     RECT  148.057 149.136 148.201 156.504 ;
     RECT  147.949 160.752 148.201 185.16 ;
     RECT  147.805 186.528 148.201 197.832 ;
     RECT  147.445 198.912 148.201 209.88 ;
     RECT  147.059 231.792 148.201 231.816 ;
     RECT  146.725 232.944 148.201 233.112 ;
     RECT  147.452 137.04 148.208 140.04 ;
     RECT  147.829 141.312 148.208 145.656 ;
     RECT  146.909 148.08 148.208 148.104 ;
     RECT  148.201 149.136 148.208 156.792 ;
     RECT  146.549 157.776 148.208 157.8 ;
     RECT  146.729 159.168 148.208 159.48 ;
     RECT  148.201 160.56 148.208 185.16 ;
     RECT  148.201 186.528 148.208 209.88 ;
     RECT  147.445 212.832 148.208 213.192 ;
     RECT  147.625 214.224 148.208 216.024 ;
     RECT  148.021 217.152 148.208 222.168 ;
     RECT  147.877 223.392 148.208 226.44 ;
     RECT  146.485 227.664 148.208 228.792 ;
     RECT  147.985 229.872 148.208 230.76 ;
     RECT  148.201 231.792 148.208 233.112 ;
     RECT  147.877 234.816 148.208 234.84 ;
     RECT  147.107 236.736 148.208 236.76 ;
     RECT  147.985 237.84 148.208 238.2 ;
     RECT  148.208 2.148 148.312 369.372 ;
     RECT  148.312 2.418 148.504 369.102 ;
     RECT  148.504 156.432 148.529 156.792 ;
     RECT  148.504 168.336 148.529 173.256 ;
     RECT  148.504 146.4 148.565 148.104 ;
     RECT  148.504 149.76 148.565 152.184 ;
     RECT  148.504 212.64 148.565 213.432 ;
     RECT  148.504 217.776 148.565 222.072 ;
     RECT  148.504 144.24 148.601 144.264 ;
     RECT  148.504 214.512 148.601 216.552 ;
     RECT  148.565 218.304 148.637 222.072 ;
     RECT  148.565 146.448 148.643 148.104 ;
     RECT  148.504 183.936 148.643 188.808 ;
     RECT  148.504 225.792 148.643 226.632 ;
     RECT  148.643 183.936 148.673 188.712 ;
     RECT  148.673 184.272 148.681 188.712 ;
     RECT  148.643 147.456 148.691 148.104 ;
     RECT  148.691 147.792 148.709 148.104 ;
     RECT  148.681 184.272 148.745 188.616 ;
     RECT  148.504 199.44 148.745 207.144 ;
     RECT  148.565 150.384 148.781 152.184 ;
     RECT  148.504 208.176 148.781 209.88 ;
     RECT  148.504 142.944 148.817 142.968 ;
     RECT  148.565 212.64 148.925 213.192 ;
     RECT  148.637 221.04 148.925 222.072 ;
     RECT  148.504 227.952 148.925 227.976 ;
     RECT  148.745 199.44 148.931 199.992 ;
     RECT  148.504 197.76 148.961 198.36 ;
     RECT  148.745 184.464 148.979 188.616 ;
     RECT  148.504 230.256 148.989 233.112 ;
     RECT  148.504 153.504 149.033 154.056 ;
     RECT  148.504 174.384 149.033 182.04 ;
     RECT  148.931 199.44 149.123 199.464 ;
     RECT  148.504 157.824 149.141 167.256 ;
     RECT  148.529 168.432 149.141 173.256 ;
     RECT  148.745 201.216 149.177 207.144 ;
     RECT  149.141 165.024 149.285 167.256 ;
     RECT  149.177 203.424 149.285 207.144 ;
     RECT  148.601 214.752 149.321 216.552 ;
     RECT  148.529 156.48 149.363 156.792 ;
     RECT  148.504 234.336 149.363 234.888 ;
     RECT  149.177 201.216 149.401 202.344 ;
     RECT  149.363 156.48 149.429 156.504 ;
     RECT  149.141 157.824 149.537 163.56 ;
     RECT  148.925 222.048 149.557 222.072 ;
     RECT  148.504 223.392 149.557 224.76 ;
     RECT  149.557 222.048 149.564 224.76 ;
     RECT  148.643 225.792 149.564 225.816 ;
     RECT  148.989 230.256 149.603 232.584 ;
     RECT  148.781 150.48 149.651 152.184 ;
     RECT  149.603 230.64 149.651 232.584 ;
     RECT  149.033 174.384 149.677 176.664 ;
     RECT  149.321 215.088 149.681 216.552 ;
     RECT  148.504 190.176 149.753 196.008 ;
     RECT  148.643 146.448 149.785 146.472 ;
     RECT  149.033 177.84 149.785 182.04 ;
     RECT  148.961 197.76 149.785 197.976 ;
     RECT  148.781 209.856 149.785 209.88 ;
     RECT  149.753 190.176 149.788 192.552 ;
     RECT  148.709 148.08 149.845 148.104 ;
     RECT  149.651 150.48 149.845 150.984 ;
     RECT  149.033 153.6 149.845 154.056 ;
     RECT  149.749 155.616 149.845 155.64 ;
     RECT  149.753 193.68 149.857 196.008 ;
     RECT  149.785 197.52 149.857 197.976 ;
     RECT  148.504 140.688 149.861 141.288 ;
     RECT  149.845 153.6 149.861 155.64 ;
     RECT  149.651 231.888 149.861 232.584 ;
     RECT  149.861 153.744 149.891 155.64 ;
     RECT  149.285 165.072 149.897 167.256 ;
     RECT  148.925 212.976 149.929 213.192 ;
     RECT  149.845 149.952 149.932 150.984 ;
     RECT  149.891 153.888 149.932 155.64 ;
     RECT  149.537 157.824 149.933 158.664 ;
     RECT  149.929 212.976 149.948 214.104 ;
     RECT  148.637 218.304 149.965 219.336 ;
     RECT  149.363 234.336 149.965 234.36 ;
     RECT  148.979 184.464 149.969 188.376 ;
     RECT  149.285 203.472 150.001 207.144 ;
     RECT  148.781 208.176 150.001 208.392 ;
     RECT  149.932 150.48 150.005 150.984 ;
     RECT  149.788 191.472 150.005 192.552 ;
     RECT  149.965 234.24 150.005 234.36 ;
     RECT  149.681 216.48 150.037 216.552 ;
     RECT  149.141 168.432 150.041 172.92 ;
     RECT  149.681 215.088 150.041 215.112 ;
     RECT  149.861 141.264 150.073 141.288 ;
     RECT  149.821 142.608 150.073 142.632 ;
     RECT  149.677 174.24 150.073 176.664 ;
     RECT  149.785 177.84 150.073 182.904 ;
     RECT  149.969 184.56 150.113 188.376 ;
     RECT  148.925 221.04 150.113 221.064 ;
     RECT  149.401 201.216 150.133 202.248 ;
     RECT  148.504 139.104 150.14 139.224 ;
     RECT  150.113 184.848 150.149 188.376 ;
     RECT  150.001 203.472 150.179 208.392 ;
     RECT  150.073 141.264 150.181 142.632 ;
     RECT  149.605 143.76 150.181 143.784 ;
     RECT  149.564 222.048 150.188 225.816 ;
     RECT  150.181 141.264 150.217 143.784 ;
     RECT  150.188 221.712 150.221 225.816 ;
     RECT  150.14 139.104 150.227 139.32 ;
     RECT  149.785 146.448 150.236 146.52 ;
     RECT  150.227 139.104 150.257 139.224 ;
     RECT  149.965 218.016 150.257 219.336 ;
     RECT  150.217 141.264 150.275 143.88 ;
     RECT  150.221 221.712 150.275 221.736 ;
     RECT  149.845 148.08 150.289 148.728 ;
     RECT  150.037 216.48 150.293 216.696 ;
     RECT  150.229 140.208 150.316 140.232 ;
     RECT  150.275 141.648 150.323 143.88 ;
     RECT  150.236 146.448 150.323 146.664 ;
     RECT  150.221 222.768 150.329 225.816 ;
     RECT  149.651 230.64 150.329 230.664 ;
     RECT  148.504 237.936 150.329 237.96 ;
     RECT  150.149 185.808 150.361 188.376 ;
     RECT  149.788 190.176 150.361 190.344 ;
     RECT  150.293 216.672 150.365 216.696 ;
     RECT  150.325 226.848 150.389 226.968 ;
     RECT  149.897 167.184 150.397 167.256 ;
     RECT  150.041 168.624 150.397 172.92 ;
     RECT  150.073 174.24 150.397 182.904 ;
     RECT  148.504 236.688 150.397 236.712 ;
     RECT  149.932 154.992 150.433 155.64 ;
     RECT  150.257 218.352 150.433 219.336 ;
     RECT  150.361 185.808 150.437 190.344 ;
     RECT  150.323 146.448 150.473 146.472 ;
     RECT  150.437 185.808 150.473 189.288 ;
     RECT  150.329 222.768 150.473 224.52 ;
     RECT  150.389 226.272 150.473 226.968 ;
     RECT  150.397 168.624 150.481 182.904 ;
     RECT  150.289 147.792 150.508 148.728 ;
     RECT  150.323 141.648 150.509 142.248 ;
     RECT  150.508 147.744 150.509 148.728 ;
     RECT  150.005 150.48 150.509 150.504 ;
     RECT  149.897 165.072 150.509 166.2 ;
     RECT  149.933 158.544 150.515 158.664 ;
     RECT  150.179 203.472 150.515 203.688 ;
     RECT  150.473 226.944 150.528 226.968 ;
     RECT  148.504 145.344 150.541 145.368 ;
     RECT  149.785 209.808 150.541 210.12 ;
     RECT  150.005 234.24 150.541 234.264 ;
     RECT  149.861 231.888 150.545 231.912 ;
     RECT  149.537 159.648 150.577 163.56 ;
     RECT  149.857 193.68 150.577 197.976 ;
     RECT  150.541 145.344 150.581 145.512 ;
     RECT  150.541 234.096 150.581 234.264 ;
     RECT  150.541 209.808 150.613 210.264 ;
     RECT  150.577 159.648 150.617 164.232 ;
     RECT  150.473 186.336 150.617 189.288 ;
     RECT  150.437 190.272 150.617 190.344 ;
     RECT  150.325 220.656 150.617 220.68 ;
     RECT  149.651 152.16 150.653 152.184 ;
     RECT  150.133 201.12 150.653 202.248 ;
     RECT  149.948 212.832 150.685 214.104 ;
     RECT  150.509 165.312 150.689 166.2 ;
     RECT  150.397 236.4 150.689 236.712 ;
     RECT  150.577 193.68 150.757 198.264 ;
     RECT  150.433 154.992 150.761 156.024 ;
     RECT  150.515 203.664 150.761 203.688 ;
     RECT  150.685 212.352 150.797 214.104 ;
     RECT  150.433 218.352 150.797 219.672 ;
     RECT  150.757 193.632 150.865 198.792 ;
     RECT  150.689 236.64 150.869 236.712 ;
     RECT  149.932 153.888 150.901 154.008 ;
     RECT  150.761 154.992 150.901 155.016 ;
     RECT  150.515 158.544 150.937 158.568 ;
     RECT  150.865 193.632 150.949 199.416 ;
     RECT  150.613 209.808 150.973 210.36 ;
     RECT  150.481 174.24 150.977 182.904 ;
     RECT  150.617 159.648 150.995 161.88 ;
     RECT  150.005 191.568 150.997 192.552 ;
     RECT  150.761 156 151.007 156.024 ;
     RECT  150.397 167.184 151.009 167.496 ;
     RECT  150.481 168.624 151.009 172.92 ;
     RECT  150.581 234.096 151.009 234.12 ;
     RECT  150.973 209.376 151.013 210.36 ;
     RECT  150.997 190.896 151.043 192.552 ;
     RECT  150.179 204.72 151.043 208.392 ;
     RECT  150.797 212.352 151.049 213.192 ;
     RECT  150.653 201.12 151.081 202.056 ;
     RECT  150.949 193.632 151.084 199.272 ;
     RECT  151.007 156 151.085 156.168 ;
     RECT  151.009 233.952 151.085 234.12 ;
     RECT  150.901 153.888 151.091 155.016 ;
     RECT  151.091 153.888 151.157 154.296 ;
     RECT  150.995 159.648 151.193 159.912 ;
     RECT  150.869 236.64 151.193 236.664 ;
     RECT  150.977 177.888 151.265 182.904 ;
     RECT  151.196 215.04 151.283 215.064 ;
     RECT  151.084 193.632 151.292 198.792 ;
     RECT  150.473 224.016 151.301 224.52 ;
     RECT  151.193 159.792 151.337 159.912 ;
     RECT  150.509 142.224 151.369 142.248 ;
     RECT  151.043 205.104 151.409 208.392 ;
     RECT  151.085 233.952 151.409 233.976 ;
     RECT  151.333 216.048 151.417 216.072 ;
     RECT  151.297 141.12 151.427 141.144 ;
     RECT  151.265 179.232 151.427 182.904 ;
     RECT  150.581 145.488 151.441 145.512 ;
     RECT  151.157 153.888 151.441 153.912 ;
     RECT  151.369 142.224 151.453 142.536 ;
     RECT  151.049 212.64 151.453 213.192 ;
     RECT  151.085 156.144 151.481 156.168 ;
     RECT  150.977 174.24 151.481 176.664 ;
     RECT  151.261 204.048 151.481 204.072 ;
     RECT  151.409 205.248 151.481 207.096 ;
     RECT  148.504 229.152 151.481 229.176 ;
     RECT  150.973 150.624 151.517 150.648 ;
     RECT  151.481 174.384 151.517 176.664 ;
     RECT  151.481 205.248 151.517 206.856 ;
     RECT  151.427 179.232 151.553 179.4 ;
     RECT  151.427 180.576 151.553 182.904 ;
     RECT  150.797 218.352 151.553 219.336 ;
     RECT  150.323 143.856 151.585 143.88 ;
     RECT  150.617 163.2 151.585 164.232 ;
     RECT  151.517 205.248 151.589 206.376 ;
     RECT  151.441 145.488 151.621 145.944 ;
     RECT  151.553 180.624 151.621 182.904 ;
     RECT  151.477 184.08 151.621 184.104 ;
     RECT  151.549 149.856 151.661 149.88 ;
     RECT  150.617 186.336 151.661 188.664 ;
     RECT  151.292 193.2 151.661 198.792 ;
     RECT  151.409 208.224 151.661 208.392 ;
     RECT  151.081 200.496 151.697 202.056 ;
     RECT  150.689 165.744 151.717 166.2 ;
     RECT  151.621 145.488 151.733 146.52 ;
     RECT  150.995 161.232 151.733 161.88 ;
     RECT  150.509 147.744 151.765 147.768 ;
     RECT  151.585 143.856 151.769 144.264 ;
     RECT  151.733 145.488 151.769 145.944 ;
     RECT  151.009 167.184 151.769 172.92 ;
     RECT  151.013 209.376 151.802 209.448 ;
     RECT  151.453 212.736 151.841 213.192 ;
     RECT  150.473 222.768 151.841 222.84 ;
     RECT  151.661 193.2 151.877 198.456 ;
     RECT  151.717 165.264 151.909 166.2 ;
     RECT  151.769 167.184 151.909 168.696 ;
     RECT  151.841 222.816 151.913 222.84 ;
     RECT  151.043 190.896 151.945 192.168 ;
     RECT  151.453 142.224 151.949 142.248 ;
     RECT  151.585 230.208 151.985 230.232 ;
     RECT  151.585 163.056 152.005 164.232 ;
     RECT  151.909 165.264 152.005 168.696 ;
     RECT  152.012 228.72 152.053 228.744 ;
     RECT  151.621 225.84 152.057 225.864 ;
     RECT  152.005 163.056 152.092 168.696 ;
     RECT  152.053 227.952 152.099 228.744 ;
     RECT  151.945 190.368 152.149 192.168 ;
     RECT  151.877 193.2 152.149 195.672 ;
     RECT  152.149 190.368 152.161 195.672 ;
     RECT  150.937 158.304 152.197 158.568 ;
     RECT  151.265 177.888 152.197 178.008 ;
     RECT  151.661 186.336 152.197 186.36 ;
     RECT  152.161 189.888 152.236 195.672 ;
     RECT  152.236 189.888 152.237 192.648 ;
     RECT  152.237 189.888 152.273 191.544 ;
     RECT  151.301 224.496 152.273 224.52 ;
     RECT  151.441 152.976 152.305 153.912 ;
     RECT  151.733 161.328 152.305 161.88 ;
     RECT  152.092 163.056 152.305 163.992 ;
     RECT  151.765 147.744 152.345 147.864 ;
     RECT  151.621 180.624 152.345 184.104 ;
     RECT  152.236 193.68 152.381 195.672 ;
     RECT  151.769 169.824 152.449 172.92 ;
     RECT  152.449 169.824 152.453 172.968 ;
     RECT  152.345 181.584 152.453 184.104 ;
     RECT  152.089 216.624 152.453 217.272 ;
     RECT  151.769 143.856 152.489 143.88 ;
     RECT  151.517 174.384 152.489 176.472 ;
     RECT  151.553 219.312 152.557 219.336 ;
     RECT  152.305 161.328 152.561 163.992 ;
     RECT  152.557 159.696 152.593 159.72 ;
     RECT  152.557 218.784 152.597 219.336 ;
     RECT  152.305 155.856 152.629 155.88 ;
     RECT  152.489 176.16 152.665 176.472 ;
     RECT  152.197 177.696 152.665 178.008 ;
     RECT  151.841 212.736 152.732 212.952 ;
     RECT  152.273 189.888 152.737 191.256 ;
     RECT  152.665 176.16 152.773 178.008 ;
     RECT  152.453 217.248 152.773 217.272 ;
     RECT  152.597 218.784 152.773 218.856 ;
     RECT  152.561 161.328 152.821 163.896 ;
     RECT  151.661 188.592 152.845 188.616 ;
     RECT  152.737 189.6 152.845 191.256 ;
     RECT  152.381 194.592 152.917 195.672 ;
     RECT  151.877 197.088 152.917 198.456 ;
     RECT  152.305 152.112 152.953 153.912 ;
     RECT  152.197 157.824 152.953 158.568 ;
     RECT  152.593 159.696 152.953 160.2 ;
     RECT  151.553 179.376 153.061 179.4 ;
     RECT  152.876 180.576 153.061 180.6 ;
     RECT  152.233 199.824 153.097 199.848 ;
     RECT  152.732 212.016 153.097 212.952 ;
     RECT  152.917 194.592 153.116 198.456 ;
     RECT  153.097 199.536 153.116 199.848 ;
     RECT  152.773 176.16 153.133 178.056 ;
     RECT  153.061 179.376 153.133 180.6 ;
     RECT  151.589 205.248 153.133 205.272 ;
     RECT  151.589 206.352 153.133 206.376 ;
     RECT  153.116 194.592 153.157 199.848 ;
     RECT  151.697 201.12 153.157 201.816 ;
     RECT  152.629 155.856 153.205 156.024 ;
     RECT  153.133 205.248 153.26 206.376 ;
     RECT  152.489 174.384 153.277 174.408 ;
     RECT  153.097 212.016 153.277 213.192 ;
     RECT  152.345 147.744 153.349 147.768 ;
     RECT  152.053 149.04 153.349 149.784 ;
     RECT  153.205 155.856 153.349 156.504 ;
     RECT  152.953 157.824 153.349 160.2 ;
     RECT  153.157 194.592 153.349 201.816 ;
     RECT  151.945 202.848 153.349 202.872 ;
     RECT  153.277 225.168 153.349 225.192 ;
     RECT  152.197 186.24 153.385 186.36 ;
     RECT  151.661 187.344 153.385 187.368 ;
     RECT  153.26 204.288 153.385 206.376 ;
     RECT  153.349 225.168 153.452 225.336 ;
     RECT  153.349 147.744 153.493 149.784 ;
     RECT  153.213 150.864 153.493 150.888 ;
     RECT  152.953 152.112 153.493 154.488 ;
     RECT  152.629 222.864 153.493 222.888 ;
     RECT  150.257 139.104 153.608 139.128 ;
     RECT  151.769 145.488 153.608 145.512 ;
     RECT  153.493 147.744 153.608 154.488 ;
     RECT  153.349 155.856 153.608 160.2 ;
     RECT  152.821 161.184 153.608 163.896 ;
     RECT  152.092 165.264 153.608 168.696 ;
     RECT  152.453 169.872 153.608 172.968 ;
     RECT  153.277 174.048 153.608 174.408 ;
     RECT  153.133 176.16 153.608 180.6 ;
     RECT  152.453 181.584 153.608 182.904 ;
     RECT  152.453 184.08 153.608 184.104 ;
     RECT  153.385 186.24 153.608 187.368 ;
     RECT  152.845 188.592 153.608 191.256 ;
     RECT  153.452 192.768 153.608 192.792 ;
     RECT  153.349 194.592 153.608 202.872 ;
     RECT  153.385 203.952 153.608 206.376 ;
     RECT  151.661 208.224 153.608 208.248 ;
     RECT  151.802 209.424 153.608 209.448 ;
     RECT  153.277 211.056 153.608 213.192 ;
     RECT  152.773 217.248 153.608 218.856 ;
     RECT  152.629 220.752 153.608 220.776 ;
     RECT  153.493 222.864 153.608 223.128 ;
     RECT  153.452 224.4 153.608 225.336 ;
     RECT  152.305 226.368 153.608 226.392 ;
     RECT  152.099 227.952 153.608 228.696 ;
     RECT  153.608 2.148 153.712 369.372 ;
     RECT  153.712 2.418 153.904 369.102 ;
     RECT  153.904 165.024 153.965 168.696 ;
     RECT  153.904 201.792 153.965 201.816 ;
     RECT  153.904 146.448 154.019 146.472 ;
     RECT  153.904 152.64 154.037 152.664 ;
     RECT  153.904 193.728 154.145 196.056 ;
     RECT  153.904 162 154.181 163.464 ;
     RECT  153.904 147.744 154.217 147.768 ;
     RECT  153.904 153.696 154.217 157.224 ;
     RECT  153.904 174.048 154.253 178.008 ;
     RECT  153.904 223.2 154.289 223.224 ;
     RECT  154.217 153.696 154.307 156.504 ;
     RECT  153.904 149.76 154.325 150.504 ;
     RECT  154.145 193.728 154.325 193.752 ;
     RECT  154.307 156.48 154.361 156.504 ;
     RECT  153.965 165.024 154.361 167.064 ;
     RECT  153.904 172.896 154.361 172.968 ;
     RECT  153.904 158.976 154.499 160.296 ;
     RECT  154.253 174.336 154.505 178.008 ;
     RECT  153.904 181.776 154.577 182.904 ;
     RECT  153.904 213.6 154.577 213.672 ;
     RECT  153.965 168.672 154.613 168.696 ;
     RECT  153.904 200.688 154.613 200.712 ;
     RECT  154.505 174.912 154.721 178.008 ;
     RECT  153.904 210.912 154.729 211.368 ;
     RECT  154.499 159.696 154.757 160.296 ;
     RECT  153.904 179.376 154.757 180.024 ;
     RECT  153.904 202.896 154.865 202.92 ;
     RECT  153.904 203.952 154.865 204.072 ;
     RECT  153.904 189.696 154.897 191.496 ;
     RECT  154.577 213.648 154.937 213.672 ;
     RECT  154.577 181.776 154.94 182.424 ;
     RECT  154.757 159.792 154.969 160.296 ;
     RECT  154.181 162 154.969 162.696 ;
     RECT  154.729 210.96 154.969 211.368 ;
     RECT  154.145 194.832 154.981 196.056 ;
     RECT  153.904 197.28 154.981 197.4 ;
     RECT  154.94 181.152 155.027 182.424 ;
     RECT  154.897 189.696 155.027 191.544 ;
     RECT  154.981 194.832 155.027 197.4 ;
     RECT  155.027 182.016 155.045 182.424 ;
     RECT  153.904 207.168 155.075 209.16 ;
     RECT  154.865 204.048 155.081 204.072 ;
     RECT  155.075 208.32 155.081 209.16 ;
     RECT  153.904 185.568 155.113 185.592 ;
     RECT  155.075 207.168 155.116 207.192 ;
     RECT  154.721 174.912 155.117 176.712 ;
     RECT  155.113 184.656 155.141 185.592 ;
     RECT  153.904 169.872 155.153 171.912 ;
     RECT  153.904 218.256 155.153 218.808 ;
     RECT  155.005 188.64 155.189 188.664 ;
     RECT  155.113 183.408 155.219 183.432 ;
     RECT  155.141 184.656 155.225 185.832 ;
     RECT  155.153 218.496 155.257 218.808 ;
     RECT  155.027 189.696 155.297 190.92 ;
     RECT  154.757 179.376 155.333 179.496 ;
     RECT  155.117 174.912 155.369 176.376 ;
     RECT  153.904 187.488 155.369 187.512 ;
     RECT  154.969 210.96 155.369 211.992 ;
     RECT  154.361 165.312 155.405 167.064 ;
     RECT  155.225 185.568 155.441 185.832 ;
     RECT  154.307 153.696 155.473 155.064 ;
     RECT  155.473 153.408 155.507 155.064 ;
     RECT  154.325 150.48 155.513 150.504 ;
     RECT  155.507 153.408 155.513 154.44 ;
     RECT  155.027 196.608 155.585 196.632 ;
     RECT  155.297 190.896 155.603 190.92 ;
     RECT  155.557 193.104 155.644 193.416 ;
     RECT  155.401 164.304 155.701 164.328 ;
     RECT  155.405 165.312 155.701 165.576 ;
     RECT  155.153 169.92 155.729 171.912 ;
     RECT  154.969 159.792 155.747 162.696 ;
     RECT  155.747 160.272 155.797 162.696 ;
     RECT  155.701 164.304 155.797 165.576 ;
     RECT  154.721 177.984 155.797 178.008 ;
     RECT  155.329 156.96 155.801 156.984 ;
     RECT  155.797 160.272 155.801 165.576 ;
     RECT  155.653 189.408 155.801 189.528 ;
     RECT  155.081 208.32 155.801 208.776 ;
     RECT  155.257 218.496 155.801 219.576 ;
     RECT  155.581 206.64 155.833 206.664 ;
     RECT  155.027 194.832 155.905 195.576 ;
     RECT  155.801 160.272 155.945 162.024 ;
     RECT  155.797 177.984 155.977 178.392 ;
     RECT  155.833 206.064 155.981 206.664 ;
     RECT  155.797 216.384 156.013 216.408 ;
     RECT  155.833 180.72 156.017 180.744 ;
     RECT  155.801 218.736 156.017 219.576 ;
     RECT  155.801 208.32 156.049 208.344 ;
     RECT  155.945 160.8 156.053 162.024 ;
     RECT  155.801 163.488 156.125 165.576 ;
     RECT  155.905 194.352 156.125 195.576 ;
     RECT  156.013 216.384 156.125 216.456 ;
     RECT  156.013 186.384 156.161 186.408 ;
     RECT  155.045 182.016 156.193 182.28 ;
     RECT  155.833 183.264 156.193 183.288 ;
     RECT  155.977 177.984 156.197 178.44 ;
     RECT  155.513 153.408 156.233 153.72 ;
     RECT  155.369 211.344 156.269 211.992 ;
     RECT  156.125 194.4 156.301 195.576 ;
     RECT  155.981 206.64 156.305 206.664 ;
     RECT  156.125 216.432 156.305 216.456 ;
     RECT  155.797 199.632 156.373 199.656 ;
     RECT  156.373 199.632 156.409 200.136 ;
     RECT  156.193 181.968 156.445 183.288 ;
     RECT  156.265 184.8 156.445 184.824 ;
     RECT  156.301 194.4 156.485 196.488 ;
     RECT  155.369 174.912 156.589 174.936 ;
     RECT  155.369 176.16 156.661 176.376 ;
     RECT  156.197 177.984 156.661 178.392 ;
     RECT  156.409 199.632 156.665 200.28 ;
     RECT  156.085 168.912 156.697 168.936 ;
     RECT  156.589 174.864 156.737 174.936 ;
     RECT  156.445 181.968 156.737 184.824 ;
     RECT  156.697 168.864 156.845 168.936 ;
     RECT  155.545 155.952 156.86 155.976 ;
     RECT  156.86 155.424 156.901 155.976 ;
     RECT  156.125 163.68 156.908 165.576 ;
     RECT  155.405 166.608 156.908 167.064 ;
     RECT  156.901 155.424 156.947 156.264 ;
     RECT  156.908 163.68 156.949 167.064 ;
     RECT  156.661 176.16 156.953 178.392 ;
     RECT  156.661 189.168 156.953 189.192 ;
     RECT  156.949 163.68 156.995 167.592 ;
     RECT  156.805 190.416 157.025 190.44 ;
     RECT  156.053 160.8 157.052 161.256 ;
     RECT  156.877 210.336 157.061 210.36 ;
     RECT  156.049 208.224 157.091 208.344 ;
     RECT  157.093 159.504 157.165 159.72 ;
     RECT  157.196 187.824 157.229 187.848 ;
     RECT  157.052 160.704 157.273 161.256 ;
     RECT  157.201 162.336 157.273 162.36 ;
     RECT  155.437 214.752 157.273 214.776 ;
     RECT  156.845 168.912 157.309 168.936 ;
     RECT  155.729 169.968 157.309 171.912 ;
     RECT  156.949 185.808 157.313 185.832 ;
     RECT  157.229 187.248 157.313 187.848 ;
     RECT  156.737 181.968 157.349 183.384 ;
     RECT  156.017 218.736 157.385 218.808 ;
     RECT  156.737 184.8 157.457 184.824 ;
     RECT  156.485 194.4 157.561 194.424 ;
     RECT  156.485 195.504 157.561 196.488 ;
     RECT  156.737 174.912 157.565 174.936 ;
     RECT  157.273 190.32 157.565 190.344 ;
     RECT  156.269 211.344 157.601 211.368 ;
     RECT  157.273 160.704 157.633 162.36 ;
     RECT  157.273 213.936 157.637 214.776 ;
     RECT  155.977 157.92 157.717 157.944 ;
     RECT  156.953 177.984 157.745 178.392 ;
     RECT  156.947 156.24 157.763 156.264 ;
     RECT  156.953 176.16 157.781 176.376 ;
     RECT  157.349 181.968 157.849 182.328 ;
     RECT  157.165 158.976 157.853 159.72 ;
     RECT  156.995 166.608 157.868 167.592 ;
     RECT  157.309 168.912 157.868 171.912 ;
     RECT  155.333 179.472 157.868 179.496 ;
     RECT  157.849 181.104 157.868 182.328 ;
     RECT  157.349 183.36 157.909 183.384 ;
     RECT  157.909 183.36 157.921 183.768 ;
     RECT  157.868 166.608 157.955 171.912 ;
     RECT  157.868 179.472 157.955 182.328 ;
     RECT  157.921 183.36 157.955 184.296 ;
     RECT  157.717 157.248 157.957 157.944 ;
     RECT  157.955 181.824 157.961 182.328 ;
     RECT  157.021 191.52 157.961 191.544 ;
     RECT  157.637 214.32 157.961 214.776 ;
     RECT  157.955 183.744 157.996 184.296 ;
     RECT  156.665 199.632 158.033 200.232 ;
     RECT  157.961 214.368 158.033 214.776 ;
     RECT  157.955 168.576 158.101 171.912 ;
     RECT  154.361 172.896 158.101 172.92 ;
     RECT  157.561 194.4 158.137 196.488 ;
     RECT  157.885 197.664 158.137 197.688 ;
     RECT  157.091 208.224 158.137 208.248 ;
     RECT  155.644 193.104 158.173 193.128 ;
     RECT  158.137 208.224 158.209 208.632 ;
     RECT  158.245 186.864 158.389 186.888 ;
     RECT  157.957 156.672 158.425 157.944 ;
     RECT  158.389 186.864 158.461 186.936 ;
     RECT  158.425 191.856 158.485 191.88 ;
     RECT  158.173 193.104 158.485 193.176 ;
     RECT  158.033 214.752 158.485 214.776 ;
     RECT  158.485 191.856 158.497 193.416 ;
     RECT  158.137 194.4 158.497 197.688 ;
     RECT  157.561 154.224 158.54 154.248 ;
     RECT  158.033 199.632 158.569 199.656 ;
     RECT  157.745 177.984 158.713 178.008 ;
     RECT  157.781 176.352 158.749 176.376 ;
     RECT  157.849 216.72 158.749 216.744 ;
     RECT  157.955 179.472 158.785 179.496 ;
     RECT  157.921 174.336 158.857 174.36 ;
     RECT  158.101 168.576 158.869 172.92 ;
     RECT  158.857 174.048 158.869 174.36 ;
     RECT  156.995 163.68 158.965 165.576 ;
     RECT  157.955 166.608 158.965 167.496 ;
     RECT  153.904 139.104 159.008 139.128 ;
     RECT  158.54 154.224 159.008 155.208 ;
     RECT  158.425 156.672 159.008 158.664 ;
     RECT  157.853 159.696 159.008 159.72 ;
     RECT  157.633 160.704 159.008 162.408 ;
     RECT  158.965 163.68 159.008 167.496 ;
     RECT  158.869 168.576 159.008 174.36 ;
     RECT  158.749 175.92 159.008 176.376 ;
     RECT  158.713 177.792 159.008 178.008 ;
     RECT  158.785 179.376 159.008 179.496 ;
     RECT  157.961 182.112 159.008 182.328 ;
     RECT  157.996 184.272 159.008 184.296 ;
     RECT  158.341 185.28 159.008 185.304 ;
     RECT  158.461 186.864 159.008 186.984 ;
     RECT  157.849 188.016 159.008 188.04 ;
     RECT  158.684 190.8 159.008 190.824 ;
     RECT  158.497 191.856 159.008 197.688 ;
     RECT  158.569 198.96 159.008 199.656 ;
     RECT  158.137 201.216 159.008 201.24 ;
     RECT  158.065 205.824 159.008 205.848 ;
     RECT  158.209 208.224 159.008 209.256 ;
     RECT  158.485 214.752 159.008 215.4 ;
     RECT  158.749 216.72 159.008 217.176 ;
     RECT  157.385 218.736 159.008 218.76 ;
     RECT  159.008 2.148 159.112 369.372 ;
     RECT  159.112 2.418 159.304 369.102 ;
     RECT  159.304 157.488 159.401 158.664 ;
     RECT  159.401 157.488 159.437 158.088 ;
     RECT  159.304 194.4 159.437 195.624 ;
     RECT  159.304 172.896 159.473 175.176 ;
     RECT  159.304 186.336 159.509 186.936 ;
     RECT  159.437 157.488 159.581 157.512 ;
     RECT  159.304 167.184 159.617 171.912 ;
     RECT  159.509 186.336 159.653 186.456 ;
     RECT  159.473 174.72 159.761 175.176 ;
     RECT  159.304 177.792 159.869 180.744 ;
     RECT  159.304 161.904 160.013 162.408 ;
     RECT  159.869 177.792 160.121 180.264 ;
     RECT  159.304 188.64 160.163 188.664 ;
     RECT  159.304 211.2 160.193 211.512 ;
     RECT  160.193 211.2 160.229 211.224 ;
     RECT  159.304 190.32 160.265 192.072 ;
     RECT  159.304 181.776 160.297 182.616 ;
     RECT  159.653 186.336 160.301 186.408 ;
     RECT  159.437 194.4 160.301 194.76 ;
     RECT  160.297 181.776 160.309 182.904 ;
     RECT  160.265 190.32 160.348 190.968 ;
     RECT  159.304 204.576 160.409 204.6 ;
     RECT  159.304 201.456 160.445 201.48 ;
     RECT  159.304 176.352 160.453 176.712 ;
     RECT  160.405 196.608 160.489 196.632 ;
     RECT  160.412 204.048 160.499 204.072 ;
     RECT  159.304 217.728 160.499 217.752 ;
     RECT  160.121 177.792 160.525 180.168 ;
     RECT  160.477 200.688 160.589 200.712 ;
     RECT  160.013 162.384 160.613 162.408 ;
     RECT  160.309 182.112 160.625 182.904 ;
     RECT  160.613 162.384 160.652 163.032 ;
     RECT  159.304 164.496 160.652 166.104 ;
     RECT  160.652 162.384 160.691 166.104 ;
     RECT  160.691 163.008 160.697 166.104 ;
     RECT  160.697 163.536 160.739 166.104 ;
     RECT  160.625 182.112 160.769 182.328 ;
     RECT  159.473 172.896 160.844 173.16 ;
     RECT  159.761 174.72 160.844 174.744 ;
     RECT  160.265 192.048 160.913 192.072 ;
     RECT  160.301 194.496 160.913 194.76 ;
     RECT  160.844 172.896 160.931 174.744 ;
     RECT  160.913 194.736 160.985 194.76 ;
     RECT  160.301 186.384 161.036 186.408 ;
     RECT  161.036 186.384 161.123 187.32 ;
     RECT  160.333 210.912 161.123 210.936 ;
     RECT  161.084 200.16 161.125 200.568 ;
     RECT  161.125 199.248 161.171 200.568 ;
     RECT  160.453 176.112 161.228 176.712 ;
     RECT  160.525 177.792 161.228 179.592 ;
     RECT  159.617 167.184 161.237 168.936 ;
     RECT  161.123 186.384 161.269 186.408 ;
     RECT  161.171 200.544 161.273 200.568 ;
     RECT  161.228 176.016 161.315 179.592 ;
     RECT  161.089 203.616 161.345 203.64 ;
     RECT  160.739 165.024 161.413 166.104 ;
     RECT  161.237 167.184 161.413 168.6 ;
     RECT  160.931 172.896 161.453 172.92 ;
     RECT  161.171 199.248 161.453 199.272 ;
     RECT  161.125 202.416 161.453 202.44 ;
     RECT  160.769 182.304 161.525 182.328 ;
     RECT  161.413 165.024 161.651 168.6 ;
     RECT  159.617 169.968 161.737 171.912 ;
     RECT  161.269 185.808 161.741 186.408 ;
     RECT  161.315 176.352 161.777 179.592 ;
     RECT  161.701 197.424 161.845 197.448 ;
     RECT  160.348 190.32 161.849 190.344 ;
     RECT  160.945 192.576 161.885 192.6 ;
     RECT  161.777 177.984 161.891 179.592 ;
     RECT  161.845 197.184 161.891 198.408 ;
     RECT  161.651 165.024 161.921 165.768 ;
     RECT  161.651 166.8 161.957 166.824 ;
     RECT  161.891 197.184 161.993 197.208 ;
     RECT  161.741 186.096 162.029 186.12 ;
     RECT  161.651 168.576 162.065 168.6 ;
     RECT  161.891 198.384 162.101 198.408 ;
     RECT  160.931 174.72 162.677 174.744 ;
     RECT  162.493 190.08 162.785 190.104 ;
     RECT  161.891 178.992 162.857 179.016 ;
     RECT  161.737 169.968 162.929 172.344 ;
     RECT  161.891 177.984 162.961 178.008 ;
     RECT  162.961 177.984 163.001 178.44 ;
     RECT  161.485 180.672 163.177 180.696 ;
     RECT  162.929 172.32 163.333 172.344 ;
     RECT  163.321 175.008 163.405 175.032 ;
     RECT  161.921 165.024 164.408 165.048 ;
     RECT  162.929 169.968 164.408 171.336 ;
     RECT  163.333 172.32 164.408 173.064 ;
     RECT  161.777 176.352 164.408 176.376 ;
     RECT  163.001 178.416 164.408 178.44 ;
     RECT  163.177 180.144 164.408 180.696 ;
     RECT  163.621 181.776 164.408 181.8 ;
     RECT  164.408 2.148 164.512 369.372 ;
     RECT  164.512 2.418 164.704 369.102 ;
     RECT  164.704 169.968 165.773 171.336 ;
     RECT  164.704 165.024 169.808 165.048 ;
     RECT  165.773 169.968 169.808 171.24 ;
     RECT  165.949 176.352 169.808 176.376 ;
     RECT  169.808 2.148 169.912 369.372 ;
     RECT  169.912 2.418 170.104 369.102 ;
     RECT  170.104 165.024 175.208 165.048 ;
     RECT  170.104 169.968 175.208 171.24 ;
     RECT  170.104 176.352 175.208 176.376 ;
     RECT  175.208 2.148 175.312 369.372 ;
     RECT  175.312 2.418 175.504 369.102 ;
     RECT  175.504 165.024 180.608 165.048 ;
     RECT  175.504 169.968 180.608 171.24 ;
     RECT  175.504 176.352 180.608 176.376 ;
     RECT  180.608 2.148 180.712 369.372 ;
     RECT  180.712 2.418 180.904 369.102 ;
     RECT  180.904 165.024 186.008 165.048 ;
     RECT  180.904 169.968 186.008 171.24 ;
     RECT  180.904 176.352 186.008 176.376 ;
     RECT  186.008 2.148 186.112 369.372 ;
     RECT  186.112 2.418 186.304 369.102 ;
     RECT  186.304 165.024 191.408 165.048 ;
     RECT  186.304 169.968 191.408 171.24 ;
     RECT  186.304 176.352 191.408 176.376 ;
     RECT  191.408 2.148 191.512 369.372 ;
     RECT  191.512 2.418 191.704 369.102 ;
     RECT  191.704 165.024 196.808 165.048 ;
     RECT  191.704 169.968 196.808 171.24 ;
     RECT  191.704 176.352 196.808 176.376 ;
     RECT  196.808 2.148 196.912 369.372 ;
     RECT  196.912 2.418 197.104 369.102 ;
     RECT  197.104 165.024 202.208 165.048 ;
     RECT  197.104 169.968 202.208 171.24 ;
     RECT  197.104 176.352 202.208 176.376 ;
     RECT  202.208 2.148 202.312 369.372 ;
     RECT  202.312 2.418 202.504 369.102 ;
     RECT  202.504 165.024 207.608 165.048 ;
     RECT  202.504 169.968 207.608 171.24 ;
     RECT  202.504 176.352 207.608 176.376 ;
     RECT  207.608 2.148 207.712 369.372 ;
     RECT  207.712 2.418 207.904 369.102 ;
     RECT  207.904 165.024 213.008 165.048 ;
     RECT  207.904 169.968 213.008 171.24 ;
     RECT  207.904 176.352 213.008 176.376 ;
     RECT  213.008 2.148 213.112 369.372 ;
     RECT  213.112 2.418 213.304 369.102 ;
     RECT  213.304 165.024 218.408 165.048 ;
     RECT  213.304 169.968 218.408 171.24 ;
     RECT  213.304 176.352 218.408 176.376 ;
     RECT  218.408 2.148 218.512 369.372 ;
     RECT  218.512 2.418 218.704 369.102 ;
     RECT  218.704 165.024 223.808 165.048 ;
     RECT  218.704 169.968 223.808 171.24 ;
     RECT  218.704 176.352 223.808 176.376 ;
     RECT  223.808 2.148 223.912 369.372 ;
     RECT  223.912 2.418 224.104 369.102 ;
     RECT  224.104 165.024 229.208 165.048 ;
     RECT  224.104 169.968 229.208 171.24 ;
     RECT  224.104 176.352 229.208 176.376 ;
     RECT  229.208 2.148 229.312 369.372 ;
     RECT  229.312 2.418 229.504 369.102 ;
     RECT  229.504 165.024 234.608 165.048 ;
     RECT  229.504 169.968 234.608 171.24 ;
     RECT  229.504 176.352 234.608 176.376 ;
     RECT  234.608 2.148 234.712 369.372 ;
     RECT  234.712 2.418 234.904 369.102 ;
     RECT  234.904 165.024 240.008 165.048 ;
     RECT  234.904 169.968 240.008 171.24 ;
     RECT  234.904 176.352 240.008 176.376 ;
     RECT  240.008 2.148 240.112 369.372 ;
     RECT  240.112 2.418 240.304 369.102 ;
     RECT  240.304 176.352 244.037 176.376 ;
     RECT  240.304 169.968 244.933 171.24 ;
     RECT  240.304 165.024 245.408 165.048 ;
     RECT  244.933 169.968 245.408 172.152 ;
     RECT  245.408 2.148 245.512 369.372 ;
     RECT  245.512 2.418 245.704 369.102 ;
     RECT  245.704 178.224 246.733 178.536 ;
     RECT  245.704 169.872 247.345 172.68 ;
     RECT  246.733 178.224 247.381 178.728 ;
     RECT  247.381 178.128 247.417 178.728 ;
     RECT  247.345 169.776 248.281 172.68 ;
     RECT  248.281 169.68 248.364 172.68 ;
     RECT  247.417 178.128 248.364 178.824 ;
    LAYER M5 ;
     RECT  2.4 2.137 2.52 2.151 ;
     RECT  7.8 2.137 7.92 2.151 ;
     RECT  13.2 2.137 13.32 2.151 ;
     RECT  18.6 2.137 18.72 2.151 ;
     RECT  24 2.137 24.12 2.151 ;
     RECT  29.4 2.137 29.52 2.151 ;
     RECT  34.8 2.137 34.92 2.151 ;
     RECT  40.2 2.137 40.32 2.151 ;
     RECT  45.6 2.137 45.72 2.151 ;
     RECT  51 2.137 51.12 2.151 ;
     RECT  56.4 2.137 56.52 2.151 ;
     RECT  61.8 2.137 61.92 2.151 ;
     RECT  67.2 2.137 67.32 2.151 ;
     RECT  72.6 2.137 72.72 2.151 ;
     RECT  78 2.137 78.12 2.151 ;
     RECT  83.4 2.137 83.52 2.151 ;
     RECT  88.8 2.137 88.92 2.151 ;
     RECT  94.2 2.137 94.32 2.151 ;
     RECT  99.6 2.137 99.72 2.151 ;
     RECT  105 2.137 105.12 2.151 ;
     RECT  110.4 2.137 110.52 2.151 ;
     RECT  115.8 2.137 115.92 2.151 ;
     RECT  121.2 2.137 121.32 2.151 ;
     RECT  126.6 2.137 126.72 2.151 ;
     RECT  132 2.137 132.12 2.151 ;
     RECT  137.4 2.137 137.52 2.151 ;
     RECT  142.8 2.137 142.92 2.151 ;
     RECT  148.2 2.137 148.32 2.151 ;
     RECT  153.6 2.137 153.72 2.151 ;
     RECT  159 2.137 159.12 2.151 ;
     RECT  164.4 2.137 164.52 2.151 ;
     RECT  169.8 2.137 169.92 2.151 ;
     RECT  175.2 2.137 175.32 2.151 ;
     RECT  180.6 2.137 180.72 2.151 ;
     RECT  186 2.137 186.12 2.151 ;
     RECT  191.4 2.137 191.52 2.151 ;
     RECT  196.8 2.137 196.92 2.151 ;
     RECT  202.2 2.137 202.32 2.151 ;
     RECT  207.6 2.137 207.72 2.151 ;
     RECT  213 2.137 213.12 2.151 ;
     RECT  218.4 2.137 218.52 2.151 ;
     RECT  223.8 2.137 223.92 2.151 ;
     RECT  229.2 2.137 229.32 2.151 ;
     RECT  234.6 2.137 234.72 2.151 ;
     RECT  240 2.137 240.12 2.151 ;
     RECT  245.4 2.137 245.52 2.151 ;
     RECT  142.8 2.151 143.112 131.605 ;
     RECT  145.872 131.077 145.896 131.939 ;
     RECT  142.704 131.605 143.112 133.669 ;
     RECT  144.672 133.381 144.696 134.051 ;
     RECT  140.208 131.557 140.232 134.099 ;
     RECT  137.4 2.151 137.712 134.485 ;
     RECT  141.936 133.669 143.112 134.485 ;
     RECT  141.936 134.485 143.64 134.627 ;
     RECT  142.8 134.627 143.64 135.637 ;
     RECT  136.656 134.485 137.712 136.165 ;
     RECT  142.08 135.637 143.928 136.787 ;
     RECT  147.024 132.469 147.048 137.029 ;
     RECT  148.2 2.151 148.512 137.029 ;
     RECT  147.024 137.029 148.512 137.075 ;
     RECT  134.448 137.893 134.472 138.565 ;
     RECT  136.176 136.165 137.712 139.091 ;
     RECT  159 2.151 159.312 139.093 ;
     RECT  134.448 138.565 134.52 139.139 ;
     RECT  136.176 139.091 136.2 139.139 ;
     RECT  134.448 139.139 134.472 139.235 ;
     RECT  147.504 137.075 148.512 139.235 ;
     RECT  147.696 139.235 148.512 140.051 ;
     RECT  150.192 139.285 150.216 140.197 ;
     RECT  139.68 138.421 139.704 140.243 ;
     RECT  142.8 136.787 143.928 140.819 ;
     RECT  148.08 140.051 148.512 141.301 ;
     RECT  150.192 140.197 150.264 141.683 ;
     RECT  142.8 140.819 143.64 141.829 ;
     RECT  142.512 141.829 143.928 141.971 ;
     RECT  142.8 141.971 143.928 143.027 ;
     RECT  150.192 141.683 150.216 143.029 ;
     RECT  150.192 143.029 150.312 143.075 ;
     RECT  139.968 141.301 139.992 143.269 ;
     RECT  139.968 143.269 140.136 143.315 ;
     RECT  151.392 141.109 151.416 143.891 ;
     RECT  140.112 143.315 140.136 144.227 ;
     RECT  147.84 141.301 148.512 145.141 ;
     RECT  142.8 143.027 143.688 145.285 ;
     RECT  144.72 145.333 144.744 145.573 ;
     RECT  142.368 145.285 143.688 146.245 ;
     RECT  153.6 2.151 153.912 146.437 ;
     RECT  140.784 145.621 140.808 146.485 ;
     RECT  140.208 146.485 140.808 146.531 ;
     RECT  142.32 146.245 143.688 146.531 ;
     RECT  151.632 145.909 151.656 146.531 ;
     RECT  147.312 145.141 148.512 146.677 ;
     RECT  137.4 139.091 137.712 146.773 ;
     RECT  147.312 146.677 148.632 147.445 ;
     RECT  153.6 146.437 154.008 147.779 ;
     RECT  147.312 147.445 148.68 147.827 ;
     RECT  144.72 145.573 145.608 148.067 ;
     RECT  147.312 147.827 148.632 148.115 ;
     RECT  153.6 147.779 153.912 148.117 ;
     RECT  140.208 146.531 140.232 148.165 ;
     RECT  150.288 143.075 150.312 148.165 ;
     RECT  140.208 148.165 140.856 148.211 ;
     RECT  137.4 146.773 138.504 148.883 ;
     RECT  140.832 148.211 140.856 149.411 ;
     RECT  153.36 148.117 153.912 149.749 ;
     RECT  134.976 149.797 135 149.845 ;
     RECT  137.4 148.883 138.024 150.323 ;
     RECT  142.32 146.531 143.64 150.421 ;
     RECT  144.72 148.067 144.744 150.421 ;
     RECT  133.344 148.213 133.368 150.515 ;
     RECT  153.264 149.749 153.912 150.899 ;
     RECT  134.976 149.845 135.144 150.901 ;
     RECT  142.32 150.421 145.272 150.997 ;
     RECT  147.312 148.115 148.512 151.139 ;
     RECT  141.312 150.421 141.336 151.331 ;
     RECT  134.544 150.901 135.144 151.333 ;
     RECT  142.32 150.997 145.8 151.333 ;
     RECT  149.856 148.165 150.312 151.381 ;
     RECT  132 2.151 132.312 151.573 ;
     RECT  148.2 151.139 148.512 151.573 ;
     RECT  149.616 151.381 150.312 151.573 ;
     RECT  131.904 151.573 132.312 152.101 ;
     RECT  153.504 150.899 153.912 152.101 ;
     RECT  148.2 151.573 150.312 152.149 ;
     RECT  134.544 151.333 135.48 152.483 ;
     RECT  131.904 152.101 133.128 152.819 ;
     RECT  139.392 151.909 139.416 153.157 ;
     RECT  139.392 153.157 139.656 153.203 ;
     RECT  132 152.819 133.128 153.395 ;
     RECT  135.456 152.483 135.48 153.395 ;
     RECT  152.736 152.101 153.912 153.395 ;
     RECT  137.4 150.323 137.712 153.589 ;
     RECT  142.176 151.333 145.8 153.877 ;
     RECT  147.36 152.149 150.312 154.019 ;
     RECT  152.976 153.395 153.912 154.213 ;
     RECT  141.84 153.877 145.8 154.259 ;
     RECT  141.84 154.259 143.64 154.499 ;
     RECT  152.976 154.213 154.296 154.499 ;
     RECT  136.8 153.589 137.712 154.549 ;
     RECT  139.632 153.203 139.656 154.691 ;
     RECT  134.208 153.397 134.232 154.981 ;
     RECT  155.472 154.405 155.496 155.075 ;
     RECT  130.56 155.173 130.584 155.603 ;
     RECT  147.36 154.019 149.88 155.651 ;
     RECT  133.824 154.981 134.232 155.653 ;
     RECT  153.6 154.499 154.296 155.845 ;
     RECT  153.36 155.845 154.296 155.891 ;
     RECT  151.056 154.981 151.08 156.179 ;
     RECT  136.8 154.549 138.36 156.227 ;
     RECT  156.912 155.413 156.936 156.229 ;
     RECT  158.592 139.093 159.312 156.229 ;
     RECT  156.912 156.229 159.312 156.275 ;
     RECT  133.296 155.653 134.232 156.803 ;
     RECT  137.4 156.227 138.36 156.803 ;
     RECT  139.344 155.173 139.368 156.803 ;
     RECT  157.728 156.275 159.312 157.523 ;
     RECT  147.36 155.651 149.64 157.811 ;
     RECT  128.736 156.133 128.76 157.907 ;
     RECT  132 153.395 132.312 157.909 ;
     RECT  157.728 157.523 157.752 157.955 ;
     RECT  144.72 154.259 145.8 158.485 ;
     RECT  131.664 157.909 132.312 158.531 ;
     RECT  153.36 155.891 153.912 158.533 ;
     RECT  136.176 156.709 136.2 158.579 ;
     RECT  148.2 157.811 149.64 158.629 ;
     RECT  137.4 156.803 137.712 158.965 ;
     RECT  152.832 158.533 153.912 158.965 ;
     RECT  142.368 154.499 143.64 159.109 ;
     RECT  144.72 158.485 146.376 159.109 ;
     RECT  142.368 159.109 146.376 159.541 ;
     RECT  152.832 158.965 154.488 159.731 ;
     RECT  129.552 158.965 129.576 160.067 ;
     RECT  142.368 159.541 146.472 160.067 ;
     RECT  148.2 158.629 150.504 160.117 ;
     RECT  137.4 158.965 138.552 160.211 ;
     RECT  105 2.151 105.312 160.693 ;
     RECT  126.6 2.151 126.912 160.693 ;
     RECT  130.848 160.021 130.872 160.787 ;
     RECT  148.2 160.117 150.984 160.981 ;
     RECT  140.208 160.165 140.232 161.603 ;
     RECT  99.6 2.151 99.912 161.845 ;
     RECT  137.4 160.211 137.712 161.845 ;
     RECT  147.936 160.981 150.984 161.891 ;
     RECT  126.6 160.693 127.032 161.939 ;
     RECT  123.024 160.693 123.048 162.181 ;
     RECT  122.64 162.181 123.048 162.227 ;
     RECT  134.208 156.803 134.232 162.229 ;
     RECT  142.368 160.067 143.64 162.469 ;
     RECT  128.784 161.653 128.808 162.515 ;
     RECT  140.592 161.845 140.616 162.515 ;
     RECT  104.88 160.693 105.312 162.899 ;
     RECT  144.72 160.067 146.472 162.899 ;
     RECT  160.656 162.373 160.68 163.043 ;
     RECT  134.208 162.229 134.808 163.187 ;
     RECT  136.896 161.845 137.712 163.427 ;
     RECT  105 162.899 105.312 163.429 ;
     RECT  152.832 159.731 153.912 163.525 ;
     RECT  99.504 161.845 99.912 163.763 ;
     RECT  142.32 162.469 143.64 163.861 ;
     RECT  144.72 162.899 145.8 163.861 ;
     RECT  99.6 163.763 99.912 164.053 ;
     RECT  137.4 163.427 137.712 164.053 ;
     RECT  132 158.531 132.312 164.101 ;
     RECT  130.608 161.269 130.632 164.149 ;
     RECT  99.6 164.053 100.008 164.197 ;
     RECT  106.848 163.285 106.872 164.339 ;
     RECT  142.32 163.861 145.8 164.339 ;
     RECT  103.728 163.525 103.752 164.435 ;
     RECT  105 163.429 105.528 164.531 ;
     RECT  147.936 161.891 150.648 164.677 ;
     RECT  130.608 164.149 130.68 164.821 ;
     RECT  132 164.101 132.84 164.821 ;
     RECT  137.4 164.053 137.928 165.059 ;
     RECT  147.648 164.677 150.648 165.059 ;
     RECT  155.712 159.781 155.736 165.059 ;
     RECT  152.016 163.525 153.912 165.253 ;
     RECT  151.728 165.253 153.912 165.299 ;
     RECT  130.608 164.821 132.84 165.347 ;
     RECT  147.936 165.059 150.648 165.347 ;
     RECT  157.104 159.493 157.128 165.347 ;
     RECT  122.64 162.227 122.664 165.443 ;
     RECT  130.608 165.347 132.312 165.539 ;
     RECT  142.656 164.339 145.8 165.637 ;
     RECT  160.704 163.525 160.728 165.733 ;
     RECT  99.6 164.197 100.296 165.829 ;
     RECT  130.608 165.539 130.632 165.829 ;
     RECT  159 157.523 159.312 165.829 ;
     RECT  140.88 164.773 140.904 165.923 ;
     RECT  142.656 165.637 146.088 165.923 ;
     RECT  151.728 165.299 151.752 165.923 ;
     RECT  124.992 161.845 125.016 165.971 ;
     RECT  155.04 165.301 155.064 165.971 ;
     RECT  130.464 165.829 130.632 166.115 ;
     RECT  160.704 165.733 161.64 166.115 ;
     RECT  114.384 164.677 114.408 166.117 ;
     RECT  114.384 166.117 114.552 166.163 ;
     RECT  152.88 165.299 153.912 166.211 ;
     RECT  147.936 165.347 150.504 166.213 ;
     RECT  103.824 165.157 103.848 166.261 ;
     RECT  105 164.531 105.312 166.261 ;
     RECT  103.824 166.261 105.312 166.307 ;
     RECT  139.056 165.877 139.08 166.403 ;
     RECT  142.656 165.923 145.8 166.405 ;
     RECT  96.912 165.157 96.936 166.451 ;
     RECT  137.4 165.059 137.712 166.453 ;
     RECT  130.464 166.115 130.488 166.741 ;
     RECT  134.784 163.187 134.808 166.741 ;
     RECT  137.4 166.453 137.976 166.789 ;
     RECT  98.64 165.829 100.296 166.931 ;
     RECT  137.4 166.789 138.024 166.981 ;
     RECT  147.504 166.213 150.504 167.171 ;
     RECT  102.384 166.261 102.408 167.363 ;
     RECT  104.256 166.307 105.312 167.363 ;
     RECT  134.784 166.741 135.144 167.509 ;
     RECT  136.32 165.253 136.344 167.509 ;
     RECT  137.4 166.981 138.12 167.509 ;
     RECT  126.6 161.939 126.912 167.557 ;
     RECT  124.8 166.981 124.824 167.603 ;
     RECT  156.96 165.733 156.984 167.603 ;
     RECT  141.888 166.405 145.8 167.651 ;
     RECT  142.656 167.651 145.8 167.749 ;
     RECT  152.976 166.211 153.912 168.085 ;
     RECT  131.808 165.539 132.312 168.133 ;
     RECT  139.488 167.461 139.512 168.133 ;
     RECT  108.528 163.525 108.552 168.323 ;
     RECT  142.656 167.749 146.568 168.419 ;
     RECT  134.784 167.509 138.12 168.613 ;
     RECT  139.248 168.133 139.512 168.613 ;
     RECT  95.76 168.085 95.784 168.707 ;
     RECT  142.8 168.419 146.568 168.755 ;
     RECT  159 165.829 159.576 168.755 ;
     RECT  99.6 166.931 100.296 168.805 ;
     RECT  134.784 168.613 139.512 168.997 ;
     RECT  110.4 2.151 110.712 169.045 ;
     RECT  126.6 167.557 127.128 169.045 ;
     RECT  96.768 168.421 96.792 169.283 ;
     RECT  124.512 168.133 124.536 169.331 ;
     RECT  131.808 168.133 132.6 169.331 ;
     RECT  157.92 168.277 157.944 169.331 ;
     RECT  134.448 168.997 139.512 169.429 ;
     RECT  140.592 168.949 140.616 169.429 ;
     RECT  147.936 167.171 150.504 169.813 ;
     RECT  152.784 168.085 153.912 169.907 ;
     RECT  157.008 170.005 157.032 170.149 ;
     RECT  99.6 168.805 100.92 170.195 ;
     RECT  156.912 170.149 157.032 170.195 ;
     RECT  134.448 169.429 140.616 170.243 ;
     RECT  156.912 170.195 156.936 170.291 ;
     RECT  142.8 168.755 146.52 170.389 ;
     RECT  164.4 2.151 164.712 170.581 ;
     RECT  110.4 169.045 111.048 170.773 ;
     RECT  134.784 170.243 140.616 170.773 ;
     RECT  134.784 170.773 141.24 170.819 ;
     RECT  126.6 169.045 127.512 170.821 ;
     RECT  131.808 169.331 132.312 170.869 ;
     RECT  105 167.363 105.312 170.965 ;
     RECT  142.8 170.389 146.616 170.965 ;
     RECT  140.592 170.819 141.24 171.061 ;
     RECT  161.616 166.115 161.64 171.299 ;
     RECT  131.808 170.869 132.504 171.349 ;
     RECT  106.512 165.829 106.536 171.491 ;
     RECT  122.544 170.437 122.568 171.539 ;
     RECT  131.808 171.349 133.176 171.539 ;
     RECT  99.6 170.195 100.344 171.635 ;
     RECT  126.6 170.821 127.656 171.635 ;
     RECT  142.656 170.965 146.616 171.781 ;
     RECT  134.784 170.819 139.512 171.877 ;
     RECT  140.592 171.061 141.336 171.877 ;
     RECT  153.6 169.907 153.912 171.877 ;
     RECT  109.44 170.773 111.048 171.923 ;
     RECT  151.776 170.245 151.8 171.923 ;
     RECT  152.88 171.877 153.912 172.019 ;
     RECT  129.84 166.741 130.488 172.163 ;
     RECT  134.784 171.877 141.336 172.309 ;
     RECT  142.32 171.781 146.616 172.309 ;
     RECT  95.712 170.149 95.736 172.355 ;
     RECT  163.632 170.581 164.712 172.355 ;
     RECT  134.784 172.309 146.616 172.837 ;
     RECT  133.92 172.837 146.616 173.029 ;
     RECT  147.936 169.813 150.792 173.029 ;
     RECT  105 170.965 105.528 173.221 ;
     RECT  130.368 172.163 130.488 173.221 ;
     RECT  102.576 172.069 102.6 173.363 ;
     RECT  159 168.755 159.312 173.509 ;
     RECT  131.808 171.539 132.504 173.557 ;
     RECT  133.92 173.029 150.792 173.557 ;
     RECT  104.88 173.221 105.528 173.699 ;
     RECT  126.6 171.635 126.912 173.749 ;
     RECT  107.76 173.221 107.784 174.181 ;
     RECT  107.136 174.181 107.784 174.227 ;
     RECT  125.664 173.749 126.912 174.229 ;
     RECT  158.88 173.509 159.312 174.371 ;
     RECT  160.896 173.125 160.92 174.709 ;
     RECT  97.488 172.885 97.512 174.755 ;
     RECT  160.896 174.709 161.304 174.755 ;
     RECT  163.344 173.029 163.368 175.043 ;
     RECT  104.88 173.699 105.312 175.427 ;
     RECT  131.808 173.557 150.792 175.573 ;
     RECT  107.136 174.227 107.16 175.619 ;
     RECT  99.6 171.635 99.912 175.957 ;
     RECT  94.2 2.151 94.512 176.101 ;
     RECT  161.28 174.755 161.304 176.101 ;
     RECT  125.664 174.229 127.032 176.195 ;
     RECT  129.6 173.221 130.488 176.339 ;
     RECT  109.44 171.923 110.712 176.389 ;
     RECT  97.728 176.101 97.752 176.581 ;
     RECT  99.6 175.957 100.728 176.677 ;
     RECT  103.008 175.477 103.032 176.677 ;
     RECT  114.528 166.163 114.552 176.723 ;
     RECT  124.512 171.301 124.536 176.725 ;
     RECT  109.44 176.389 110.856 176.963 ;
     RECT  160.464 176.101 161.304 177.205 ;
     RECT  94.2 176.101 94.68 177.299 ;
     RECT  103.008 176.677 103.512 177.781 ;
     RECT  126.6 176.195 127.032 177.875 ;
     RECT  124.512 176.725 125.448 177.925 ;
     RECT  123.648 177.925 125.448 177.971 ;
     RECT  97.344 176.581 97.752 178.019 ;
     RECT  160.464 177.205 161.592 178.019 ;
     RECT  107.664 176.917 107.688 178.261 ;
     RECT  129.984 176.339 130.488 178.307 ;
     RECT  94.2 177.299 94.512 178.357 ;
     RECT  107.664 178.261 107.784 178.357 ;
     RECT  99.6 176.677 101.448 178.451 ;
     RECT  123.648 177.971 124.536 178.451 ;
     RECT  161.568 178.019 161.592 178.451 ;
     RECT  99.6 178.451 100.728 178.547 ;
     RECT  107.52 178.357 107.784 178.643 ;
     RECT  97.728 178.019 97.752 178.645 ;
     RECT  107.664 178.643 107.784 179.027 ;
     RECT  102.624 177.781 103.512 179.077 ;
     RECT  102.624 179.077 103.752 179.123 ;
     RECT  105 175.427 105.312 179.173 ;
     RECT  107.664 179.027 107.688 179.219 ;
     RECT  161.856 178.885 161.88 179.603 ;
     RECT  131.808 175.573 151.32 179.605 ;
     RECT  103.728 179.123 103.752 180.179 ;
     RECT  160.464 178.019 160.488 180.179 ;
     RECT  95.712 177.733 95.736 180.227 ;
     RECT  94.2 178.357 94.632 180.325 ;
     RECT  97.728 178.645 97.8 180.421 ;
     RECT  99.6 178.547 99.912 180.421 ;
     RECT  110.4 176.963 110.856 180.563 ;
     RECT  153.6 172.019 153.912 180.565 ;
     RECT  93.408 180.325 94.632 180.661 ;
     RECT  104.736 179.173 105.312 180.661 ;
     RECT  124.512 178.451 124.536 180.661 ;
     RECT  126.6 177.875 126.912 180.661 ;
     RECT  130.464 178.307 130.488 180.661 ;
     RECT  131.808 179.605 151.416 180.661 ;
     RECT  164.4 172.355 164.712 180.661 ;
     RECT  97.728 180.421 98.088 180.755 ;
     RECT  93.408 180.661 95.352 181.043 ;
     RECT  129.648 180.661 130.488 181.187 ;
     RECT  123.648 180.661 124.536 181.619 ;
     RECT  94.2 181.043 95.352 181.765 ;
     RECT  159 174.371 159.312 181.765 ;
     RECT  163.632 180.661 164.712 181.811 ;
     RECT  108.816 180.325 108.84 181.859 ;
     RECT  131.808 180.661 151.656 181.859 ;
     RECT  97.728 180.755 97.752 182.293 ;
     RECT  99.168 180.421 99.912 182.293 ;
     RECT  94.2 181.765 95.736 182.339 ;
     RECT  159 181.765 160.296 182.339 ;
     RECT  0.144 181.813 0.168 182.387 ;
     RECT  95.712 182.339 95.736 182.435 ;
     RECT  154.992 181.141 155.016 182.435 ;
     RECT  126.6 180.661 127.704 182.723 ;
     RECT  102.624 179.123 102.648 182.771 ;
     RECT  104.736 180.661 105.96 183.109 ;
     RECT  104.736 183.109 106.68 183.155 ;
     RECT  132 181.859 151.656 183.155 ;
     RECT  129.888 181.187 130.488 183.397 ;
     RECT  124.512 181.619 124.536 183.493 ;
     RECT  97.728 182.293 99.912 183.587 ;
     RECT  98.688 183.587 99.912 183.635 ;
     RECT  157.92 180.133 157.944 183.779 ;
     RECT  104.736 183.155 105.432 184.163 ;
     RECT  104.736 184.163 105.312 184.211 ;
     RECT  159 182.339 159.312 184.261 ;
     RECT  106.656 183.155 106.68 184.499 ;
     RECT  132 183.155 151.176 184.691 ;
     RECT  129.552 183.397 130.488 184.739 ;
     RECT  99.6 183.635 99.912 184.885 ;
     RECT  124.512 183.493 124.824 185.315 ;
     RECT  132 184.691 133.464 185.315 ;
     RECT  158.352 184.261 159.312 185.315 ;
     RECT  130.464 184.739 130.488 185.653 ;
     RECT  108.528 183.781 108.552 185.843 ;
     RECT  155.184 183.397 155.208 185.843 ;
     RECT  99.6 184.885 100.248 185.891 ;
     RECT  132 185.315 132.456 186.131 ;
     RECT  132 186.131 132.408 186.371 ;
     RECT  133.44 185.315 133.464 186.419 ;
     RECT  130.464 185.653 130.584 186.613 ;
     RECT  126.6 182.723 126.912 186.805 ;
     RECT  159 185.315 159.312 186.853 ;
     RECT  99.6 185.891 99.912 186.901 ;
     RECT  130.368 186.613 130.584 186.901 ;
     RECT  132 186.371 132.312 186.901 ;
     RECT  124.512 185.315 124.536 186.947 ;
     RECT  158.496 186.853 159.312 186.995 ;
     RECT  105 184.211 105.312 187.477 ;
     RECT  152.928 180.565 153.912 187.477 ;
     RECT  99.6 186.901 100.344 187.523 ;
     RECT  157.248 187.237 157.272 187.859 ;
     RECT  130.368 186.901 132.312 188.147 ;
     RECT  95.76 187.477 95.784 188.483 ;
     RECT  159 186.995 159.312 188.629 ;
     RECT  161.088 187.285 161.112 188.629 ;
     RECT  102.48 187.477 102.504 188.819 ;
     RECT  104.4 187.477 105.312 188.819 ;
     RECT  134.784 184.691 151.176 189.205 ;
     RECT  130.368 188.147 130.584 189.347 ;
     RECT  123.36 188.293 123.384 189.445 ;
     RECT  124.608 187.477 124.632 189.445 ;
     RECT  123.36 189.445 124.632 189.491 ;
     RECT  99.6 187.523 99.912 189.589 ;
     RECT  123.36 189.491 124.296 189.875 ;
     RECT  128.88 188.053 128.904 189.877 ;
     RECT  97.44 189.205 97.464 189.923 ;
     RECT  130.368 189.347 130.488 190.355 ;
     RECT  96.096 189.829 96.12 190.451 ;
     RECT  128.256 189.877 128.904 190.451 ;
     RECT  134.448 189.205 151.176 190.451 ;
     RECT  152.928 187.477 154.824 190.501 ;
     RECT  159 188.629 161.112 190.789 ;
     RECT  124.272 189.875 124.296 190.835 ;
     RECT  152.928 190.501 155.016 190.885 ;
     RECT  102.288 189.445 102.312 190.979 ;
     RECT  128.256 190.451 128.712 191.267 ;
     RECT  99.6 189.589 100.584 191.507 ;
     RECT  152.928 190.885 155.592 191.507 ;
     RECT  134.784 190.451 151.176 191.555 ;
     RECT  154.992 191.507 155.592 191.555 ;
     RECT  126.6 186.805 127.08 192.325 ;
     RECT  130.464 190.355 130.488 192.421 ;
     RECT  132 188.147 132.312 192.421 ;
     RECT  152.928 191.507 153.912 192.613 ;
     RECT  158.736 190.789 161.112 192.613 ;
     RECT  97.44 192.037 97.464 192.707 ;
     RECT  119.376 189.877 119.4 192.707 ;
     RECT  102.576 191.365 102.6 192.803 ;
     RECT  130.464 192.421 132.312 192.853 ;
     RECT  135.888 191.555 151.176 193.189 ;
     RECT  152.16 192.613 153.912 193.189 ;
     RECT  126.6 192.325 127.224 193.379 ;
     RECT  155.568 191.555 155.592 193.427 ;
     RECT  158.496 192.613 161.112 193.427 ;
     RECT  129.696 192.853 132.312 193.523 ;
     RECT  130.464 193.523 132.312 193.859 ;
     RECT  123.36 192.613 123.384 193.955 ;
     RECT  125.424 192.613 125.448 193.955 ;
     RECT  135.888 193.189 153.912 194.579 ;
     RECT  126.6 193.379 127.08 194.821 ;
     RECT  152.736 194.579 153.912 195.539 ;
     RECT  158.736 193.427 161.112 195.587 ;
     RECT  152.928 195.539 153.912 195.781 ;
     RECT  152.928 195.781 154.2 195.925 ;
     RECT  125.856 194.821 127.08 196.067 ;
     RECT  152.928 195.925 155.016 196.067 ;
     RECT  152.928 196.067 153.912 196.115 ;
     RECT  130.464 193.859 130.488 196.357 ;
     RECT  135.888 194.579 151.368 196.405 ;
     RECT  128.688 191.267 128.712 196.885 ;
     RECT  128.592 196.885 128.712 196.931 ;
     RECT  130.176 196.357 130.488 197.077 ;
     RECT  158.88 195.587 161.112 197.173 ;
     RECT  128.592 196.931 128.616 197.267 ;
     RECT  154.992 196.067 155.016 197.411 ;
     RECT  133.728 193.093 133.752 197.749 ;
     RECT  134.784 191.555 134.808 197.749 ;
     RECT  130.176 197.077 130.728 197.795 ;
     RECT  135.888 196.405 151.464 197.893 ;
     RECT  153.6 196.115 153.912 197.893 ;
     RECT  135.888 197.893 151.512 197.987 ;
     RECT  150 197.987 151.512 198.131 ;
     RECT  132 193.859 132.312 198.277 ;
     RECT  133.728 197.749 134.808 198.277 ;
     RECT  132 198.277 134.808 198.323 ;
     RECT  150 198.131 151.416 198.323 ;
     RECT  152.64 197.893 153.912 198.419 ;
     RECT  158.88 197.173 161.88 198.419 ;
     RECT  130.176 197.795 130.488 198.901 ;
     RECT  128.64 198.325 128.664 198.947 ;
     RECT  158.88 198.419 161.112 198.995 ;
     RECT  135.888 197.987 148.92 199.429 ;
     RECT  150 198.323 151.368 199.429 ;
     RECT  130.128 198.901 130.488 199.619 ;
     RECT  135.888 199.429 151.368 200.099 ;
     RECT  159 198.995 161.112 200.149 ;
     RECT  159 200.149 161.16 200.579 ;
     RECT  136.08 200.099 151.368 201.109 ;
     RECT  153.168 198.419 153.912 201.155 ;
     RECT  136.08 201.109 151.608 201.205 ;
     RECT  134.784 198.323 134.808 201.251 ;
     RECT  135.888 201.205 151.608 202.067 ;
     RECT  126.6 196.067 127.08 202.117 ;
     RECT  128.112 201.013 128.136 202.117 ;
     RECT  126.6 202.117 128.136 202.163 ;
     RECT  153.36 201.155 153.912 202.163 ;
     RECT  135.888 202.067 151.368 202.403 ;
     RECT  126.6 202.163 127.704 202.837 ;
     RECT  130.464 199.619 130.488 202.837 ;
     RECT  132 198.323 133.752 203.173 ;
     RECT  126.384 202.837 127.704 203.365 ;
     RECT  126 203.365 127.704 203.507 ;
     RECT  129.744 202.837 130.488 203.555 ;
     RECT  147.456 202.403 151.368 203.747 ;
     RECT  132 203.173 134.376 203.891 ;
     RECT  133.728 203.891 134.376 204.227 ;
     RECT  153.6 202.163 153.912 204.277 ;
     RECT  126 203.507 127.08 204.371 ;
     RECT  130.464 203.555 130.488 204.851 ;
     RECT  135.888 202.403 145.944 205.379 ;
     RECT  141.216 205.379 145.944 205.523 ;
     RECT  126.6 204.371 127.08 205.717 ;
     RECT  130.896 204.901 130.92 205.717 ;
     RECT  132 203.891 132.744 205.717 ;
     RECT  130.896 205.717 132.744 205.763 ;
     RECT  135.888 205.379 140.184 205.765 ;
     RECT  133.728 204.227 133.752 205.811 ;
     RECT  147.552 203.747 151.368 205.813 ;
     RECT  147.456 205.813 151.368 206.293 ;
     RECT  124.8 205.717 127.08 206.387 ;
     RECT  141.312 205.523 145.944 206.387 ;
     RECT  147.12 206.293 151.368 206.531 ;
     RECT  141.888 206.387 145.512 206.675 ;
     RECT  142.56 206.675 145.512 206.963 ;
     RECT  153.312 204.277 153.912 207.157 ;
     RECT  128.448 204.997 128.472 207.539 ;
     RECT  146.592 207.205 146.616 207.875 ;
     RECT  131.136 205.763 132.744 208.115 ;
     RECT  147.936 206.531 151.368 208.213 ;
     RECT  147.936 208.213 151.416 208.355 ;
     RECT  157.056 208.213 157.08 208.355 ;
     RECT  135.744 205.765 140.184 208.597 ;
     RECT  155.04 207.157 155.064 208.643 ;
     RECT  131.184 208.115 132.744 208.645 ;
     RECT  125.76 206.387 127.08 208.787 ;
     RECT  153.312 207.157 154.056 209.125 ;
     RECT  135.744 208.597 140.568 209.219 ;
     RECT  142.8 206.963 145.512 209.653 ;
     RECT  136.32 209.219 140.568 209.795 ;
     RECT  142.608 209.653 145.512 209.795 ;
     RECT  147.936 208.355 149.592 209.891 ;
     RECT  142.608 209.795 144.024 210.323 ;
     RECT  145.152 209.795 145.512 210.707 ;
     RECT  125.52 209.845 125.544 210.947 ;
     RECT  145.296 210.707 145.512 210.947 ;
     RECT  153.312 209.125 154.68 210.947 ;
     RECT  159 200.579 161.112 210.947 ;
     RECT  159 210.947 160.488 211.235 ;
     RECT  142.8 210.323 144.024 211.333 ;
     RECT  131.184 208.645 133.416 211.523 ;
     RECT  145.296 210.947 145.368 211.523 ;
     RECT  131.184 211.523 132.744 211.909 ;
     RECT  136.32 209.795 139.272 212.005 ;
     RECT  140.544 209.795 140.568 212.005 ;
     RECT  145.344 211.523 145.368 212.005 ;
     RECT  153.312 210.947 153.912 212.005 ;
     RECT  136.32 212.005 140.568 212.051 ;
     RECT  135.168 209.749 135.192 212.579 ;
     RECT  131.136 211.909 132.744 212.581 ;
     RECT  151.248 208.355 151.416 212.675 ;
     RECT  147.936 209.891 148.512 212.821 ;
     RECT  149.568 209.891 149.592 212.821 ;
     RECT  152.784 212.005 153.912 212.963 ;
     RECT  136.32 212.051 140.232 213.155 ;
     RECT  131.136 212.581 132.84 213.203 ;
     RECT  149.568 212.821 150.024 213.347 ;
     RECT  131.136 213.203 132.744 213.877 ;
     RECT  130.464 213.877 132.744 213.923 ;
     RECT  126.6 208.787 127.08 214.069 ;
     RECT  141.216 213.877 141.24 214.117 ;
     RECT  145.344 212.005 145.896 214.355 ;
     RECT  141.216 214.117 141.288 214.595 ;
     RECT  159 211.235 159.312 214.741 ;
     RECT  126.6 214.069 128.04 214.837 ;
     RECT  141.264 214.595 141.288 214.883 ;
     RECT  125.424 213.685 125.448 214.931 ;
     RECT  151.248 212.675 151.368 215.075 ;
     RECT  158.496 214.741 159.312 215.411 ;
     RECT  151.344 215.075 151.368 216.083 ;
     RECT  126.6 214.837 128.808 216.131 ;
     RECT  126.6 216.131 127.08 217.717 ;
     RECT  145.344 214.355 145.704 217.763 ;
     RECT  160.464 211.235 160.488 217.763 ;
     RECT  135.072 216.565 135.096 218.195 ;
     RECT  136.32 213.155 139.272 218.197 ;
     RECT  142.608 211.333 144.024 218.867 ;
     RECT  128.784 216.131 128.808 218.963 ;
     RECT  130.464 213.923 130.488 219.013 ;
     RECT  145.344 217.763 145.368 219.541 ;
     RECT  142.8 218.867 144.024 219.685 ;
     RECT  126.6 217.717 127.512 220.067 ;
     RECT  135.888 218.197 139.272 220.067 ;
     RECT  130.464 219.013 130.872 220.115 ;
     RECT  130.464 220.115 130.488 220.643 ;
     RECT  145.344 219.541 145.944 220.643 ;
     RECT  145.344 220.643 145.368 221.219 ;
     RECT  142.8 219.685 144.264 221.221 ;
     RECT  135.888 220.067 138.408 221.605 ;
     RECT  149.568 213.347 149.592 221.701 ;
     RECT  140.496 221.125 140.52 222.085 ;
     RECT  140.496 222.085 140.616 222.131 ;
     RECT  135.36 221.605 138.408 222.179 ;
     RECT  142.8 221.221 144.888 222.229 ;
     RECT  132 213.923 132.744 222.661 ;
     RECT  149.568 221.701 150.264 222.803 ;
     RECT  150.24 222.803 150.264 222.851 ;
     RECT  140.592 222.131 140.616 222.899 ;
     RECT  142.176 222.229 144.888 222.899 ;
     RECT  135.6 222.179 138.408 223.331 ;
     RECT  142.176 222.899 144.024 223.379 ;
     RECT  136.32 223.331 138.408 223.859 ;
     RECT  147.6 212.821 148.512 223.907 ;
     RECT  132 222.661 132.792 224.293 ;
     RECT  142.464 223.379 144.024 224.819 ;
     RECT  140.208 223.909 140.232 225.061 ;
     RECT  139.632 225.061 140.232 225.107 ;
     RECT  149.616 223.957 149.64 225.203 ;
     RECT  153.312 212.963 153.912 225.203 ;
     RECT  153.504 225.203 153.912 225.347 ;
     RECT  132 224.293 133.56 225.589 ;
     RECT  132 225.589 134.04 225.635 ;
     RECT  142.704 224.819 144.024 226.355 ;
     RECT  139.632 225.107 139.656 226.453 ;
     RECT  139.632 226.453 140.568 226.499 ;
     RECT  148.2 223.907 148.512 226.597 ;
     RECT  150.432 226.261 150.456 226.837 ;
     RECT  150.336 226.837 150.456 226.883 ;
     RECT  134.016 225.635 134.04 226.931 ;
     RECT  150.336 226.883 150.36 226.979 ;
     RECT  148.2 226.597 148.632 227.987 ;
     RECT  142.704 226.355 143.304 228.083 ;
     RECT  140.544 226.499 140.568 228.131 ;
     RECT  137.4 223.859 138.408 228.229 ;
     RECT  152.064 227.941 152.088 228.755 ;
     RECT  134.496 227.125 134.52 229.187 ;
     RECT  137.4 228.229 138.504 229.187 ;
     RECT  142.8 228.083 143.304 229.669 ;
     RECT  145.344 224.437 145.368 229.909 ;
     RECT  140.736 229.669 140.76 230.291 ;
     RECT  142.512 229.669 143.304 230.435 ;
     RECT  146.496 228.517 146.52 230.821 ;
     RECT  146.496 230.821 147.048 230.867 ;
     RECT  136.32 223.859 136.344 230.869 ;
     RECT  137.4 229.187 138.216 230.869 ;
     RECT  145.344 229.909 145.416 230.915 ;
     RECT  149.568 230.245 149.592 231.061 ;
     RECT  142.8 230.435 143.304 231.443 ;
     RECT  148.2 227.987 148.512 231.685 ;
     RECT  149.568 231.061 149.64 231.685 ;
     RECT  145.344 230.915 145.368 231.731 ;
     RECT  148.2 231.685 149.64 231.923 ;
     RECT  136.32 230.869 138.216 233.075 ;
     RECT  140.208 230.917 140.232 233.123 ;
     RECT  137.4 233.075 138.216 234.277 ;
     RECT  147.024 230.867 147.048 234.323 ;
     RECT  136.32 233.075 136.344 234.899 ;
     RECT  148.2 231.923 149.352 234.899 ;
     RECT  135.12 233.605 135.144 235.235 ;
     RECT  132 225.635 132.744 235.475 ;
     RECT  137.4 234.277 138.504 235.475 ;
     RECT  137.4 235.475 138.024 236.341 ;
     RECT  135.504 235.957 135.528 236.819 ;
     RECT  136.704 236.341 138.024 237.731 ;
     RECT  144.72 232.405 144.744 237.779 ;
     RECT  141.36 236.725 141.384 238.883 ;
     RECT  147.072 236.485 147.096 238.883 ;
     RECT  137.4 237.731 138.024 239.843 ;
     RECT  142.8 231.443 143.112 240.997 ;
     RECT  145.104 239.653 145.128 241.139 ;
     RECT  142.704 240.997 143.112 242.051 ;
     RECT  126.6 220.067 127.08 274.931 ;
     RECT  2.4 2.151 2.712 369.369 ;
     RECT  7.8 2.151 8.112 369.369 ;
     RECT  13.2 2.151 13.512 369.369 ;
     RECT  18.6 2.151 18.912 369.369 ;
     RECT  24 2.151 24.312 369.369 ;
     RECT  29.4 2.151 29.712 369.369 ;
     RECT  34.8 2.151 35.112 369.369 ;
     RECT  40.2 2.151 40.512 369.369 ;
     RECT  45.6 2.151 45.912 369.369 ;
     RECT  51 2.151 51.312 369.369 ;
     RECT  56.4 2.151 56.712 369.369 ;
     RECT  61.8 2.151 62.112 369.369 ;
     RECT  67.2 2.151 67.512 369.369 ;
     RECT  72.6 2.151 72.912 369.369 ;
     RECT  78 2.151 78.312 369.369 ;
     RECT  83.4 2.151 83.712 369.369 ;
     RECT  88.8 2.151 89.112 369.369 ;
     RECT  94.2 182.339 94.512 369.369 ;
     RECT  99.6 191.507 99.912 369.369 ;
     RECT  105 188.819 105.312 369.369 ;
     RECT  110.4 180.563 110.712 369.369 ;
     RECT  115.8 2.151 116.112 369.369 ;
     RECT  121.2 2.151 121.512 369.369 ;
     RECT  126.6 274.931 126.912 369.369 ;
     RECT  137.4 239.843 137.712 369.369 ;
     RECT  142.8 242.051 143.112 369.369 ;
     RECT  148.2 234.899 148.512 369.369 ;
     RECT  153.6 225.347 153.912 369.369 ;
     RECT  159 215.411 159.312 369.369 ;
     RECT  164.4 181.811 164.712 369.369 ;
     RECT  169.8 2.151 170.112 369.369 ;
     RECT  175.2 2.151 175.512 369.369 ;
     RECT  180.6 2.151 180.912 369.369 ;
     RECT  186 2.151 186.312 369.369 ;
     RECT  191.4 2.151 191.712 369.369 ;
     RECT  196.8 2.151 197.112 369.369 ;
     RECT  202.2 2.151 202.512 369.369 ;
     RECT  207.6 2.151 207.912 369.369 ;
     RECT  213 2.151 213.312 369.369 ;
     RECT  218.4 2.151 218.712 369.369 ;
     RECT  223.8 2.151 224.112 369.369 ;
     RECT  229.2 2.151 229.512 369.369 ;
     RECT  234.6 2.151 234.912 369.369 ;
     RECT  240 2.151 240.312 369.369 ;
     RECT  245.4 2.151 245.712 369.369 ;
     RECT  2.4 369.369 2.52 369.383 ;
     RECT  7.8 369.369 7.92 369.383 ;
     RECT  13.2 369.369 13.32 369.383 ;
     RECT  18.6 369.369 18.72 369.383 ;
     RECT  24 369.369 24.12 369.383 ;
     RECT  29.4 369.369 29.52 369.383 ;
     RECT  34.8 369.369 34.92 369.383 ;
     RECT  40.2 369.369 40.32 369.383 ;
     RECT  45.6 369.369 45.72 369.383 ;
     RECT  51 369.369 51.12 369.383 ;
     RECT  56.4 369.369 56.52 369.383 ;
     RECT  61.8 369.369 61.92 369.383 ;
     RECT  67.2 369.369 67.32 369.383 ;
     RECT  72.6 369.369 72.72 369.383 ;
     RECT  78 369.369 78.12 369.383 ;
     RECT  83.4 369.369 83.52 369.383 ;
     RECT  88.8 369.369 88.92 369.383 ;
     RECT  94.2 369.369 94.32 369.383 ;
     RECT  99.6 369.369 99.72 369.383 ;
     RECT  105 369.369 105.12 369.383 ;
     RECT  110.4 369.369 110.52 369.383 ;
     RECT  115.8 369.369 115.92 369.383 ;
     RECT  121.2 369.369 121.32 369.383 ;
     RECT  126.6 369.369 126.72 369.383 ;
     RECT  132 235.475 132.552 369.383 ;
     RECT  137.4 369.369 137.52 369.383 ;
     RECT  142.8 369.369 142.92 369.383 ;
     RECT  148.2 369.369 148.32 369.383 ;
     RECT  153.6 369.369 153.72 369.383 ;
     RECT  159 369.369 159.12 369.383 ;
     RECT  164.4 369.369 164.52 369.383 ;
     RECT  169.8 369.369 169.92 369.383 ;
     RECT  175.2 369.369 175.32 369.383 ;
     RECT  180.6 369.369 180.72 369.383 ;
     RECT  186 369.369 186.12 369.383 ;
     RECT  191.4 369.369 191.52 369.383 ;
     RECT  196.8 369.369 196.92 369.383 ;
     RECT  202.2 369.369 202.32 369.383 ;
     RECT  207.6 369.369 207.72 369.383 ;
     RECT  213 369.369 213.12 369.383 ;
     RECT  218.4 369.369 218.52 369.383 ;
     RECT  223.8 369.369 223.92 369.383 ;
     RECT  229.2 369.369 229.32 369.383 ;
     RECT  234.6 369.369 234.72 369.383 ;
     RECT  240 369.369 240.12 369.383 ;
     RECT  245.4 369.369 245.52 369.383 ;
     RECT  132.144 369.383 132.552 371.125 ;
     RECT  132.144 371.125 132.648 371.315 ;
     RECT  132.144 371.315 132.552 371.472 ;
     RECT  132.528 371.472 132.552 371.507 ;
  END
END ot_qwen_ctrl_pc_head
END LIBRARY
